VERSION 5.8 ;
BUSBITCHARS "[]" ;
DIVIDERCHAR "/" ;
UNITS
    DATABASE MICRONS 1000 ;
END UNITS

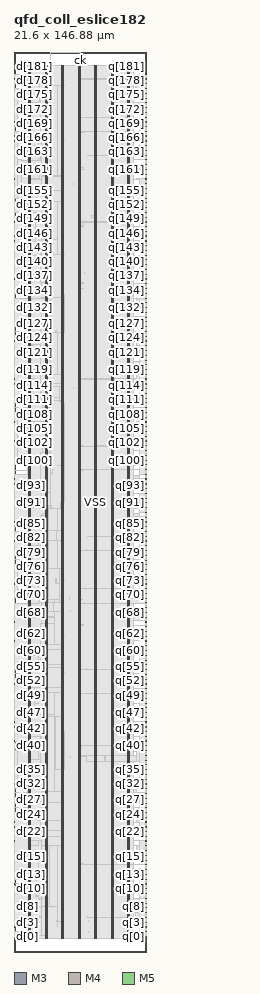
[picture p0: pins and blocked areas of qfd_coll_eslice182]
MACRO qfd_coll_eslice182
  FOREIGN qfd_coll_eslice182 0 0 ;
  CLASS BLOCK ;
  SIZE 21.6 BY 146.88 ;
  PIN ck
    DIRECTION INPUT ;
    USE SIGNAL ;
    PORT
      LAYER M3 ;
        RECT  10.8 146.842 10.818 146.88 ;
    END
    PORT
      LAYER M3 ;
        RECT  10.8 146.731 10.818 146.861 ;
    END
  END ck
  PIN d[0]
    DIRECTION INPUT ;
    USE SIGNAL ;
    PORT
      LAYER M4 ;
        RECT  0 2.544 0.084 2.568 ;
    END
  END d[0]
  PIN d[100]
    DIRECTION INPUT ;
    USE SIGNAL ;
    PORT
      LAYER M4 ;
        RECT  0 80.256 0.084 80.28 ;
    END
  END d[100]
  PIN d[101]
    DIRECTION INPUT ;
    USE SIGNAL ;
    PORT
      LAYER M4 ;
        RECT  0 81.072 0.084 81.096 ;
    END
  END d[101]
  PIN d[102]
    DIRECTION INPUT ;
    USE SIGNAL ;
    PORT
      LAYER M4 ;
        RECT  0 81.84 0.084 81.864 ;
    END
  END d[102]
  PIN d[103]
    DIRECTION INPUT ;
    USE SIGNAL ;
    PORT
      LAYER M4 ;
        RECT  0 82.608 0.084 82.632 ;
    END
  END d[103]
  PIN d[104]
    DIRECTION INPUT ;
    USE SIGNAL ;
    PORT
      LAYER M4 ;
        RECT  0 83.376 0.084 83.4 ;
    END
  END d[104]
  PIN d[105]
    DIRECTION INPUT ;
    USE SIGNAL ;
    PORT
      LAYER M4 ;
        RECT  0 84.144 0.084 84.168 ;
    END
  END d[105]
  PIN d[106]
    DIRECTION INPUT ;
    USE SIGNAL ;
    PORT
      LAYER M4 ;
        RECT  0 84.96 0.084 84.984 ;
    END
  END d[106]
  PIN d[107]
    DIRECTION INPUT ;
    USE SIGNAL ;
    PORT
      LAYER M4 ;
        RECT  0 85.728 0.084 85.752 ;
    END
  END d[107]
  PIN d[108]
    DIRECTION INPUT ;
    USE SIGNAL ;
    PORT
      LAYER M4 ;
        RECT  0 86.496 0.084 86.52 ;
    END
  END d[108]
  PIN d[109]
    DIRECTION INPUT ;
    USE SIGNAL ;
    PORT
      LAYER M4 ;
        RECT  0 87.264 0.084 87.288 ;
    END
  END d[109]
  PIN d[10]
    DIRECTION INPUT ;
    USE SIGNAL ;
    PORT
      LAYER M4 ;
        RECT  0 10.32 0.084 10.344 ;
    END
  END d[10]
  PIN d[110]
    DIRECTION INPUT ;
    USE SIGNAL ;
    PORT
      LAYER M4 ;
        RECT  0 88.032 0.084 88.056 ;
    END
  END d[110]
  PIN d[111]
    DIRECTION INPUT ;
    USE SIGNAL ;
    PORT
      LAYER M4 ;
        RECT  0 88.848 0.084 88.872 ;
    END
  END d[111]
  PIN d[112]
    DIRECTION INPUT ;
    USE SIGNAL ;
    PORT
      LAYER M4 ;
        RECT  0 89.616 0.084 89.64 ;
    END
  END d[112]
  PIN d[113]
    DIRECTION INPUT ;
    USE SIGNAL ;
    PORT
      LAYER M4 ;
        RECT  0 90.384 0.084 90.408 ;
    END
  END d[113]
  PIN d[114]
    DIRECTION INPUT ;
    USE SIGNAL ;
    PORT
      LAYER M4 ;
        RECT  0 91.152 0.084 91.176 ;
    END
  END d[114]
  PIN d[115]
    DIRECTION INPUT ;
    USE SIGNAL ;
    PORT
      LAYER M4 ;
        RECT  0 91.92 0.084 91.944 ;
    END
  END d[115]
  PIN d[116]
    DIRECTION INPUT ;
    USE SIGNAL ;
    PORT
      LAYER M4 ;
        RECT  0 92.688 0.084 92.712 ;
    END
  END d[116]
  PIN d[117]
    DIRECTION INPUT ;
    USE SIGNAL ;
    PORT
      LAYER M4 ;
        RECT  0 93.504 0.084 93.528 ;
    END
  END d[117]
  PIN d[118]
    DIRECTION INPUT ;
    USE SIGNAL ;
    PORT
      LAYER M4 ;
        RECT  0 94.272 0.084 94.296 ;
    END
  END d[118]
  PIN d[119]
    DIRECTION INPUT ;
    USE SIGNAL ;
    PORT
      LAYER M4 ;
        RECT  0 95.04 0.084 95.064 ;
    END
  END d[119]
  PIN d[11]
    DIRECTION INPUT ;
    USE SIGNAL ;
    PORT
      LAYER M4 ;
        RECT  0 11.088 0.084 11.112 ;
    END
  END d[11]
  PIN d[120]
    DIRECTION INPUT ;
    USE SIGNAL ;
    PORT
      LAYER M4 ;
        RECT  0 95.808 0.084 95.832 ;
    END
  END d[120]
  PIN d[121]
    DIRECTION INPUT ;
    USE SIGNAL ;
    PORT
      LAYER M4 ;
        RECT  0 96.576 0.084 96.6 ;
    END
  END d[121]
  PIN d[122]
    DIRECTION INPUT ;
    USE SIGNAL ;
    PORT
      LAYER M4 ;
        RECT  0 97.392 0.084 97.416 ;
    END
  END d[122]
  PIN d[123]
    DIRECTION INPUT ;
    USE SIGNAL ;
    PORT
      LAYER M4 ;
        RECT  0 98.16 0.084 98.184 ;
    END
  END d[123]
  PIN d[124]
    DIRECTION INPUT ;
    USE SIGNAL ;
    PORT
      LAYER M4 ;
        RECT  0 98.928 0.084 98.952 ;
    END
  END d[124]
  PIN d[125]
    DIRECTION INPUT ;
    USE SIGNAL ;
    PORT
      LAYER M4 ;
        RECT  0 99.696 0.084 99.72 ;
    END
  END d[125]
  PIN d[126]
    DIRECTION INPUT ;
    USE SIGNAL ;
    PORT
      LAYER M4 ;
        RECT  0 100.464 0.084 100.488 ;
    END
  END d[126]
  PIN d[127]
    DIRECTION INPUT ;
    USE SIGNAL ;
    PORT
      LAYER M4 ;
        RECT  0 101.28 0.084 101.304 ;
    END
  END d[127]
  PIN d[128]
    DIRECTION INPUT ;
    USE SIGNAL ;
    PORT
      LAYER M4 ;
        RECT  0 102.048 0.084 102.072 ;
    END
  END d[128]
  PIN d[129]
    DIRECTION INPUT ;
    USE SIGNAL ;
    PORT
      LAYER M4 ;
        RECT  0 102.816 0.084 102.84 ;
    END
  END d[129]
  PIN d[12]
    DIRECTION INPUT ;
    USE SIGNAL ;
    PORT
      LAYER M4 ;
        RECT  0 11.856 0.084 11.88 ;
    END
  END d[12]
  PIN d[130]
    DIRECTION INPUT ;
    USE SIGNAL ;
    PORT
      LAYER M4 ;
        RECT  0 103.584 0.084 103.608 ;
    END
  END d[130]
  PIN d[131]
    DIRECTION INPUT ;
    USE SIGNAL ;
    PORT
      LAYER M4 ;
        RECT  0 104.352 0.084 104.376 ;
    END
  END d[131]
  PIN d[132]
    DIRECTION INPUT ;
    USE SIGNAL ;
    PORT
      LAYER M4 ;
        RECT  0 105.168 0.084 105.192 ;
    END
  END d[132]
  PIN d[133]
    DIRECTION INPUT ;
    USE SIGNAL ;
    PORT
      LAYER M4 ;
        RECT  0 105.936 0.084 105.96 ;
    END
  END d[133]
  PIN d[134]
    DIRECTION INPUT ;
    USE SIGNAL ;
    PORT
      LAYER M4 ;
        RECT  0 106.704 0.084 106.728 ;
    END
  END d[134]
  PIN d[135]
    DIRECTION INPUT ;
    USE SIGNAL ;
    PORT
      LAYER M4 ;
        RECT  0 107.472 0.084 107.496 ;
    END
  END d[135]
  PIN d[136]
    DIRECTION INPUT ;
    USE SIGNAL ;
    PORT
      LAYER M4 ;
        RECT  0 108.24 0.084 108.264 ;
    END
  END d[136]
  PIN d[137]
    DIRECTION INPUT ;
    USE SIGNAL ;
    PORT
      LAYER M4 ;
        RECT  0 109.056 0.084 109.08 ;
    END
  END d[137]
  PIN d[138]
    DIRECTION INPUT ;
    USE SIGNAL ;
    PORT
      LAYER M4 ;
        RECT  0 109.824 0.084 109.848 ;
    END
  END d[138]
  PIN d[139]
    DIRECTION INPUT ;
    USE SIGNAL ;
    PORT
      LAYER M4 ;
        RECT  0 110.592 0.084 110.616 ;
    END
  END d[139]
  PIN d[13]
    DIRECTION INPUT ;
    USE SIGNAL ;
    PORT
      LAYER M4 ;
        RECT  0 12.624 0.084 12.648 ;
    END
  END d[13]
  PIN d[140]
    DIRECTION INPUT ;
    USE SIGNAL ;
    PORT
      LAYER M4 ;
        RECT  0 111.36 0.084 111.384 ;
    END
  END d[140]
  PIN d[141]
    DIRECTION INPUT ;
    USE SIGNAL ;
    PORT
      LAYER M4 ;
        RECT  0 112.128 0.084 112.152 ;
    END
  END d[141]
  PIN d[142]
    DIRECTION INPUT ;
    USE SIGNAL ;
    PORT
      LAYER M4 ;
        RECT  0 112.944 0.084 112.968 ;
    END
  END d[142]
  PIN d[143]
    DIRECTION INPUT ;
    USE SIGNAL ;
    PORT
      LAYER M4 ;
        RECT  0 113.712 0.084 113.736 ;
    END
  END d[143]
  PIN d[144]
    DIRECTION INPUT ;
    USE SIGNAL ;
    PORT
      LAYER M4 ;
        RECT  0 114.48 0.084 114.504 ;
    END
  END d[144]
  PIN d[145]
    DIRECTION INPUT ;
    USE SIGNAL ;
    PORT
      LAYER M4 ;
        RECT  0 115.248 0.084 115.272 ;
    END
  END d[145]
  PIN d[146]
    DIRECTION INPUT ;
    USE SIGNAL ;
    PORT
      LAYER M4 ;
        RECT  0 116.016 0.084 116.04 ;
    END
  END d[146]
  PIN d[147]
    DIRECTION INPUT ;
    USE SIGNAL ;
    PORT
      LAYER M4 ;
        RECT  0 116.832 0.084 116.856 ;
    END
  END d[147]
  PIN d[148]
    DIRECTION INPUT ;
    USE SIGNAL ;
    PORT
      LAYER M4 ;
        RECT  0 117.6 0.084 117.624 ;
    END
  END d[148]
  PIN d[149]
    DIRECTION INPUT ;
    USE SIGNAL ;
    PORT
      LAYER M4 ;
        RECT  0 118.368 0.084 118.392 ;
    END
  END d[149]
  PIN d[14]
    DIRECTION INPUT ;
    USE SIGNAL ;
    PORT
      LAYER M4 ;
        RECT  0 13.44 0.084 13.464 ;
    END
  END d[14]
  PIN d[150]
    DIRECTION INPUT ;
    USE SIGNAL ;
    PORT
      LAYER M4 ;
        RECT  0 119.136 0.084 119.16 ;
    END
  END d[150]
  PIN d[151]
    DIRECTION INPUT ;
    USE SIGNAL ;
    PORT
      LAYER M4 ;
        RECT  0 119.904 0.084 119.928 ;
    END
  END d[151]
  PIN d[152]
    DIRECTION INPUT ;
    USE SIGNAL ;
    PORT
      LAYER M4 ;
        RECT  0 120.72 0.084 120.744 ;
    END
  END d[152]
  PIN d[153]
    DIRECTION INPUT ;
    USE SIGNAL ;
    PORT
      LAYER M4 ;
        RECT  0 121.488 0.084 121.512 ;
    END
  END d[153]
  PIN d[154]
    DIRECTION INPUT ;
    USE SIGNAL ;
    PORT
      LAYER M4 ;
        RECT  0 122.256 0.084 122.28 ;
    END
  END d[154]
  PIN d[155]
    DIRECTION INPUT ;
    USE SIGNAL ;
    PORT
      LAYER M4 ;
        RECT  0 123.024 0.084 123.048 ;
    END
  END d[155]
  PIN d[156]
    DIRECTION INPUT ;
    USE SIGNAL ;
    PORT
      LAYER M4 ;
        RECT  0 123.792 0.084 123.816 ;
    END
  END d[156]
  PIN d[157]
    DIRECTION INPUT ;
    USE SIGNAL ;
    PORT
      LAYER M4 ;
        RECT  0 124.56 0.084 124.584 ;
    END
  END d[157]
  PIN d[158]
    DIRECTION INPUT ;
    USE SIGNAL ;
    PORT
      LAYER M4 ;
        RECT  0 125.376 0.084 125.4 ;
    END
  END d[158]
  PIN d[159]
    DIRECTION INPUT ;
    USE SIGNAL ;
    PORT
      LAYER M4 ;
        RECT  0 126.144 0.084 126.168 ;
    END
  END d[159]
  PIN d[15]
    DIRECTION INPUT ;
    USE SIGNAL ;
    PORT
      LAYER M4 ;
        RECT  0 14.208 0.084 14.232 ;
    END
  END d[15]
  PIN d[160]
    DIRECTION INPUT ;
    USE SIGNAL ;
    PORT
      LAYER M4 ;
        RECT  0 126.912 0.084 126.936 ;
    END
  END d[160]
  PIN d[161]
    DIRECTION INPUT ;
    USE SIGNAL ;
    PORT
      LAYER M4 ;
        RECT  0 127.68 0.084 127.704 ;
    END
  END d[161]
  PIN d[162]
    DIRECTION INPUT ;
    USE SIGNAL ;
    PORT
      LAYER M4 ;
        RECT  0 128.448 0.084 128.472 ;
    END
  END d[162]
  PIN d[163]
    DIRECTION INPUT ;
    USE SIGNAL ;
    PORT
      LAYER M4 ;
        RECT  0 129.264 0.084 129.288 ;
    END
  END d[163]
  PIN d[164]
    DIRECTION INPUT ;
    USE SIGNAL ;
    PORT
      LAYER M4 ;
        RECT  0 130.032 0.084 130.056 ;
    END
  END d[164]
  PIN d[165]
    DIRECTION INPUT ;
    USE SIGNAL ;
    PORT
      LAYER M4 ;
        RECT  0 130.8 0.084 130.824 ;
    END
  END d[165]
  PIN d[166]
    DIRECTION INPUT ;
    USE SIGNAL ;
    PORT
      LAYER M4 ;
        RECT  0 131.568 0.084 131.592 ;
    END
  END d[166]
  PIN d[167]
    DIRECTION INPUT ;
    USE SIGNAL ;
    PORT
      LAYER M4 ;
        RECT  0 132.336 0.084 132.36 ;
    END
  END d[167]
  PIN d[168]
    DIRECTION INPUT ;
    USE SIGNAL ;
    PORT
      LAYER M4 ;
        RECT  0 133.152 0.084 133.176 ;
    END
  END d[168]
  PIN d[169]
    DIRECTION INPUT ;
    USE SIGNAL ;
    PORT
      LAYER M4 ;
        RECT  0 133.92 0.084 133.944 ;
    END
  END d[169]
  PIN d[16]
    DIRECTION INPUT ;
    USE SIGNAL ;
    PORT
      LAYER M4 ;
        RECT  0 14.976 0.084 15 ;
    END
  END d[16]
  PIN d[170]
    DIRECTION INPUT ;
    USE SIGNAL ;
    PORT
      LAYER M4 ;
        RECT  0 134.688 0.084 134.712 ;
    END
  END d[170]
  PIN d[171]
    DIRECTION INPUT ;
    USE SIGNAL ;
    PORT
      LAYER M4 ;
        RECT  0 135.456 0.084 135.48 ;
    END
  END d[171]
  PIN d[172]
    DIRECTION INPUT ;
    USE SIGNAL ;
    PORT
      LAYER M4 ;
        RECT  0 136.224 0.084 136.248 ;
    END
  END d[172]
  PIN d[173]
    DIRECTION INPUT ;
    USE SIGNAL ;
    PORT
      LAYER M4 ;
        RECT  0 137.04 0.084 137.064 ;
    END
  END d[173]
  PIN d[174]
    DIRECTION INPUT ;
    USE SIGNAL ;
    PORT
      LAYER M4 ;
        RECT  0 137.808 0.084 137.832 ;
    END
  END d[174]
  PIN d[175]
    DIRECTION INPUT ;
    USE SIGNAL ;
    PORT
      LAYER M4 ;
        RECT  0 138.576 0.084 138.6 ;
    END
  END d[175]
  PIN d[176]
    DIRECTION INPUT ;
    USE SIGNAL ;
    PORT
      LAYER M4 ;
        RECT  0 139.344 0.084 139.368 ;
    END
  END d[176]
  PIN d[177]
    DIRECTION INPUT ;
    USE SIGNAL ;
    PORT
      LAYER M4 ;
        RECT  0 140.112 0.084 140.136 ;
    END
  END d[177]
  PIN d[178]
    DIRECTION INPUT ;
    USE SIGNAL ;
    PORT
      LAYER M4 ;
        RECT  0 140.928 0.084 140.952 ;
    END
  END d[178]
  PIN d[179]
    DIRECTION INPUT ;
    USE SIGNAL ;
    PORT
      LAYER M4 ;
        RECT  0 141.696 0.084 141.72 ;
    END
  END d[179]
  PIN d[17]
    DIRECTION INPUT ;
    USE SIGNAL ;
    PORT
      LAYER M4 ;
        RECT  0 15.744 0.084 15.768 ;
    END
  END d[17]
  PIN d[180]
    DIRECTION INPUT ;
    USE SIGNAL ;
    PORT
      LAYER M4 ;
        RECT  0 142.464 0.084 142.488 ;
    END
  END d[180]
  PIN d[181]
    DIRECTION INPUT ;
    USE SIGNAL ;
    PORT
      LAYER M4 ;
        RECT  0 143.232 0.084 143.256 ;
    END
  END d[181]
  PIN d[18]
    DIRECTION INPUT ;
    USE SIGNAL ;
    PORT
      LAYER M4 ;
        RECT  0 16.512 0.084 16.536 ;
    END
  END d[18]
  PIN d[19]
    DIRECTION INPUT ;
    USE SIGNAL ;
    PORT
      LAYER M4 ;
        RECT  0 17.328 0.084 17.352 ;
    END
  END d[19]
  PIN d[1]
    DIRECTION INPUT ;
    USE SIGNAL ;
    PORT
      LAYER M4 ;
        RECT  0 3.312 0.084 3.336 ;
    END
  END d[1]
  PIN d[20]
    DIRECTION INPUT ;
    USE SIGNAL ;
    PORT
      LAYER M4 ;
        RECT  0 18.096 0.084 18.12 ;
    END
  END d[20]
  PIN d[21]
    DIRECTION INPUT ;
    USE SIGNAL ;
    PORT
      LAYER M4 ;
        RECT  0 18.864 0.084 18.888 ;
    END
  END d[21]
  PIN d[22]
    DIRECTION INPUT ;
    USE SIGNAL ;
    PORT
      LAYER M4 ;
        RECT  0 19.632 0.084 19.656 ;
    END
  END d[22]
  PIN d[23]
    DIRECTION INPUT ;
    USE SIGNAL ;
    PORT
      LAYER M4 ;
        RECT  0 20.4 0.084 20.424 ;
    END
  END d[23]
  PIN d[24]
    DIRECTION INPUT ;
    USE SIGNAL ;
    PORT
      LAYER M4 ;
        RECT  0 21.216 0.084 21.24 ;
    END
  END d[24]
  PIN d[25]
    DIRECTION INPUT ;
    USE SIGNAL ;
    PORT
      LAYER M4 ;
        RECT  0 21.984 0.084 22.008 ;
    END
  END d[25]
  PIN d[26]
    DIRECTION INPUT ;
    USE SIGNAL ;
    PORT
      LAYER M4 ;
        RECT  0 22.752 0.084 22.776 ;
    END
  END d[26]
  PIN d[27]
    DIRECTION INPUT ;
    USE SIGNAL ;
    PORT
      LAYER M4 ;
        RECT  0 23.52 0.084 23.544 ;
    END
  END d[27]
  PIN d[28]
    DIRECTION INPUT ;
    USE SIGNAL ;
    PORT
      LAYER M4 ;
        RECT  0 24.288 0.084 24.312 ;
    END
  END d[28]
  PIN d[29]
    DIRECTION INPUT ;
    USE SIGNAL ;
    PORT
      LAYER M4 ;
        RECT  0 25.104 0.084 25.128 ;
    END
  END d[29]
  PIN d[2]
    DIRECTION INPUT ;
    USE SIGNAL ;
    PORT
      LAYER M4 ;
        RECT  0 4.08 0.084 4.104 ;
    END
  END d[2]
  PIN d[30]
    DIRECTION INPUT ;
    USE SIGNAL ;
    PORT
      LAYER M4 ;
        RECT  0 25.872 0.084 25.896 ;
    END
  END d[30]
  PIN d[31]
    DIRECTION INPUT ;
    USE SIGNAL ;
    PORT
      LAYER M4 ;
        RECT  0 26.64 0.084 26.664 ;
    END
  END d[31]
  PIN d[32]
    DIRECTION INPUT ;
    USE SIGNAL ;
    PORT
      LAYER M4 ;
        RECT  0 27.408 0.084 27.432 ;
    END
  END d[32]
  PIN d[33]
    DIRECTION INPUT ;
    USE SIGNAL ;
    PORT
      LAYER M4 ;
        RECT  0 28.176 0.084 28.2 ;
    END
  END d[33]
  PIN d[34]
    DIRECTION INPUT ;
    USE SIGNAL ;
    PORT
      LAYER M4 ;
        RECT  0 28.944 0.084 28.968 ;
    END
  END d[34]
  PIN d[35]
    DIRECTION INPUT ;
    USE SIGNAL ;
    PORT
      LAYER M4 ;
        RECT  0 29.76 0.084 29.784 ;
    END
  END d[35]
  PIN d[36]
    DIRECTION INPUT ;
    USE SIGNAL ;
    PORT
      LAYER M4 ;
        RECT  0 30.528 0.084 30.552 ;
    END
  END d[36]
  PIN d[37]
    DIRECTION INPUT ;
    USE SIGNAL ;
    PORT
      LAYER M4 ;
        RECT  0 31.296 0.084 31.32 ;
    END
  END d[37]
  PIN d[38]
    DIRECTION INPUT ;
    USE SIGNAL ;
    PORT
      LAYER M4 ;
        RECT  0 32.064 0.084 32.088 ;
    END
  END d[38]
  PIN d[39]
    DIRECTION INPUT ;
    USE SIGNAL ;
    PORT
      LAYER M4 ;
        RECT  0 32.832 0.084 32.856 ;
    END
  END d[39]
  PIN d[3]
    DIRECTION INPUT ;
    USE SIGNAL ;
    PORT
      LAYER M4 ;
        RECT  0 4.848 0.084 4.872 ;
    END
  END d[3]
  PIN d[40]
    DIRECTION INPUT ;
    USE SIGNAL ;
    PORT
      LAYER M4 ;
        RECT  0 33.648 0.084 33.672 ;
    END
  END d[40]
  PIN d[41]
    DIRECTION INPUT ;
    USE SIGNAL ;
    PORT
      LAYER M4 ;
        RECT  0 34.416 0.084 34.44 ;
    END
  END d[41]
  PIN d[42]
    DIRECTION INPUT ;
    USE SIGNAL ;
    PORT
      LAYER M4 ;
        RECT  0 35.184 0.084 35.208 ;
    END
  END d[42]
  PIN d[43]
    DIRECTION INPUT ;
    USE SIGNAL ;
    PORT
      LAYER M4 ;
        RECT  0 35.952 0.084 35.976 ;
    END
  END d[43]
  PIN d[44]
    DIRECTION INPUT ;
    USE SIGNAL ;
    PORT
      LAYER M4 ;
        RECT  0 36.72 0.084 36.744 ;
    END
  END d[44]
  PIN d[45]
    DIRECTION INPUT ;
    USE SIGNAL ;
    PORT
      LAYER M4 ;
        RECT  0 37.536 0.084 37.56 ;
    END
  END d[45]
  PIN d[46]
    DIRECTION INPUT ;
    USE SIGNAL ;
    PORT
      LAYER M4 ;
        RECT  0 38.304 0.084 38.328 ;
    END
  END d[46]
  PIN d[47]
    DIRECTION INPUT ;
    USE SIGNAL ;
    PORT
      LAYER M4 ;
        RECT  0 39.072 0.084 39.096 ;
    END
  END d[47]
  PIN d[48]
    DIRECTION INPUT ;
    USE SIGNAL ;
    PORT
      LAYER M4 ;
        RECT  0 39.84 0.084 39.864 ;
    END
  END d[48]
  PIN d[49]
    DIRECTION INPUT ;
    USE SIGNAL ;
    PORT
      LAYER M4 ;
        RECT  0 40.608 0.084 40.632 ;
    END
  END d[49]
  PIN d[4]
    DIRECTION INPUT ;
    USE SIGNAL ;
    PORT
      LAYER M4 ;
        RECT  0 5.664 0.084 5.688 ;
    END
  END d[4]
  PIN d[50]
    DIRECTION INPUT ;
    USE SIGNAL ;
    PORT
      LAYER M4 ;
        RECT  0 41.424 0.084 41.448 ;
    END
  END d[50]
  PIN d[51]
    DIRECTION INPUT ;
    USE SIGNAL ;
    PORT
      LAYER M4 ;
        RECT  0 42.192 0.084 42.216 ;
    END
  END d[51]
  PIN d[52]
    DIRECTION INPUT ;
    USE SIGNAL ;
    PORT
      LAYER M4 ;
        RECT  0 42.96 0.084 42.984 ;
    END
  END d[52]
  PIN d[53]
    DIRECTION INPUT ;
    USE SIGNAL ;
    PORT
      LAYER M4 ;
        RECT  0 43.728 0.084 43.752 ;
    END
  END d[53]
  PIN d[54]
    DIRECTION INPUT ;
    USE SIGNAL ;
    PORT
      LAYER M4 ;
        RECT  0 44.496 0.084 44.52 ;
    END
  END d[54]
  PIN d[55]
    DIRECTION INPUT ;
    USE SIGNAL ;
    PORT
      LAYER M4 ;
        RECT  0 45.312 0.084 45.336 ;
    END
  END d[55]
  PIN d[56]
    DIRECTION INPUT ;
    USE SIGNAL ;
    PORT
      LAYER M4 ;
        RECT  0 46.08 0.084 46.104 ;
    END
  END d[56]
  PIN d[57]
    DIRECTION INPUT ;
    USE SIGNAL ;
    PORT
      LAYER M4 ;
        RECT  0 46.848 0.084 46.872 ;
    END
  END d[57]
  PIN d[58]
    DIRECTION INPUT ;
    USE SIGNAL ;
    PORT
      LAYER M4 ;
        RECT  0 47.616 0.084 47.64 ;
    END
  END d[58]
  PIN d[59]
    DIRECTION INPUT ;
    USE SIGNAL ;
    PORT
      LAYER M4 ;
        RECT  0 48.384 0.084 48.408 ;
    END
  END d[59]
  PIN d[5]
    DIRECTION INPUT ;
    USE SIGNAL ;
    PORT
      LAYER M4 ;
        RECT  0 6.432 0.084 6.456 ;
    END
  END d[5]
  PIN d[60]
    DIRECTION INPUT ;
    USE SIGNAL ;
    PORT
      LAYER M4 ;
        RECT  0 49.2 0.084 49.224 ;
    END
  END d[60]
  PIN d[61]
    DIRECTION INPUT ;
    USE SIGNAL ;
    PORT
      LAYER M4 ;
        RECT  0 49.968 0.084 49.992 ;
    END
  END d[61]
  PIN d[62]
    DIRECTION INPUT ;
    USE SIGNAL ;
    PORT
      LAYER M4 ;
        RECT  0 50.736 0.084 50.76 ;
    END
  END d[62]
  PIN d[63]
    DIRECTION INPUT ;
    USE SIGNAL ;
    PORT
      LAYER M4 ;
        RECT  0 51.504 0.084 51.528 ;
    END
  END d[63]
  PIN d[64]
    DIRECTION INPUT ;
    USE SIGNAL ;
    PORT
      LAYER M4 ;
        RECT  0 52.272 0.084 52.296 ;
    END
  END d[64]
  PIN d[65]
    DIRECTION INPUT ;
    USE SIGNAL ;
    PORT
      LAYER M4 ;
        RECT  0 53.088 0.084 53.112 ;
    END
  END d[65]
  PIN d[66]
    DIRECTION INPUT ;
    USE SIGNAL ;
    PORT
      LAYER M4 ;
        RECT  0 53.856 0.084 53.88 ;
    END
  END d[66]
  PIN d[67]
    DIRECTION INPUT ;
    USE SIGNAL ;
    PORT
      LAYER M4 ;
        RECT  0 54.624 0.084 54.648 ;
    END
  END d[67]
  PIN d[68]
    DIRECTION INPUT ;
    USE SIGNAL ;
    PORT
      LAYER M4 ;
        RECT  0 55.392 0.084 55.416 ;
    END
  END d[68]
  PIN d[69]
    DIRECTION INPUT ;
    USE SIGNAL ;
    PORT
      LAYER M4 ;
        RECT  0 56.16 0.084 56.184 ;
    END
  END d[69]
  PIN d[6]
    DIRECTION INPUT ;
    USE SIGNAL ;
    PORT
      LAYER M4 ;
        RECT  0 7.2 0.084 7.224 ;
    END
  END d[6]
  PIN d[70]
    DIRECTION INPUT ;
    USE SIGNAL ;
    PORT
      LAYER M4 ;
        RECT  0 56.976 0.084 57 ;
    END
  END d[70]
  PIN d[71]
    DIRECTION INPUT ;
    USE SIGNAL ;
    PORT
      LAYER M4 ;
        RECT  0 57.744 0.084 57.768 ;
    END
  END d[71]
  PIN d[72]
    DIRECTION INPUT ;
    USE SIGNAL ;
    PORT
      LAYER M4 ;
        RECT  0 58.512 0.084 58.536 ;
    END
  END d[72]
  PIN d[73]
    DIRECTION INPUT ;
    USE SIGNAL ;
    PORT
      LAYER M4 ;
        RECT  0 59.28 0.084 59.304 ;
    END
  END d[73]
  PIN d[74]
    DIRECTION INPUT ;
    USE SIGNAL ;
    PORT
      LAYER M4 ;
        RECT  0 60.048 0.084 60.072 ;
    END
  END d[74]
  PIN d[75]
    DIRECTION INPUT ;
    USE SIGNAL ;
    PORT
      LAYER M4 ;
        RECT  0 60.816 0.084 60.84 ;
    END
  END d[75]
  PIN d[76]
    DIRECTION INPUT ;
    USE SIGNAL ;
    PORT
      LAYER M4 ;
        RECT  0 61.632 0.084 61.656 ;
    END
  END d[76]
  PIN d[77]
    DIRECTION INPUT ;
    USE SIGNAL ;
    PORT
      LAYER M4 ;
        RECT  0 62.4 0.084 62.424 ;
    END
  END d[77]
  PIN d[78]
    DIRECTION INPUT ;
    USE SIGNAL ;
    PORT
      LAYER M4 ;
        RECT  0 63.168 0.084 63.192 ;
    END
  END d[78]
  PIN d[79]
    DIRECTION INPUT ;
    USE SIGNAL ;
    PORT
      LAYER M4 ;
        RECT  0 63.936 0.084 63.96 ;
    END
  END d[79]
  PIN d[7]
    DIRECTION INPUT ;
    USE SIGNAL ;
    PORT
      LAYER M4 ;
        RECT  0 7.968 0.084 7.992 ;
    END
  END d[7]
  PIN d[80]
    DIRECTION INPUT ;
    USE SIGNAL ;
    PORT
      LAYER M4 ;
        RECT  0 64.704 0.084 64.728 ;
    END
  END d[80]
  PIN d[81]
    DIRECTION INPUT ;
    USE SIGNAL ;
    PORT
      LAYER M4 ;
        RECT  0 65.52 0.084 65.544 ;
    END
  END d[81]
  PIN d[82]
    DIRECTION INPUT ;
    USE SIGNAL ;
    PORT
      LAYER M4 ;
        RECT  0 66.288 0.084 66.312 ;
    END
  END d[82]
  PIN d[83]
    DIRECTION INPUT ;
    USE SIGNAL ;
    PORT
      LAYER M4 ;
        RECT  0 67.056 0.084 67.08 ;
    END
  END d[83]
  PIN d[84]
    DIRECTION INPUT ;
    USE SIGNAL ;
    PORT
      LAYER M4 ;
        RECT  0 67.824 0.084 67.848 ;
    END
  END d[84]
  PIN d[85]
    DIRECTION INPUT ;
    USE SIGNAL ;
    PORT
      LAYER M4 ;
        RECT  0 68.592 0.084 68.616 ;
    END
  END d[85]
  PIN d[86]
    DIRECTION INPUT ;
    USE SIGNAL ;
    PORT
      LAYER M4 ;
        RECT  0 69.408 0.084 69.432 ;
    END
  END d[86]
  PIN d[87]
    DIRECTION INPUT ;
    USE SIGNAL ;
    PORT
      LAYER M4 ;
        RECT  0 70.176 0.084 70.2 ;
    END
  END d[87]
  PIN d[88]
    DIRECTION INPUT ;
    USE SIGNAL ;
    PORT
      LAYER M4 ;
        RECT  0 70.944 0.084 70.968 ;
    END
  END d[88]
  PIN d[89]
    DIRECTION INPUT ;
    USE SIGNAL ;
    PORT
      LAYER M4 ;
        RECT  0 71.712 0.084 71.736 ;
    END
  END d[89]
  PIN d[8]
    DIRECTION INPUT ;
    USE SIGNAL ;
    PORT
      LAYER M4 ;
        RECT  0 8.736 0.084 8.76 ;
    END
  END d[8]
  PIN d[90]
    DIRECTION INPUT ;
    USE SIGNAL ;
    PORT
      LAYER M4 ;
        RECT  0 72.48 0.084 72.504 ;
    END
  END d[90]
  PIN d[91]
    DIRECTION INPUT ;
    USE SIGNAL ;
    PORT
      LAYER M4 ;
        RECT  0 73.296 0.084 73.32 ;
    END
  END d[91]
  PIN d[92]
    DIRECTION INPUT ;
    USE SIGNAL ;
    PORT
      LAYER M4 ;
        RECT  0 74.064 0.084 74.088 ;
    END
  END d[92]
  PIN d[93]
    DIRECTION INPUT ;
    USE SIGNAL ;
    PORT
      LAYER M4 ;
        RECT  0 74.832 0.084 74.856 ;
    END
  END d[93]
  PIN d[94]
    DIRECTION INPUT ;
    USE SIGNAL ;
    PORT
      LAYER M4 ;
        RECT  0 75.6 0.084 75.624 ;
    END
  END d[94]
  PIN d[95]
    DIRECTION INPUT ;
    USE SIGNAL ;
    PORT
      LAYER M4 ;
        RECT  0 76.368 0.084 76.392 ;
    END
  END d[95]
  PIN d[96]
    DIRECTION INPUT ;
    USE SIGNAL ;
    PORT
      LAYER M4 ;
        RECT  0 77.184 0.084 77.208 ;
    END
  END d[96]
  PIN d[97]
    DIRECTION INPUT ;
    USE SIGNAL ;
    PORT
      LAYER M4 ;
        RECT  0 77.952 0.084 77.976 ;
    END
  END d[97]
  PIN d[98]
    DIRECTION INPUT ;
    USE SIGNAL ;
    PORT
      LAYER M4 ;
        RECT  0 78.72 0.084 78.744 ;
    END
  END d[98]
  PIN d[99]
    DIRECTION INPUT ;
    USE SIGNAL ;
    PORT
      LAYER M4 ;
        RECT  0 79.488 0.084 79.512 ;
    END
  END d[99]
  PIN d[9]
    DIRECTION INPUT ;
    USE SIGNAL ;
    PORT
      LAYER M4 ;
        RECT  0 9.552 0.084 9.576 ;
    END
  END d[9]
  PIN q[0]
    DIRECTION OUTPUT ;
    USE SIGNAL ;
    PORT
      LAYER M4 ;
        RECT  21.516 2.544 21.6 2.568 ;
    END
  END q[0]
  PIN q[100]
    DIRECTION OUTPUT ;
    USE SIGNAL ;
    PORT
      LAYER M4 ;
        RECT  21.516 80.256 21.6 80.28 ;
    END
  END q[100]
  PIN q[101]
    DIRECTION OUTPUT ;
    USE SIGNAL ;
    PORT
      LAYER M4 ;
        RECT  21.516 81.072 21.6 81.096 ;
    END
  END q[101]
  PIN q[102]
    DIRECTION OUTPUT ;
    USE SIGNAL ;
    PORT
      LAYER M4 ;
        RECT  21.516 81.84 21.6 81.864 ;
    END
  END q[102]
  PIN q[103]
    DIRECTION OUTPUT ;
    USE SIGNAL ;
    PORT
      LAYER M4 ;
        RECT  21.516 82.608 21.6 82.632 ;
    END
  END q[103]
  PIN q[104]
    DIRECTION OUTPUT ;
    USE SIGNAL ;
    PORT
      LAYER M4 ;
        RECT  21.516 83.376 21.6 83.4 ;
    END
  END q[104]
  PIN q[105]
    DIRECTION OUTPUT ;
    USE SIGNAL ;
    PORT
      LAYER M4 ;
        RECT  21.516 84.144 21.6 84.168 ;
    END
  END q[105]
  PIN q[106]
    DIRECTION OUTPUT ;
    USE SIGNAL ;
    PORT
      LAYER M4 ;
        RECT  21.516 84.96 21.6 84.984 ;
    END
  END q[106]
  PIN q[107]
    DIRECTION OUTPUT ;
    USE SIGNAL ;
    PORT
      LAYER M4 ;
        RECT  21.516 85.728 21.6 85.752 ;
    END
  END q[107]
  PIN q[108]
    DIRECTION OUTPUT ;
    USE SIGNAL ;
    PORT
      LAYER M4 ;
        RECT  21.516 86.496 21.6 86.52 ;
    END
  END q[108]
  PIN q[109]
    DIRECTION OUTPUT ;
    USE SIGNAL ;
    PORT
      LAYER M4 ;
        RECT  21.516 87.264 21.6 87.288 ;
    END
  END q[109]
  PIN q[10]
    DIRECTION OUTPUT ;
    USE SIGNAL ;
    PORT
      LAYER M4 ;
        RECT  21.516 10.32 21.6 10.344 ;
    END
  END q[10]
  PIN q[110]
    DIRECTION OUTPUT ;
    USE SIGNAL ;
    PORT
      LAYER M4 ;
        RECT  21.516 88.032 21.6 88.056 ;
    END
  END q[110]
  PIN q[111]
    DIRECTION OUTPUT ;
    USE SIGNAL ;
    PORT
      LAYER M4 ;
        RECT  21.516 88.848 21.6 88.872 ;
    END
  END q[111]
  PIN q[112]
    DIRECTION OUTPUT ;
    USE SIGNAL ;
    PORT
      LAYER M4 ;
        RECT  21.516 89.616 21.6 89.64 ;
    END
  END q[112]
  PIN q[113]
    DIRECTION OUTPUT ;
    USE SIGNAL ;
    PORT
      LAYER M4 ;
        RECT  21.516 90.384 21.6 90.408 ;
    END
  END q[113]
  PIN q[114]
    DIRECTION OUTPUT ;
    USE SIGNAL ;
    PORT
      LAYER M4 ;
        RECT  21.516 91.152 21.6 91.176 ;
    END
  END q[114]
  PIN q[115]
    DIRECTION OUTPUT ;
    USE SIGNAL ;
    PORT
      LAYER M4 ;
        RECT  21.516 91.92 21.6 91.944 ;
    END
  END q[115]
  PIN q[116]
    DIRECTION OUTPUT ;
    USE SIGNAL ;
    PORT
      LAYER M4 ;
        RECT  21.516 92.688 21.6 92.712 ;
    END
  END q[116]
  PIN q[117]
    DIRECTION OUTPUT ;
    USE SIGNAL ;
    PORT
      LAYER M4 ;
        RECT  21.516 93.504 21.6 93.528 ;
    END
  END q[117]
  PIN q[118]
    DIRECTION OUTPUT ;
    USE SIGNAL ;
    PORT
      LAYER M4 ;
        RECT  21.516 94.272 21.6 94.296 ;
    END
  END q[118]
  PIN q[119]
    DIRECTION OUTPUT ;
    USE SIGNAL ;
    PORT
      LAYER M4 ;
        RECT  21.516 95.04 21.6 95.064 ;
    END
  END q[119]
  PIN q[11]
    DIRECTION OUTPUT ;
    USE SIGNAL ;
    PORT
      LAYER M4 ;
        RECT  21.516 11.088 21.6 11.112 ;
    END
  END q[11]
  PIN q[120]
    DIRECTION OUTPUT ;
    USE SIGNAL ;
    PORT
      LAYER M4 ;
        RECT  21.516 95.808 21.6 95.832 ;
    END
  END q[120]
  PIN q[121]
    DIRECTION OUTPUT ;
    USE SIGNAL ;
    PORT
      LAYER M4 ;
        RECT  21.516 96.576 21.6 96.6 ;
    END
  END q[121]
  PIN q[122]
    DIRECTION OUTPUT ;
    USE SIGNAL ;
    PORT
      LAYER M4 ;
        RECT  21.516 97.392 21.6 97.416 ;
    END
  END q[122]
  PIN q[123]
    DIRECTION OUTPUT ;
    USE SIGNAL ;
    PORT
      LAYER M4 ;
        RECT  21.516 98.16 21.6 98.184 ;
    END
  END q[123]
  PIN q[124]
    DIRECTION OUTPUT ;
    USE SIGNAL ;
    PORT
      LAYER M4 ;
        RECT  21.516 98.928 21.6 98.952 ;
    END
  END q[124]
  PIN q[125]
    DIRECTION OUTPUT ;
    USE SIGNAL ;
    PORT
      LAYER M4 ;
        RECT  21.516 99.696 21.6 99.72 ;
    END
  END q[125]
  PIN q[126]
    DIRECTION OUTPUT ;
    USE SIGNAL ;
    PORT
      LAYER M4 ;
        RECT  21.516 100.464 21.6 100.488 ;
    END
  END q[126]
  PIN q[127]
    DIRECTION OUTPUT ;
    USE SIGNAL ;
    PORT
      LAYER M4 ;
        RECT  21.516 101.28 21.6 101.304 ;
    END
  END q[127]
  PIN q[128]
    DIRECTION OUTPUT ;
    USE SIGNAL ;
    PORT
      LAYER M4 ;
        RECT  21.516 102.048 21.6 102.072 ;
    END
  END q[128]
  PIN q[129]
    DIRECTION OUTPUT ;
    USE SIGNAL ;
    PORT
      LAYER M4 ;
        RECT  21.516 102.816 21.6 102.84 ;
    END
  END q[129]
  PIN q[12]
    DIRECTION OUTPUT ;
    USE SIGNAL ;
    PORT
      LAYER M4 ;
        RECT  21.516 11.856 21.6 11.88 ;
    END
  END q[12]
  PIN q[130]
    DIRECTION OUTPUT ;
    USE SIGNAL ;
    PORT
      LAYER M4 ;
        RECT  21.516 103.584 21.6 103.608 ;
    END
  END q[130]
  PIN q[131]
    DIRECTION OUTPUT ;
    USE SIGNAL ;
    PORT
      LAYER M4 ;
        RECT  21.516 104.352 21.6 104.376 ;
    END
  END q[131]
  PIN q[132]
    DIRECTION OUTPUT ;
    USE SIGNAL ;
    PORT
      LAYER M4 ;
        RECT  21.516 105.168 21.6 105.192 ;
    END
  END q[132]
  PIN q[133]
    DIRECTION OUTPUT ;
    USE SIGNAL ;
    PORT
      LAYER M4 ;
        RECT  21.516 105.936 21.6 105.96 ;
    END
  END q[133]
  PIN q[134]
    DIRECTION OUTPUT ;
    USE SIGNAL ;
    PORT
      LAYER M4 ;
        RECT  21.516 106.704 21.6 106.728 ;
    END
  END q[134]
  PIN q[135]
    DIRECTION OUTPUT ;
    USE SIGNAL ;
    PORT
      LAYER M4 ;
        RECT  21.516 107.472 21.6 107.496 ;
    END
  END q[135]
  PIN q[136]
    DIRECTION OUTPUT ;
    USE SIGNAL ;
    PORT
      LAYER M4 ;
        RECT  21.516 108.24 21.6 108.264 ;
    END
  END q[136]
  PIN q[137]
    DIRECTION OUTPUT ;
    USE SIGNAL ;
    PORT
      LAYER M4 ;
        RECT  21.516 109.056 21.6 109.08 ;
    END
  END q[137]
  PIN q[138]
    DIRECTION OUTPUT ;
    USE SIGNAL ;
    PORT
      LAYER M4 ;
        RECT  21.516 109.824 21.6 109.848 ;
    END
  END q[138]
  PIN q[139]
    DIRECTION OUTPUT ;
    USE SIGNAL ;
    PORT
      LAYER M4 ;
        RECT  21.516 110.592 21.6 110.616 ;
    END
  END q[139]
  PIN q[13]
    DIRECTION OUTPUT ;
    USE SIGNAL ;
    PORT
      LAYER M4 ;
        RECT  21.516 12.624 21.6 12.648 ;
    END
  END q[13]
  PIN q[140]
    DIRECTION OUTPUT ;
    USE SIGNAL ;
    PORT
      LAYER M4 ;
        RECT  21.516 111.36 21.6 111.384 ;
    END
  END q[140]
  PIN q[141]
    DIRECTION OUTPUT ;
    USE SIGNAL ;
    PORT
      LAYER M4 ;
        RECT  21.516 112.128 21.6 112.152 ;
    END
  END q[141]
  PIN q[142]
    DIRECTION OUTPUT ;
    USE SIGNAL ;
    PORT
      LAYER M4 ;
        RECT  21.516 112.944 21.6 112.968 ;
    END
  END q[142]
  PIN q[143]
    DIRECTION OUTPUT ;
    USE SIGNAL ;
    PORT
      LAYER M4 ;
        RECT  21.516 113.712 21.6 113.736 ;
    END
  END q[143]
  PIN q[144]
    DIRECTION OUTPUT ;
    USE SIGNAL ;
    PORT
      LAYER M4 ;
        RECT  21.516 114.48 21.6 114.504 ;
    END
  END q[144]
  PIN q[145]
    DIRECTION OUTPUT ;
    USE SIGNAL ;
    PORT
      LAYER M4 ;
        RECT  21.516 115.248 21.6 115.272 ;
    END
  END q[145]
  PIN q[146]
    DIRECTION OUTPUT ;
    USE SIGNAL ;
    PORT
      LAYER M4 ;
        RECT  21.516 116.016 21.6 116.04 ;
    END
  END q[146]
  PIN q[147]
    DIRECTION OUTPUT ;
    USE SIGNAL ;
    PORT
      LAYER M4 ;
        RECT  21.516 116.832 21.6 116.856 ;
    END
  END q[147]
  PIN q[148]
    DIRECTION OUTPUT ;
    USE SIGNAL ;
    PORT
      LAYER M4 ;
        RECT  21.516 117.6 21.6 117.624 ;
    END
  END q[148]
  PIN q[149]
    DIRECTION OUTPUT ;
    USE SIGNAL ;
    PORT
      LAYER M4 ;
        RECT  21.516 118.368 21.6 118.392 ;
    END
  END q[149]
  PIN q[14]
    DIRECTION OUTPUT ;
    USE SIGNAL ;
    PORT
      LAYER M4 ;
        RECT  21.516 13.44 21.6 13.464 ;
    END
  END q[14]
  PIN q[150]
    DIRECTION OUTPUT ;
    USE SIGNAL ;
    PORT
      LAYER M4 ;
        RECT  21.516 119.136 21.6 119.16 ;
    END
  END q[150]
  PIN q[151]
    DIRECTION OUTPUT ;
    USE SIGNAL ;
    PORT
      LAYER M4 ;
        RECT  21.516 119.904 21.6 119.928 ;
    END
  END q[151]
  PIN q[152]
    DIRECTION OUTPUT ;
    USE SIGNAL ;
    PORT
      LAYER M4 ;
        RECT  21.516 120.72 21.6 120.744 ;
    END
  END q[152]
  PIN q[153]
    DIRECTION OUTPUT ;
    USE SIGNAL ;
    PORT
      LAYER M4 ;
        RECT  21.516 121.488 21.6 121.512 ;
    END
  END q[153]
  PIN q[154]
    DIRECTION OUTPUT ;
    USE SIGNAL ;
    PORT
      LAYER M4 ;
        RECT  21.516 122.256 21.6 122.28 ;
    END
  END q[154]
  PIN q[155]
    DIRECTION OUTPUT ;
    USE SIGNAL ;
    PORT
      LAYER M4 ;
        RECT  21.516 123.024 21.6 123.048 ;
    END
  END q[155]
  PIN q[156]
    DIRECTION OUTPUT ;
    USE SIGNAL ;
    PORT
      LAYER M4 ;
        RECT  21.516 123.792 21.6 123.816 ;
    END
  END q[156]
  PIN q[157]
    DIRECTION OUTPUT ;
    USE SIGNAL ;
    PORT
      LAYER M4 ;
        RECT  21.516 124.56 21.6 124.584 ;
    END
  END q[157]
  PIN q[158]
    DIRECTION OUTPUT ;
    USE SIGNAL ;
    PORT
      LAYER M4 ;
        RECT  21.516 125.376 21.6 125.4 ;
    END
  END q[158]
  PIN q[159]
    DIRECTION OUTPUT ;
    USE SIGNAL ;
    PORT
      LAYER M4 ;
        RECT  21.516 126.144 21.6 126.168 ;
    END
  END q[159]
  PIN q[15]
    DIRECTION OUTPUT ;
    USE SIGNAL ;
    PORT
      LAYER M4 ;
        RECT  21.516 14.208 21.6 14.232 ;
    END
  END q[15]
  PIN q[160]
    DIRECTION OUTPUT ;
    USE SIGNAL ;
    PORT
      LAYER M4 ;
        RECT  21.516 126.912 21.6 126.936 ;
    END
  END q[160]
  PIN q[161]
    DIRECTION OUTPUT ;
    USE SIGNAL ;
    PORT
      LAYER M4 ;
        RECT  21.516 127.68 21.6 127.704 ;
    END
  END q[161]
  PIN q[162]
    DIRECTION OUTPUT ;
    USE SIGNAL ;
    PORT
      LAYER M4 ;
        RECT  21.516 128.448 21.6 128.472 ;
    END
  END q[162]
  PIN q[163]
    DIRECTION OUTPUT ;
    USE SIGNAL ;
    PORT
      LAYER M4 ;
        RECT  21.516 129.264 21.6 129.288 ;
    END
  END q[163]
  PIN q[164]
    DIRECTION OUTPUT ;
    USE SIGNAL ;
    PORT
      LAYER M4 ;
        RECT  21.516 130.032 21.6 130.056 ;
    END
  END q[164]
  PIN q[165]
    DIRECTION OUTPUT ;
    USE SIGNAL ;
    PORT
      LAYER M4 ;
        RECT  21.516 130.8 21.6 130.824 ;
    END
  END q[165]
  PIN q[166]
    DIRECTION OUTPUT ;
    USE SIGNAL ;
    PORT
      LAYER M4 ;
        RECT  21.516 131.568 21.6 131.592 ;
    END
  END q[166]
  PIN q[167]
    DIRECTION OUTPUT ;
    USE SIGNAL ;
    PORT
      LAYER M4 ;
        RECT  21.516 132.336 21.6 132.36 ;
    END
  END q[167]
  PIN q[168]
    DIRECTION OUTPUT ;
    USE SIGNAL ;
    PORT
      LAYER M4 ;
        RECT  21.516 133.152 21.6 133.176 ;
    END
  END q[168]
  PIN q[169]
    DIRECTION OUTPUT ;
    USE SIGNAL ;
    PORT
      LAYER M4 ;
        RECT  21.516 133.92 21.6 133.944 ;
    END
  END q[169]
  PIN q[16]
    DIRECTION OUTPUT ;
    USE SIGNAL ;
    PORT
      LAYER M4 ;
        RECT  21.516 14.976 21.6 15 ;
    END
  END q[16]
  PIN q[170]
    DIRECTION OUTPUT ;
    USE SIGNAL ;
    PORT
      LAYER M4 ;
        RECT  21.516 134.688 21.6 134.712 ;
    END
  END q[170]
  PIN q[171]
    DIRECTION OUTPUT ;
    USE SIGNAL ;
    PORT
      LAYER M4 ;
        RECT  21.516 135.456 21.6 135.48 ;
    END
  END q[171]
  PIN q[172]
    DIRECTION OUTPUT ;
    USE SIGNAL ;
    PORT
      LAYER M4 ;
        RECT  21.516 136.224 21.6 136.248 ;
    END
  END q[172]
  PIN q[173]
    DIRECTION OUTPUT ;
    USE SIGNAL ;
    PORT
      LAYER M4 ;
        RECT  21.516 137.04 21.6 137.064 ;
    END
  END q[173]
  PIN q[174]
    DIRECTION OUTPUT ;
    USE SIGNAL ;
    PORT
      LAYER M4 ;
        RECT  21.516 137.808 21.6 137.832 ;
    END
  END q[174]
  PIN q[175]
    DIRECTION OUTPUT ;
    USE SIGNAL ;
    PORT
      LAYER M4 ;
        RECT  21.516 138.576 21.6 138.6 ;
    END
  END q[175]
  PIN q[176]
    DIRECTION OUTPUT ;
    USE SIGNAL ;
    PORT
      LAYER M4 ;
        RECT  21.516 139.344 21.6 139.368 ;
    END
  END q[176]
  PIN q[177]
    DIRECTION OUTPUT ;
    USE SIGNAL ;
    PORT
      LAYER M4 ;
        RECT  21.516 140.112 21.6 140.136 ;
    END
  END q[177]
  PIN q[178]
    DIRECTION OUTPUT ;
    USE SIGNAL ;
    PORT
      LAYER M4 ;
        RECT  21.516 140.928 21.6 140.952 ;
    END
  END q[178]
  PIN q[179]
    DIRECTION OUTPUT ;
    USE SIGNAL ;
    PORT
      LAYER M4 ;
        RECT  21.516 141.696 21.6 141.72 ;
    END
  END q[179]
  PIN q[17]
    DIRECTION OUTPUT ;
    USE SIGNAL ;
    PORT
      LAYER M4 ;
        RECT  21.516 15.744 21.6 15.768 ;
    END
  END q[17]
  PIN q[180]
    DIRECTION OUTPUT ;
    USE SIGNAL ;
    PORT
      LAYER M4 ;
        RECT  21.516 142.464 21.6 142.488 ;
    END
  END q[180]
  PIN q[181]
    DIRECTION OUTPUT ;
    USE SIGNAL ;
    PORT
      LAYER M4 ;
        RECT  21.516 143.232 21.6 143.256 ;
    END
  END q[181]
  PIN q[18]
    DIRECTION OUTPUT ;
    USE SIGNAL ;
    PORT
      LAYER M4 ;
        RECT  21.516 16.512 21.6 16.536 ;
    END
  END q[18]
  PIN q[19]
    DIRECTION OUTPUT ;
    USE SIGNAL ;
    PORT
      LAYER M4 ;
        RECT  21.516 17.328 21.6 17.352 ;
    END
  END q[19]
  PIN q[1]
    DIRECTION OUTPUT ;
    USE SIGNAL ;
    PORT
      LAYER M4 ;
        RECT  21.516 3.312 21.6 3.336 ;
    END
  END q[1]
  PIN q[20]
    DIRECTION OUTPUT ;
    USE SIGNAL ;
    PORT
      LAYER M4 ;
        RECT  21.516 18.096 21.6 18.12 ;
    END
  END q[20]
  PIN q[21]
    DIRECTION OUTPUT ;
    USE SIGNAL ;
    PORT
      LAYER M4 ;
        RECT  21.516 18.864 21.6 18.888 ;
    END
  END q[21]
  PIN q[22]
    DIRECTION OUTPUT ;
    USE SIGNAL ;
    PORT
      LAYER M4 ;
        RECT  21.516 19.632 21.6 19.656 ;
    END
  END q[22]
  PIN q[23]
    DIRECTION OUTPUT ;
    USE SIGNAL ;
    PORT
      LAYER M4 ;
        RECT  21.516 20.4 21.6 20.424 ;
    END
  END q[23]
  PIN q[24]
    DIRECTION OUTPUT ;
    USE SIGNAL ;
    PORT
      LAYER M4 ;
        RECT  21.516 21.216 21.6 21.24 ;
    END
  END q[24]
  PIN q[25]
    DIRECTION OUTPUT ;
    USE SIGNAL ;
    PORT
      LAYER M4 ;
        RECT  21.516 21.984 21.6 22.008 ;
    END
  END q[25]
  PIN q[26]
    DIRECTION OUTPUT ;
    USE SIGNAL ;
    PORT
      LAYER M4 ;
        RECT  21.516 22.752 21.6 22.776 ;
    END
  END q[26]
  PIN q[27]
    DIRECTION OUTPUT ;
    USE SIGNAL ;
    PORT
      LAYER M4 ;
        RECT  21.516 23.52 21.6 23.544 ;
    END
  END q[27]
  PIN q[28]
    DIRECTION OUTPUT ;
    USE SIGNAL ;
    PORT
      LAYER M4 ;
        RECT  21.516 24.288 21.6 24.312 ;
    END
  END q[28]
  PIN q[29]
    DIRECTION OUTPUT ;
    USE SIGNAL ;
    PORT
      LAYER M4 ;
        RECT  21.516 25.104 21.6 25.128 ;
    END
  END q[29]
  PIN q[2]
    DIRECTION OUTPUT ;
    USE SIGNAL ;
    PORT
      LAYER M4 ;
        RECT  21.516 4.08 21.6 4.104 ;
    END
  END q[2]
  PIN q[30]
    DIRECTION OUTPUT ;
    USE SIGNAL ;
    PORT
      LAYER M4 ;
        RECT  21.516 25.872 21.6 25.896 ;
    END
  END q[30]
  PIN q[31]
    DIRECTION OUTPUT ;
    USE SIGNAL ;
    PORT
      LAYER M4 ;
        RECT  21.516 26.64 21.6 26.664 ;
    END
  END q[31]
  PIN q[32]
    DIRECTION OUTPUT ;
    USE SIGNAL ;
    PORT
      LAYER M4 ;
        RECT  21.516 27.408 21.6 27.432 ;
    END
  END q[32]
  PIN q[33]
    DIRECTION OUTPUT ;
    USE SIGNAL ;
    PORT
      LAYER M4 ;
        RECT  21.516 28.176 21.6 28.2 ;
    END
  END q[33]
  PIN q[34]
    DIRECTION OUTPUT ;
    USE SIGNAL ;
    PORT
      LAYER M4 ;
        RECT  21.516 28.944 21.6 28.968 ;
    END
  END q[34]
  PIN q[35]
    DIRECTION OUTPUT ;
    USE SIGNAL ;
    PORT
      LAYER M4 ;
        RECT  21.516 29.76 21.6 29.784 ;
    END
  END q[35]
  PIN q[36]
    DIRECTION OUTPUT ;
    USE SIGNAL ;
    PORT
      LAYER M4 ;
        RECT  21.516 30.528 21.6 30.552 ;
    END
  END q[36]
  PIN q[37]
    DIRECTION OUTPUT ;
    USE SIGNAL ;
    PORT
      LAYER M4 ;
        RECT  21.516 31.296 21.6 31.32 ;
    END
  END q[37]
  PIN q[38]
    DIRECTION OUTPUT ;
    USE SIGNAL ;
    PORT
      LAYER M4 ;
        RECT  21.516 32.064 21.6 32.088 ;
    END
  END q[38]
  PIN q[39]
    DIRECTION OUTPUT ;
    USE SIGNAL ;
    PORT
      LAYER M4 ;
        RECT  21.516 32.832 21.6 32.856 ;
    END
  END q[39]
  PIN q[3]
    DIRECTION OUTPUT ;
    USE SIGNAL ;
    PORT
      LAYER M4 ;
        RECT  21.516 4.848 21.6 4.872 ;
    END
  END q[3]
  PIN q[40]
    DIRECTION OUTPUT ;
    USE SIGNAL ;
    PORT
      LAYER M4 ;
        RECT  21.516 33.648 21.6 33.672 ;
    END
  END q[40]
  PIN q[41]
    DIRECTION OUTPUT ;
    USE SIGNAL ;
    PORT
      LAYER M4 ;
        RECT  21.516 34.416 21.6 34.44 ;
    END
  END q[41]
  PIN q[42]
    DIRECTION OUTPUT ;
    USE SIGNAL ;
    PORT
      LAYER M4 ;
        RECT  21.516 35.184 21.6 35.208 ;
    END
  END q[42]
  PIN q[43]
    DIRECTION OUTPUT ;
    USE SIGNAL ;
    PORT
      LAYER M4 ;
        RECT  21.516 35.952 21.6 35.976 ;
    END
  END q[43]
  PIN q[44]
    DIRECTION OUTPUT ;
    USE SIGNAL ;
    PORT
      LAYER M4 ;
        RECT  21.516 36.72 21.6 36.744 ;
    END
  END q[44]
  PIN q[45]
    DIRECTION OUTPUT ;
    USE SIGNAL ;
    PORT
      LAYER M4 ;
        RECT  21.516 37.536 21.6 37.56 ;
    END
  END q[45]
  PIN q[46]
    DIRECTION OUTPUT ;
    USE SIGNAL ;
    PORT
      LAYER M4 ;
        RECT  21.516 38.304 21.6 38.328 ;
    END
  END q[46]
  PIN q[47]
    DIRECTION OUTPUT ;
    USE SIGNAL ;
    PORT
      LAYER M4 ;
        RECT  21.516 39.072 21.6 39.096 ;
    END
  END q[47]
  PIN q[48]
    DIRECTION OUTPUT ;
    USE SIGNAL ;
    PORT
      LAYER M4 ;
        RECT  21.516 39.84 21.6 39.864 ;
    END
  END q[48]
  PIN q[49]
    DIRECTION OUTPUT ;
    USE SIGNAL ;
    PORT
      LAYER M4 ;
        RECT  21.516 40.608 21.6 40.632 ;
    END
  END q[49]
  PIN q[4]
    DIRECTION OUTPUT ;
    USE SIGNAL ;
    PORT
      LAYER M4 ;
        RECT  21.516 5.664 21.6 5.688 ;
    END
  END q[4]
  PIN q[50]
    DIRECTION OUTPUT ;
    USE SIGNAL ;
    PORT
      LAYER M4 ;
        RECT  21.516 41.424 21.6 41.448 ;
    END
  END q[50]
  PIN q[51]
    DIRECTION OUTPUT ;
    USE SIGNAL ;
    PORT
      LAYER M4 ;
        RECT  21.516 42.192 21.6 42.216 ;
    END
  END q[51]
  PIN q[52]
    DIRECTION OUTPUT ;
    USE SIGNAL ;
    PORT
      LAYER M4 ;
        RECT  21.516 42.96 21.6 42.984 ;
    END
  END q[52]
  PIN q[53]
    DIRECTION OUTPUT ;
    USE SIGNAL ;
    PORT
      LAYER M4 ;
        RECT  21.516 43.728 21.6 43.752 ;
    END
  END q[53]
  PIN q[54]
    DIRECTION OUTPUT ;
    USE SIGNAL ;
    PORT
      LAYER M4 ;
        RECT  21.516 44.496 21.6 44.52 ;
    END
  END q[54]
  PIN q[55]
    DIRECTION OUTPUT ;
    USE SIGNAL ;
    PORT
      LAYER M4 ;
        RECT  21.516 45.312 21.6 45.336 ;
    END
  END q[55]
  PIN q[56]
    DIRECTION OUTPUT ;
    USE SIGNAL ;
    PORT
      LAYER M4 ;
        RECT  21.516 46.08 21.6 46.104 ;
    END
  END q[56]
  PIN q[57]
    DIRECTION OUTPUT ;
    USE SIGNAL ;
    PORT
      LAYER M4 ;
        RECT  21.516 46.848 21.6 46.872 ;
    END
  END q[57]
  PIN q[58]
    DIRECTION OUTPUT ;
    USE SIGNAL ;
    PORT
      LAYER M4 ;
        RECT  21.516 47.616 21.6 47.64 ;
    END
  END q[58]
  PIN q[59]
    DIRECTION OUTPUT ;
    USE SIGNAL ;
    PORT
      LAYER M4 ;
        RECT  21.516 48.384 21.6 48.408 ;
    END
  END q[59]
  PIN q[5]
    DIRECTION OUTPUT ;
    USE SIGNAL ;
    PORT
      LAYER M4 ;
        RECT  21.516 6.432 21.6 6.456 ;
    END
  END q[5]
  PIN q[60]
    DIRECTION OUTPUT ;
    USE SIGNAL ;
    PORT
      LAYER M4 ;
        RECT  21.516 49.2 21.6 49.224 ;
    END
  END q[60]
  PIN q[61]
    DIRECTION OUTPUT ;
    USE SIGNAL ;
    PORT
      LAYER M4 ;
        RECT  21.516 49.968 21.6 49.992 ;
    END
  END q[61]
  PIN q[62]
    DIRECTION OUTPUT ;
    USE SIGNAL ;
    PORT
      LAYER M4 ;
        RECT  21.516 50.736 21.6 50.76 ;
    END
  END q[62]
  PIN q[63]
    DIRECTION OUTPUT ;
    USE SIGNAL ;
    PORT
      LAYER M4 ;
        RECT  21.516 51.504 21.6 51.528 ;
    END
  END q[63]
  PIN q[64]
    DIRECTION OUTPUT ;
    USE SIGNAL ;
    PORT
      LAYER M4 ;
        RECT  21.516 52.272 21.6 52.296 ;
    END
  END q[64]
  PIN q[65]
    DIRECTION OUTPUT ;
    USE SIGNAL ;
    PORT
      LAYER M4 ;
        RECT  21.516 53.088 21.6 53.112 ;
    END
  END q[65]
  PIN q[66]
    DIRECTION OUTPUT ;
    USE SIGNAL ;
    PORT
      LAYER M4 ;
        RECT  21.516 53.856 21.6 53.88 ;
    END
  END q[66]
  PIN q[67]
    DIRECTION OUTPUT ;
    USE SIGNAL ;
    PORT
      LAYER M4 ;
        RECT  21.516 54.624 21.6 54.648 ;
    END
  END q[67]
  PIN q[68]
    DIRECTION OUTPUT ;
    USE SIGNAL ;
    PORT
      LAYER M4 ;
        RECT  21.516 55.392 21.6 55.416 ;
    END
  END q[68]
  PIN q[69]
    DIRECTION OUTPUT ;
    USE SIGNAL ;
    PORT
      LAYER M4 ;
        RECT  21.516 56.16 21.6 56.184 ;
    END
  END q[69]
  PIN q[6]
    DIRECTION OUTPUT ;
    USE SIGNAL ;
    PORT
      LAYER M4 ;
        RECT  21.516 7.2 21.6 7.224 ;
    END
  END q[6]
  PIN q[70]
    DIRECTION OUTPUT ;
    USE SIGNAL ;
    PORT
      LAYER M4 ;
        RECT  21.516 56.976 21.6 57 ;
    END
  END q[70]
  PIN q[71]
    DIRECTION OUTPUT ;
    USE SIGNAL ;
    PORT
      LAYER M4 ;
        RECT  21.516 57.744 21.6 57.768 ;
    END
  END q[71]
  PIN q[72]
    DIRECTION OUTPUT ;
    USE SIGNAL ;
    PORT
      LAYER M4 ;
        RECT  21.516 58.512 21.6 58.536 ;
    END
  END q[72]
  PIN q[73]
    DIRECTION OUTPUT ;
    USE SIGNAL ;
    PORT
      LAYER M4 ;
        RECT  21.516 59.28 21.6 59.304 ;
    END
  END q[73]
  PIN q[74]
    DIRECTION OUTPUT ;
    USE SIGNAL ;
    PORT
      LAYER M4 ;
        RECT  21.516 60.048 21.6 60.072 ;
    END
  END q[74]
  PIN q[75]
    DIRECTION OUTPUT ;
    USE SIGNAL ;
    PORT
      LAYER M4 ;
        RECT  21.516 60.816 21.6 60.84 ;
    END
  END q[75]
  PIN q[76]
    DIRECTION OUTPUT ;
    USE SIGNAL ;
    PORT
      LAYER M4 ;
        RECT  21.516 61.632 21.6 61.656 ;
    END
  END q[76]
  PIN q[77]
    DIRECTION OUTPUT ;
    USE SIGNAL ;
    PORT
      LAYER M4 ;
        RECT  21.516 62.4 21.6 62.424 ;
    END
  END q[77]
  PIN q[78]
    DIRECTION OUTPUT ;
    USE SIGNAL ;
    PORT
      LAYER M4 ;
        RECT  21.516 63.168 21.6 63.192 ;
    END
  END q[78]
  PIN q[79]
    DIRECTION OUTPUT ;
    USE SIGNAL ;
    PORT
      LAYER M4 ;
        RECT  21.516 63.936 21.6 63.96 ;
    END
  END q[79]
  PIN q[7]
    DIRECTION OUTPUT ;
    USE SIGNAL ;
    PORT
      LAYER M4 ;
        RECT  21.516 7.968 21.6 7.992 ;
    END
  END q[7]
  PIN q[80]
    DIRECTION OUTPUT ;
    USE SIGNAL ;
    PORT
      LAYER M4 ;
        RECT  21.516 64.704 21.6 64.728 ;
    END
  END q[80]
  PIN q[81]
    DIRECTION OUTPUT ;
    USE SIGNAL ;
    PORT
      LAYER M4 ;
        RECT  21.516 65.52 21.6 65.544 ;
    END
  END q[81]
  PIN q[82]
    DIRECTION OUTPUT ;
    USE SIGNAL ;
    PORT
      LAYER M4 ;
        RECT  21.516 66.288 21.6 66.312 ;
    END
  END q[82]
  PIN q[83]
    DIRECTION OUTPUT ;
    USE SIGNAL ;
    PORT
      LAYER M4 ;
        RECT  21.516 67.056 21.6 67.08 ;
    END
  END q[83]
  PIN q[84]
    DIRECTION OUTPUT ;
    USE SIGNAL ;
    PORT
      LAYER M4 ;
        RECT  21.516 67.824 21.6 67.848 ;
    END
  END q[84]
  PIN q[85]
    DIRECTION OUTPUT ;
    USE SIGNAL ;
    PORT
      LAYER M4 ;
        RECT  21.516 68.592 21.6 68.616 ;
    END
  END q[85]
  PIN q[86]
    DIRECTION OUTPUT ;
    USE SIGNAL ;
    PORT
      LAYER M4 ;
        RECT  21.516 69.408 21.6 69.432 ;
    END
  END q[86]
  PIN q[87]
    DIRECTION OUTPUT ;
    USE SIGNAL ;
    PORT
      LAYER M4 ;
        RECT  21.516 70.176 21.6 70.2 ;
    END
  END q[87]
  PIN q[88]
    DIRECTION OUTPUT ;
    USE SIGNAL ;
    PORT
      LAYER M4 ;
        RECT  21.516 70.944 21.6 70.968 ;
    END
  END q[88]
  PIN q[89]
    DIRECTION OUTPUT ;
    USE SIGNAL ;
    PORT
      LAYER M4 ;
        RECT  21.516 71.712 21.6 71.736 ;
    END
  END q[89]
  PIN q[8]
    DIRECTION OUTPUT ;
    USE SIGNAL ;
    PORT
      LAYER M4 ;
        RECT  21.516 8.736 21.6 8.76 ;
    END
  END q[8]
  PIN q[90]
    DIRECTION OUTPUT ;
    USE SIGNAL ;
    PORT
      LAYER M4 ;
        RECT  21.516 72.48 21.6 72.504 ;
    END
  END q[90]
  PIN q[91]
    DIRECTION OUTPUT ;
    USE SIGNAL ;
    PORT
      LAYER M4 ;
        RECT  21.516 73.296 21.6 73.32 ;
    END
  END q[91]
  PIN q[92]
    DIRECTION OUTPUT ;
    USE SIGNAL ;
    PORT
      LAYER M4 ;
        RECT  21.516 74.064 21.6 74.088 ;
    END
  END q[92]
  PIN q[93]
    DIRECTION OUTPUT ;
    USE SIGNAL ;
    PORT
      LAYER M4 ;
        RECT  21.516 74.832 21.6 74.856 ;
    END
  END q[93]
  PIN q[94]
    DIRECTION OUTPUT ;
    USE SIGNAL ;
    PORT
      LAYER M4 ;
        RECT  21.516 75.6 21.6 75.624 ;
    END
  END q[94]
  PIN q[95]
    DIRECTION OUTPUT ;
    USE SIGNAL ;
    PORT
      LAYER M4 ;
        RECT  21.516 76.368 21.6 76.392 ;
    END
  END q[95]
  PIN q[96]
    DIRECTION OUTPUT ;
    USE SIGNAL ;
    PORT
      LAYER M4 ;
        RECT  21.516 77.184 21.6 77.208 ;
    END
  END q[96]
  PIN q[97]
    DIRECTION OUTPUT ;
    USE SIGNAL ;
    PORT
      LAYER M4 ;
        RECT  21.516 77.952 21.6 77.976 ;
    END
  END q[97]
  PIN q[98]
    DIRECTION OUTPUT ;
    USE SIGNAL ;
    PORT
      LAYER M4 ;
        RECT  21.516 78.72 21.6 78.744 ;
    END
  END q[98]
  PIN q[99]
    DIRECTION OUTPUT ;
    USE SIGNAL ;
    PORT
      LAYER M4 ;
        RECT  21.516 79.488 21.6 79.512 ;
    END
  END q[99]
  PIN q[9]
    DIRECTION OUTPUT ;
    USE SIGNAL ;
    PORT
      LAYER M4 ;
        RECT  21.516 9.552 21.6 9.576 ;
    END
  END q[9]
  PIN VDD
    DIRECTION INOUT ;
    USE POWER ;
    PORT
      LAYER M5 ;
        RECT  18.792 2.151 18.912 144.729 ;
        RECT  16.092 2.151 16.212 144.729 ;
        RECT  13.392 2.151 13.512 144.729 ;
        RECT  10.692 2.151 10.812 144.729 ;
        RECT  7.992 2.151 8.112 144.729 ;
        RECT  5.292 2.151 5.412 144.729 ;
        RECT  2.592 2.151 2.712 144.729 ;
    END
  END VDD
  PIN VSS
    DIRECTION INOUT ;
    USE GROUND ;
    PORT
      LAYER M5 ;
        RECT  18.6 2.137 18.72 144.743 ;
        RECT  15.9 2.137 16.02 144.743 ;
        RECT  13.2 2.137 13.32 144.743 ;
        RECT  10.5 2.137 10.62 144.743 ;
        RECT  7.8 2.137 7.92 144.743 ;
        RECT  5.1 2.137 5.22 144.743 ;
        RECT  2.4 2.137 2.52 144.743 ;
    END
  END VSS
  # OT_OBS_CLOSED layer=M5 d_um=1.536 added=36
  OBS
    LAYER RVTN ;
     RECT  2.16 2.16 19.44 2.295 ;
     RECT  2.16 2.565 19.44 2.835 ;
     RECT  2.16 3.105 19.44 3.375 ;
     RECT  2.16 3.645 19.44 3.915 ;
     RECT  2.16 4.185 19.44 4.455 ;
     RECT  2.16 4.725 19.44 4.995 ;
     RECT  2.16 5.265 19.44 5.535 ;
     RECT  2.16 5.805 19.44 6.075 ;
     RECT  2.16 6.345 19.44 6.615 ;
     RECT  2.16 6.885 19.44 7.155 ;
     RECT  2.16 7.425 19.44 7.695 ;
     RECT  2.16 7.965 19.44 8.235 ;
     RECT  2.16 8.505 19.44 8.775 ;
     RECT  2.16 9.045 19.44 9.315 ;
     RECT  2.16 9.585 19.44 9.855 ;
     RECT  2.16 10.125 19.44 10.395 ;
     RECT  2.16 10.665 19.44 10.935 ;
     RECT  2.16 11.205 19.44 11.475 ;
     RECT  2.16 11.745 19.44 12.015 ;
     RECT  2.16 12.285 19.44 12.555 ;
     RECT  2.16 12.825 19.44 13.095 ;
     RECT  2.16 13.365 19.44 13.635 ;
     RECT  2.16 13.905 19.44 14.175 ;
     RECT  2.16 14.445 19.44 14.715 ;
     RECT  2.16 14.985 19.44 15.255 ;
     RECT  2.16 15.525 19.44 15.795 ;
     RECT  2.16 16.065 19.44 16.335 ;
     RECT  2.16 16.605 19.44 16.875 ;
     RECT  2.16 17.145 19.44 17.415 ;
     RECT  2.16 17.685 19.44 17.955 ;
     RECT  2.16 18.225 19.44 18.495 ;
     RECT  2.16 18.765 19.44 19.035 ;
     RECT  2.16 19.305 19.44 19.575 ;
     RECT  2.16 19.845 19.44 20.115 ;
     RECT  2.16 20.385 19.44 20.655 ;
     RECT  2.16 20.925 19.44 21.195 ;
     RECT  2.16 21.465 19.44 21.735 ;
     RECT  2.16 22.005 19.44 22.275 ;
     RECT  2.16 22.545 19.44 22.815 ;
     RECT  2.16 23.085 19.44 23.355 ;
     RECT  2.16 23.625 19.44 23.895 ;
     RECT  2.16 24.165 19.44 24.435 ;
     RECT  2.16 24.705 19.44 24.975 ;
     RECT  2.16 25.245 19.44 25.515 ;
     RECT  2.16 25.785 19.44 26.055 ;
     RECT  2.16 26.325 19.44 26.595 ;
     RECT  2.16 26.865 19.44 27.135 ;
     RECT  2.16 27.405 19.44 27.675 ;
     RECT  2.16 27.945 19.44 28.215 ;
     RECT  2.16 28.485 19.44 28.755 ;
     RECT  2.16 29.025 19.44 29.295 ;
     RECT  2.16 29.565 19.44 29.835 ;
     RECT  2.16 30.105 19.44 30.375 ;
     RECT  2.16 30.645 19.44 30.915 ;
     RECT  2.16 31.185 19.44 31.455 ;
     RECT  2.16 31.725 19.44 31.995 ;
     RECT  2.16 32.265 19.44 32.535 ;
     RECT  2.16 32.805 19.44 33.075 ;
     RECT  2.16 33.345 19.44 33.615 ;
     RECT  2.16 33.885 19.44 34.155 ;
     RECT  2.16 34.425 19.44 34.695 ;
     RECT  2.16 34.965 19.44 35.235 ;
     RECT  2.16 35.505 19.44 35.775 ;
     RECT  2.16 36.045 19.44 36.315 ;
     RECT  2.16 36.585 19.44 36.855 ;
     RECT  2.16 37.125 19.44 37.395 ;
     RECT  2.16 37.665 19.44 37.935 ;
     RECT  2.16 38.205 19.44 38.475 ;
     RECT  2.16 38.745 19.44 39.015 ;
     RECT  2.16 39.285 19.44 39.555 ;
     RECT  2.16 39.825 19.44 40.095 ;
     RECT  2.16 40.365 19.44 40.635 ;
     RECT  2.16 40.905 19.44 41.175 ;
     RECT  2.16 41.445 19.44 41.715 ;
     RECT  2.16 41.985 19.44 42.255 ;
     RECT  2.16 42.525 19.44 42.795 ;
     RECT  2.16 43.065 19.44 43.335 ;
     RECT  2.16 43.605 19.44 43.875 ;
     RECT  2.16 44.145 19.44 44.415 ;
     RECT  2.16 44.685 19.44 44.955 ;
     RECT  2.16 45.225 19.44 45.495 ;
     RECT  2.16 45.765 19.44 46.035 ;
     RECT  2.16 46.305 19.44 46.575 ;
     RECT  2.16 46.845 19.44 47.115 ;
     RECT  2.16 47.385 19.44 47.655 ;
     RECT  2.16 47.925 19.44 48.195 ;
     RECT  2.16 48.465 19.44 48.735 ;
     RECT  2.16 49.005 19.44 49.275 ;
     RECT  2.16 49.545 19.44 49.815 ;
     RECT  2.16 50.085 19.44 50.355 ;
     RECT  2.16 50.625 19.44 50.895 ;
     RECT  2.16 51.165 19.44 51.435 ;
     RECT  2.16 51.705 19.44 51.975 ;
     RECT  2.16 52.245 19.44 52.515 ;
     RECT  2.16 52.785 19.44 53.055 ;
     RECT  2.16 53.325 19.44 53.595 ;
     RECT  2.16 53.865 19.44 54.135 ;
     RECT  2.16 54.405 19.44 54.675 ;
     RECT  2.16 54.945 19.44 55.215 ;
     RECT  2.16 55.485 19.44 55.755 ;
     RECT  2.16 56.025 19.44 56.295 ;
     RECT  2.16 56.565 19.44 56.835 ;
     RECT  2.16 57.105 19.44 57.375 ;
     RECT  2.16 57.645 19.44 57.915 ;
     RECT  2.16 58.185 19.44 58.455 ;
     RECT  2.16 58.725 19.44 58.995 ;
     RECT  2.16 59.265 19.44 59.535 ;
     RECT  2.16 59.805 19.44 60.075 ;
     RECT  2.16 60.345 19.44 60.615 ;
     RECT  2.16 60.885 19.44 61.155 ;
     RECT  2.16 61.425 19.44 61.695 ;
     RECT  2.16 61.965 19.44 62.235 ;
     RECT  2.16 62.505 19.44 62.775 ;
     RECT  2.16 63.045 19.44 63.315 ;
     RECT  2.16 63.585 19.44 63.855 ;
     RECT  2.16 64.125 19.44 64.395 ;
     RECT  2.16 64.665 19.44 64.935 ;
     RECT  2.16 65.205 19.44 65.475 ;
     RECT  2.16 65.745 19.44 66.015 ;
     RECT  2.16 66.285 19.44 66.555 ;
     RECT  2.16 66.825 19.44 67.095 ;
     RECT  2.16 67.365 19.44 67.635 ;
     RECT  2.16 67.905 19.44 68.175 ;
     RECT  2.16 68.445 19.44 68.715 ;
     RECT  2.16 68.985 19.44 69.255 ;
     RECT  2.16 69.525 19.44 69.795 ;
     RECT  2.16 70.065 19.44 70.335 ;
     RECT  2.16 70.605 19.44 70.875 ;
     RECT  2.16 71.145 19.44 71.415 ;
     RECT  2.16 71.685 19.44 71.955 ;
     RECT  2.16 72.225 19.44 72.495 ;
     RECT  2.16 72.765 19.44 73.035 ;
     RECT  2.16 73.305 19.44 73.575 ;
     RECT  2.16 73.845 19.44 74.115 ;
     RECT  2.16 74.385 19.44 74.655 ;
     RECT  2.16 74.925 19.44 75.195 ;
     RECT  2.16 75.465 19.44 75.735 ;
     RECT  2.16 76.005 19.44 76.275 ;
     RECT  2.16 76.545 19.44 76.815 ;
     RECT  2.16 77.085 19.44 77.355 ;
     RECT  2.16 77.625 19.44 77.895 ;
     RECT  2.16 78.165 19.44 78.435 ;
     RECT  2.16 78.705 19.44 78.975 ;
     RECT  2.16 79.245 19.44 79.515 ;
     RECT  2.16 79.785 19.44 80.055 ;
     RECT  2.16 80.325 19.44 80.595 ;
     RECT  2.16 80.865 19.44 81.135 ;
     RECT  2.16 81.405 19.44 81.675 ;
     RECT  2.16 81.945 19.44 82.215 ;
     RECT  2.16 82.485 19.44 82.755 ;
     RECT  2.16 83.025 19.44 83.295 ;
     RECT  2.16 83.565 19.44 83.835 ;
     RECT  2.16 84.105 19.44 84.375 ;
     RECT  2.16 84.645 19.44 84.915 ;
     RECT  2.16 85.185 19.44 85.455 ;
     RECT  2.16 85.725 19.44 85.995 ;
     RECT  2.16 86.265 19.44 86.535 ;
     RECT  2.16 86.805 19.44 87.075 ;
     RECT  2.16 87.345 19.44 87.615 ;
     RECT  2.16 87.885 19.44 88.155 ;
     RECT  2.16 88.425 19.44 88.695 ;
     RECT  2.16 88.965 19.44 89.235 ;
     RECT  2.16 89.505 19.44 89.775 ;
     RECT  2.16 90.045 19.44 90.315 ;
     RECT  2.16 90.585 19.44 90.855 ;
     RECT  2.16 91.125 19.44 91.395 ;
     RECT  2.16 91.665 19.44 91.935 ;
     RECT  2.16 92.205 19.44 92.475 ;
     RECT  2.16 92.745 19.44 93.015 ;
     RECT  2.16 93.285 19.44 93.555 ;
     RECT  2.16 93.825 19.44 94.095 ;
     RECT  2.16 94.365 19.44 94.635 ;
     RECT  2.16 94.905 19.44 95.175 ;
     RECT  2.16 95.445 19.44 95.715 ;
     RECT  2.16 95.985 19.44 96.255 ;
     RECT  2.16 96.525 19.44 96.795 ;
     RECT  2.16 97.065 19.44 97.335 ;
     RECT  2.16 97.605 19.44 97.875 ;
     RECT  2.16 98.145 19.44 98.415 ;
     RECT  2.16 98.685 19.44 98.955 ;
     RECT  2.16 99.225 19.44 99.495 ;
     RECT  2.16 99.765 19.44 100.035 ;
     RECT  2.16 100.305 19.44 100.575 ;
     RECT  2.16 100.845 19.44 101.115 ;
     RECT  2.16 101.385 19.44 101.655 ;
     RECT  2.16 101.925 19.44 102.195 ;
     RECT  2.16 102.465 19.44 102.735 ;
     RECT  2.16 103.005 19.44 103.275 ;
     RECT  2.16 103.545 19.44 103.815 ;
     RECT  2.16 104.085 19.44 104.355 ;
     RECT  2.16 104.625 19.44 104.895 ;
     RECT  2.16 105.165 19.44 105.435 ;
     RECT  2.16 105.705 19.44 105.975 ;
     RECT  2.16 106.245 19.44 106.515 ;
     RECT  2.16 106.785 19.44 107.055 ;
     RECT  2.16 107.325 19.44 107.595 ;
     RECT  2.16 107.865 19.44 108.135 ;
     RECT  2.16 108.405 19.44 108.675 ;
     RECT  2.16 108.945 19.44 109.215 ;
     RECT  2.16 109.485 19.44 109.755 ;
     RECT  2.16 110.025 19.44 110.295 ;
     RECT  2.16 110.565 19.44 110.835 ;
     RECT  2.16 111.105 19.44 111.375 ;
     RECT  2.16 111.645 19.44 111.915 ;
     RECT  2.16 112.185 19.44 112.455 ;
     RECT  2.16 112.725 19.44 112.995 ;
     RECT  2.16 113.265 19.44 113.535 ;
     RECT  2.16 113.805 19.44 114.075 ;
     RECT  2.16 114.345 19.44 114.615 ;
     RECT  2.16 114.885 19.44 115.155 ;
     RECT  2.16 115.425 19.44 115.695 ;
     RECT  2.16 115.965 19.44 116.235 ;
     RECT  2.16 116.505 19.44 116.775 ;
     RECT  2.16 117.045 19.44 117.315 ;
     RECT  2.16 117.585 19.44 117.855 ;
     RECT  2.16 118.125 19.44 118.395 ;
     RECT  2.16 118.665 19.44 118.935 ;
     RECT  2.16 119.205 19.44 119.475 ;
     RECT  2.16 119.745 19.44 120.015 ;
     RECT  2.16 120.285 19.44 120.555 ;
     RECT  2.16 120.825 19.44 121.095 ;
     RECT  2.16 121.365 19.44 121.635 ;
     RECT  2.16 121.905 19.44 122.175 ;
     RECT  2.16 122.445 19.44 122.715 ;
     RECT  2.16 122.985 19.44 123.255 ;
     RECT  2.16 123.525 19.44 123.795 ;
     RECT  2.16 124.065 19.44 124.335 ;
     RECT  2.16 124.605 19.44 124.875 ;
     RECT  2.16 125.145 19.44 125.415 ;
     RECT  2.16 125.685 19.44 125.955 ;
     RECT  2.16 126.225 19.44 126.495 ;
     RECT  2.16 126.765 19.44 127.035 ;
     RECT  2.16 127.305 19.44 127.575 ;
     RECT  2.16 127.845 19.44 128.115 ;
     RECT  2.16 128.385 19.44 128.655 ;
     RECT  2.16 128.925 19.44 129.195 ;
     RECT  2.16 129.465 19.44 129.735 ;
     RECT  2.16 130.005 19.44 130.275 ;
     RECT  2.16 130.545 19.44 130.815 ;
     RECT  2.16 131.085 19.44 131.355 ;
     RECT  2.16 131.625 19.44 131.895 ;
     RECT  2.16 132.165 19.44 132.435 ;
     RECT  2.16 132.705 19.44 132.975 ;
     RECT  2.16 133.245 19.44 133.515 ;
     RECT  2.16 133.785 19.44 134.055 ;
     RECT  2.16 134.325 19.44 134.595 ;
     RECT  2.16 134.865 19.44 135.135 ;
     RECT  2.16 135.405 19.44 135.675 ;
     RECT  2.16 135.945 19.44 136.215 ;
     RECT  2.16 136.485 19.44 136.755 ;
     RECT  2.16 137.025 19.44 137.295 ;
     RECT  2.16 137.565 19.44 137.835 ;
     RECT  2.16 138.105 19.44 138.375 ;
     RECT  2.16 138.645 19.44 138.915 ;
     RECT  2.16 139.185 19.44 139.455 ;
     RECT  2.16 139.725 19.44 139.995 ;
     RECT  2.16 140.265 19.44 140.535 ;
     RECT  2.16 140.805 19.44 141.075 ;
     RECT  2.16 141.345 19.44 141.615 ;
     RECT  2.16 141.885 19.44 142.155 ;
     RECT  2.16 142.425 19.44 142.695 ;
     RECT  2.16 142.965 19.44 143.235 ;
     RECT  2.16 143.505 19.44 143.775 ;
     RECT  2.16 144.045 19.44 144.315 ;
     RECT  2.16 144.585 19.44 144.72 ;
    LAYER RVTP ;
     RECT  2.16 2.295 19.44 2.565 ;
     RECT  2.16 2.835 19.44 3.105 ;
     RECT  2.16 3.375 19.44 3.645 ;
     RECT  2.16 3.915 19.44 4.185 ;
     RECT  2.16 4.455 19.44 4.725 ;
     RECT  2.16 4.995 19.44 5.265 ;
     RECT  2.16 5.535 19.44 5.805 ;
     RECT  2.16 6.075 19.44 6.345 ;
     RECT  2.16 6.615 19.44 6.885 ;
     RECT  2.16 7.155 19.44 7.425 ;
     RECT  2.16 7.695 19.44 7.965 ;
     RECT  2.16 8.235 19.44 8.505 ;
     RECT  2.16 8.775 19.44 9.045 ;
     RECT  2.16 9.315 19.44 9.585 ;
     RECT  2.16 9.855 19.44 10.125 ;
     RECT  2.16 10.395 19.44 10.665 ;
     RECT  2.16 10.935 19.44 11.205 ;
     RECT  2.16 11.475 19.44 11.745 ;
     RECT  2.16 12.015 19.44 12.285 ;
     RECT  2.16 12.555 19.44 12.825 ;
     RECT  2.16 13.095 19.44 13.365 ;
     RECT  2.16 13.635 19.44 13.905 ;
     RECT  2.16 14.175 19.44 14.445 ;
     RECT  2.16 14.715 19.44 14.985 ;
     RECT  2.16 15.255 19.44 15.525 ;
     RECT  2.16 15.795 19.44 16.065 ;
     RECT  2.16 16.335 19.44 16.605 ;
     RECT  2.16 16.875 19.44 17.145 ;
     RECT  2.16 17.415 19.44 17.685 ;
     RECT  2.16 17.955 19.44 18.225 ;
     RECT  2.16 18.495 19.44 18.765 ;
     RECT  2.16 19.035 19.44 19.305 ;
     RECT  2.16 19.575 19.44 19.845 ;
     RECT  2.16 20.115 19.44 20.385 ;
     RECT  2.16 20.655 19.44 20.925 ;
     RECT  2.16 21.195 19.44 21.465 ;
     RECT  2.16 21.735 19.44 22.005 ;
     RECT  2.16 22.275 19.44 22.545 ;
     RECT  2.16 22.815 19.44 23.085 ;
     RECT  2.16 23.355 19.44 23.625 ;
     RECT  2.16 23.895 19.44 24.165 ;
     RECT  2.16 24.435 19.44 24.705 ;
     RECT  2.16 24.975 19.44 25.245 ;
     RECT  2.16 25.515 19.44 25.785 ;
     RECT  2.16 26.055 19.44 26.325 ;
     RECT  2.16 26.595 19.44 26.865 ;
     RECT  2.16 27.135 19.44 27.405 ;
     RECT  2.16 27.675 19.44 27.945 ;
     RECT  2.16 28.215 19.44 28.485 ;
     RECT  2.16 28.755 19.44 29.025 ;
     RECT  2.16 29.295 19.44 29.565 ;
     RECT  2.16 29.835 19.44 30.105 ;
     RECT  2.16 30.375 19.44 30.645 ;
     RECT  2.16 30.915 19.44 31.185 ;
     RECT  2.16 31.455 19.44 31.725 ;
     RECT  2.16 31.995 19.44 32.265 ;
     RECT  2.16 32.535 19.44 32.805 ;
     RECT  2.16 33.075 19.44 33.345 ;
     RECT  2.16 33.615 19.44 33.885 ;
     RECT  2.16 34.155 19.44 34.425 ;
     RECT  2.16 34.695 19.44 34.965 ;
     RECT  2.16 35.235 19.44 35.505 ;
     RECT  2.16 35.775 19.44 36.045 ;
     RECT  2.16 36.315 19.44 36.585 ;
     RECT  2.16 36.855 19.44 37.125 ;
     RECT  2.16 37.395 19.44 37.665 ;
     RECT  2.16 37.935 19.44 38.205 ;
     RECT  2.16 38.475 19.44 38.745 ;
     RECT  2.16 39.015 19.44 39.285 ;
     RECT  2.16 39.555 19.44 39.825 ;
     RECT  2.16 40.095 19.44 40.365 ;
     RECT  2.16 40.635 19.44 40.905 ;
     RECT  2.16 41.175 19.44 41.445 ;
     RECT  2.16 41.715 19.44 41.985 ;
     RECT  2.16 42.255 19.44 42.525 ;
     RECT  2.16 42.795 19.44 43.065 ;
     RECT  2.16 43.335 19.44 43.605 ;
     RECT  2.16 43.875 19.44 44.145 ;
     RECT  2.16 44.415 19.44 44.685 ;
     RECT  2.16 44.955 19.44 45.225 ;
     RECT  2.16 45.495 19.44 45.765 ;
     RECT  2.16 46.035 19.44 46.305 ;
     RECT  2.16 46.575 19.44 46.845 ;
     RECT  2.16 47.115 19.44 47.385 ;
     RECT  2.16 47.655 19.44 47.925 ;
     RECT  2.16 48.195 19.44 48.465 ;
     RECT  2.16 48.735 19.44 49.005 ;
     RECT  2.16 49.275 19.44 49.545 ;
     RECT  2.16 49.815 19.44 50.085 ;
     RECT  2.16 50.355 19.44 50.625 ;
     RECT  2.16 50.895 19.44 51.165 ;
     RECT  2.16 51.435 19.44 51.705 ;
     RECT  2.16 51.975 19.44 52.245 ;
     RECT  2.16 52.515 19.44 52.785 ;
     RECT  2.16 53.055 19.44 53.325 ;
     RECT  2.16 53.595 19.44 53.865 ;
     RECT  2.16 54.135 19.44 54.405 ;
     RECT  2.16 54.675 19.44 54.945 ;
     RECT  2.16 55.215 19.44 55.485 ;
     RECT  2.16 55.755 19.44 56.025 ;
     RECT  2.16 56.295 19.44 56.565 ;
     RECT  2.16 56.835 19.44 57.105 ;
     RECT  2.16 57.375 19.44 57.645 ;
     RECT  2.16 57.915 19.44 58.185 ;
     RECT  2.16 58.455 19.44 58.725 ;
     RECT  2.16 58.995 19.44 59.265 ;
     RECT  2.16 59.535 19.44 59.805 ;
     RECT  2.16 60.075 19.44 60.345 ;
     RECT  2.16 60.615 19.44 60.885 ;
     RECT  2.16 61.155 19.44 61.425 ;
     RECT  2.16 61.695 19.44 61.965 ;
     RECT  2.16 62.235 19.44 62.505 ;
     RECT  2.16 62.775 19.44 63.045 ;
     RECT  2.16 63.315 19.44 63.585 ;
     RECT  2.16 63.855 19.44 64.125 ;
     RECT  2.16 64.395 19.44 64.665 ;
     RECT  2.16 64.935 19.44 65.205 ;
     RECT  2.16 65.475 19.44 65.745 ;
     RECT  2.16 66.015 19.44 66.285 ;
     RECT  2.16 66.555 19.44 66.825 ;
     RECT  2.16 67.095 19.44 67.365 ;
     RECT  2.16 67.635 19.44 67.905 ;
     RECT  2.16 68.175 19.44 68.445 ;
     RECT  2.16 68.715 19.44 68.985 ;
     RECT  2.16 69.255 19.44 69.525 ;
     RECT  2.16 69.795 19.44 70.065 ;
     RECT  2.16 70.335 19.44 70.605 ;
     RECT  2.16 70.875 19.44 71.145 ;
     RECT  2.16 71.415 19.44 71.685 ;
     RECT  2.16 71.955 19.44 72.225 ;
     RECT  2.16 72.495 19.44 72.765 ;
     RECT  2.16 73.035 19.44 73.305 ;
     RECT  2.16 73.575 19.44 73.845 ;
     RECT  2.16 74.115 19.44 74.385 ;
     RECT  2.16 74.655 19.44 74.925 ;
     RECT  2.16 75.195 19.44 75.465 ;
     RECT  2.16 75.735 19.44 76.005 ;
     RECT  2.16 76.275 19.44 76.545 ;
     RECT  2.16 76.815 19.44 77.085 ;
     RECT  2.16 77.355 19.44 77.625 ;
     RECT  2.16 77.895 19.44 78.165 ;
     RECT  2.16 78.435 19.44 78.705 ;
     RECT  2.16 78.975 19.44 79.245 ;
     RECT  2.16 79.515 19.44 79.785 ;
     RECT  2.16 80.055 19.44 80.325 ;
     RECT  2.16 80.595 19.44 80.865 ;
     RECT  2.16 81.135 19.44 81.405 ;
     RECT  2.16 81.675 19.44 81.945 ;
     RECT  2.16 82.215 19.44 82.485 ;
     RECT  2.16 82.755 19.44 83.025 ;
     RECT  2.16 83.295 19.44 83.565 ;
     RECT  2.16 83.835 19.44 84.105 ;
     RECT  2.16 84.375 19.44 84.645 ;
     RECT  2.16 84.915 19.44 85.185 ;
     RECT  2.16 85.455 19.44 85.725 ;
     RECT  2.16 85.995 19.44 86.265 ;
     RECT  2.16 86.535 19.44 86.805 ;
     RECT  2.16 87.075 19.44 87.345 ;
     RECT  2.16 87.615 19.44 87.885 ;
     RECT  2.16 88.155 19.44 88.425 ;
     RECT  2.16 88.695 19.44 88.965 ;
     RECT  2.16 89.235 19.44 89.505 ;
     RECT  2.16 89.775 19.44 90.045 ;
     RECT  2.16 90.315 19.44 90.585 ;
     RECT  2.16 90.855 19.44 91.125 ;
     RECT  2.16 91.395 19.44 91.665 ;
     RECT  2.16 91.935 19.44 92.205 ;
     RECT  2.16 92.475 19.44 92.745 ;
     RECT  2.16 93.015 19.44 93.285 ;
     RECT  2.16 93.555 19.44 93.825 ;
     RECT  2.16 94.095 19.44 94.365 ;
     RECT  2.16 94.635 19.44 94.905 ;
     RECT  2.16 95.175 19.44 95.445 ;
     RECT  2.16 95.715 19.44 95.985 ;
     RECT  2.16 96.255 19.44 96.525 ;
     RECT  2.16 96.795 19.44 97.065 ;
     RECT  2.16 97.335 19.44 97.605 ;
     RECT  2.16 97.875 19.44 98.145 ;
     RECT  2.16 98.415 19.44 98.685 ;
     RECT  2.16 98.955 19.44 99.225 ;
     RECT  2.16 99.495 19.44 99.765 ;
     RECT  2.16 100.035 19.44 100.305 ;
     RECT  2.16 100.575 19.44 100.845 ;
     RECT  2.16 101.115 19.44 101.385 ;
     RECT  2.16 101.655 19.44 101.925 ;
     RECT  2.16 102.195 19.44 102.465 ;
     RECT  2.16 102.735 19.44 103.005 ;
     RECT  2.16 103.275 19.44 103.545 ;
     RECT  2.16 103.815 19.44 104.085 ;
     RECT  2.16 104.355 19.44 104.625 ;
     RECT  2.16 104.895 19.44 105.165 ;
     RECT  2.16 105.435 19.44 105.705 ;
     RECT  2.16 105.975 19.44 106.245 ;
     RECT  2.16 106.515 19.44 106.785 ;
     RECT  2.16 107.055 19.44 107.325 ;
     RECT  2.16 107.595 19.44 107.865 ;
     RECT  2.16 108.135 19.44 108.405 ;
     RECT  2.16 108.675 19.44 108.945 ;
     RECT  2.16 109.215 19.44 109.485 ;
     RECT  2.16 109.755 19.44 110.025 ;
     RECT  2.16 110.295 19.44 110.565 ;
     RECT  2.16 110.835 19.44 111.105 ;
     RECT  2.16 111.375 19.44 111.645 ;
     RECT  2.16 111.915 19.44 112.185 ;
     RECT  2.16 112.455 19.44 112.725 ;
     RECT  2.16 112.995 19.44 113.265 ;
     RECT  2.16 113.535 19.44 113.805 ;
     RECT  2.16 114.075 19.44 114.345 ;
     RECT  2.16 114.615 19.44 114.885 ;
     RECT  2.16 115.155 19.44 115.425 ;
     RECT  2.16 115.695 19.44 115.965 ;
     RECT  2.16 116.235 19.44 116.505 ;
     RECT  2.16 116.775 19.44 117.045 ;
     RECT  2.16 117.315 19.44 117.585 ;
     RECT  2.16 117.855 19.44 118.125 ;
     RECT  2.16 118.395 19.44 118.665 ;
     RECT  2.16 118.935 19.44 119.205 ;
     RECT  2.16 119.475 19.44 119.745 ;
     RECT  2.16 120.015 19.44 120.285 ;
     RECT  2.16 120.555 19.44 120.825 ;
     RECT  2.16 121.095 19.44 121.365 ;
     RECT  2.16 121.635 19.44 121.905 ;
     RECT  2.16 122.175 19.44 122.445 ;
     RECT  2.16 122.715 19.44 122.985 ;
     RECT  2.16 123.255 19.44 123.525 ;
     RECT  2.16 123.795 19.44 124.065 ;
     RECT  2.16 124.335 19.44 124.605 ;
     RECT  2.16 124.875 19.44 125.145 ;
     RECT  2.16 125.415 19.44 125.685 ;
     RECT  2.16 125.955 19.44 126.225 ;
     RECT  2.16 126.495 19.44 126.765 ;
     RECT  2.16 127.035 19.44 127.305 ;
     RECT  2.16 127.575 19.44 127.845 ;
     RECT  2.16 128.115 19.44 128.385 ;
     RECT  2.16 128.655 19.44 128.925 ;
     RECT  2.16 129.195 19.44 129.465 ;
     RECT  2.16 129.735 19.44 130.005 ;
     RECT  2.16 130.275 19.44 130.545 ;
     RECT  2.16 130.815 19.44 131.085 ;
     RECT  2.16 131.355 19.44 131.625 ;
     RECT  2.16 131.895 19.44 132.165 ;
     RECT  2.16 132.435 19.44 132.705 ;
     RECT  2.16 132.975 19.44 133.245 ;
     RECT  2.16 133.515 19.44 133.785 ;
     RECT  2.16 134.055 19.44 134.325 ;
     RECT  2.16 134.595 19.44 134.865 ;
     RECT  2.16 135.135 19.44 135.405 ;
     RECT  2.16 135.675 19.44 135.945 ;
     RECT  2.16 136.215 19.44 136.485 ;
     RECT  2.16 136.755 19.44 137.025 ;
     RECT  2.16 137.295 19.44 137.565 ;
     RECT  2.16 137.835 19.44 138.105 ;
     RECT  2.16 138.375 19.44 138.645 ;
     RECT  2.16 138.915 19.44 139.185 ;
     RECT  2.16 139.455 19.44 139.725 ;
     RECT  2.16 139.995 19.44 140.265 ;
     RECT  2.16 140.535 19.44 140.805 ;
     RECT  2.16 141.075 19.44 141.345 ;
     RECT  2.16 141.615 19.44 141.885 ;
     RECT  2.16 142.155 19.44 142.425 ;
     RECT  2.16 142.695 19.44 142.965 ;
     RECT  2.16 143.235 19.44 143.505 ;
     RECT  2.16 143.775 19.44 144.045 ;
     RECT  2.16 144.315 19.44 144.585 ;
    LAYER M1 ;
     RECT  2.16 2.151 19.44 144.729 ;
    LAYER M2 ;
     RECT  0.103 4.122 2.16 4.14 ;
     RECT  0.103 11.142 2.16 11.16 ;
     RECT  0.103 23.562 2.16 23.58 ;
     RECT  0.103 25.992 2.16 26.01 ;
     RECT  0.535 27.342 2.16 27.36 ;
     RECT  0.103 33.552 2.16 33.57 ;
     RECT  0.103 45.432 2.16 45.45 ;
     RECT  0.103 57.852 2.16 57.87 ;
     RECT  0.535 59.202 2.16 59.22 ;
     RECT  0.103 64.062 2.16 64.08 ;
     RECT  0.103 69.462 2.16 69.48 ;
     RECT  0.103 78.642 2.16 78.66 ;
     RECT  0.535 84.852 2.16 84.87 ;
     RECT  0.103 88.902 2.16 88.92 ;
     RECT  0.103 100.512 2.16 100.53 ;
     RECT  0.103 101.322 2.16 101.34 ;
     RECT  0.103 107.532 2.16 107.55 ;
     RECT  0.103 119.952 2.16 119.97 ;
     RECT  0.103 122.382 2.16 122.4 ;
     RECT  0.535 129.942 2.16 129.96 ;
     RECT  0.103 134.802 2.16 134.82 ;
     RECT  0.535 136.188 2.16 136.206 ;
     RECT  0.103 141.822 2.16 141.84 ;
     RECT  2.16 2.151 19.44 144.729 ;
     RECT  19.44 6.516 19.931 7.074 ;
     RECT  19.44 140.976 19.931 140.994 ;
     RECT  19.44 15.696 19.967 15.714 ;
     RECT  19.44 16.506 19.967 16.524 ;
     RECT  19.44 17.316 19.967 17.334 ;
     RECT  19.44 18.936 19.967 19.494 ;
     RECT  19.44 21.096 19.967 21.114 ;
     RECT  19.44 21.906 19.967 21.924 ;
     RECT  19.44 22.716 19.967 22.734 ;
     RECT  19.44 25.956 19.967 26.514 ;
     RECT  19.44 28.926 19.967 28.944 ;
     RECT  19.44 32.706 19.967 32.724 ;
     RECT  19.44 34.326 19.967 34.344 ;
     RECT  19.44 80.226 19.967 80.244 ;
     RECT  19.44 81.036 19.967 81.054 ;
     RECT  19.44 86.436 19.967 86.454 ;
     RECT  19.44 91.836 19.967 91.854 ;
     RECT  19.44 92.646 19.967 92.664 ;
     RECT  19.44 94.266 19.967 94.284 ;
     RECT  19.44 98.316 19.967 98.874 ;
     RECT  19.44 99.666 19.967 99.684 ;
     RECT  19.44 104.526 19.967 105.084 ;
     RECT  19.44 105.876 19.967 105.894 ;
     RECT  19.44 106.686 19.967 106.704 ;
     RECT  19.44 123.696 19.967 123.714 ;
     RECT  19.44 126.126 19.967 126.144 ;
     RECT  19.44 137.196 19.967 137.754 ;
     RECT  19.44 143.136 19.967 143.154 ;
     RECT  19.44 4.932 20.507 4.95 ;
     RECT  19.44 11.106 20.507 11.124 ;
     RECT  19.44 11.916 20.507 11.934 ;
     RECT  19.44 12.762 20.507 12.78 ;
     RECT  19.44 18.126 20.507 18.144 ;
     RECT  19.44 23.526 20.507 23.544 ;
     RECT  19.44 24.336 20.507 24.354 ;
     RECT  19.44 25.146 20.507 25.164 ;
     RECT  19.44 30.546 20.507 30.564 ;
     RECT  19.44 81.846 20.507 81.864 ;
     RECT  19.44 88.056 20.507 88.074 ;
     RECT  19.44 89.676 20.507 89.694 ;
     RECT  19.44 90.486 20.507 91.044 ;
     RECT  19.44 95.076 20.507 95.094 ;
     RECT  19.44 95.886 20.507 96.444 ;
     RECT  19.967 98.316 20.507 98.334 ;
     RECT  19.44 102.906 20.507 102.924 ;
     RECT  19.967 104.526 20.507 104.544 ;
     RECT  19.44 115.326 20.507 115.344 ;
     RECT  19.44 116.136 20.507 116.154 ;
     RECT  19.44 121.536 20.507 121.554 ;
     RECT  19.44 122.346 20.507 122.904 ;
     RECT  19.44 134.766 20.507 134.784 ;
     RECT  19.44 135.576 20.507 135.594 ;
     RECT  19.44 2.466 20.543 2.484 ;
     RECT  19.44 3.276 20.543 3.294 ;
     RECT  19.931 7.056 20.543 7.074 ;
     RECT  19.44 8.136 20.543 8.694 ;
     RECT  19.44 9.486 20.543 9.504 ;
     RECT  19.44 10.296 20.543 10.314 ;
     RECT  19.44 14.886 20.543 14.904 ;
     RECT  19.44 20.286 20.543 20.304 ;
     RECT  19.44 27.306 20.543 27.324 ;
     RECT  19.44 28.116 20.543 28.134 ;
     RECT  19.44 29.736 20.543 29.754 ;
     RECT  19.44 35.136 20.543 35.154 ;
     RECT  19.44 35.946 20.543 35.964 ;
     RECT  19.44 39.186 20.543 39.744 ;
     RECT  19.44 40.536 20.543 40.554 ;
     RECT  19.44 41.346 20.543 41.364 ;
     RECT  19.44 46.746 20.543 46.764 ;
     RECT  19.44 47.556 20.543 47.574 ;
     RECT  19.44 48.366 20.543 48.384 ;
     RECT  19.44 49.176 20.543 49.194 ;
     RECT  19.44 51.606 20.543 52.164 ;
     RECT  19.44 54.036 20.543 54.594 ;
     RECT  19.44 55.386 20.543 55.404 ;
     RECT  19.44 60.012 20.543 60.03 ;
     RECT  19.44 60.786 20.543 60.804 ;
     RECT  19.44 61.596 20.543 61.614 ;
     RECT  19.44 66.186 20.543 66.204 ;
     RECT  19.44 66.996 20.543 67.014 ;
     RECT  19.44 71.046 20.543 71.604 ;
     RECT  19.44 72.396 20.543 72.414 ;
     RECT  19.44 73.206 20.543 73.224 ;
     RECT  19.44 74.016 20.543 74.034 ;
     RECT  19.44 74.826 20.543 74.844 ;
     RECT  19.44 77.256 20.543 77.814 ;
     RECT  19.44 79.416 20.543 79.434 ;
     RECT  19.44 83.466 20.543 84.024 ;
     RECT  19.44 85.626 20.543 85.644 ;
     RECT  19.44 87.246 20.543 87.264 ;
     RECT  20.507 91.026 20.543 91.044 ;
     RECT  20.507 96.426 20.543 96.444 ;
     RECT  19.44 97.236 20.543 97.254 ;
     RECT  19.44 110.772 20.543 111.294 ;
     RECT  19.44 112.086 20.543 112.104 ;
     RECT  19.44 112.896 20.543 112.914 ;
     RECT  19.44 113.706 20.543 113.724 ;
     RECT  19.44 117.486 20.543 117.504 ;
     RECT  19.44 118.332 20.543 118.35 ;
     RECT  20.507 122.886 20.543 122.904 ;
     RECT  19.44 124.506 20.543 124.524 ;
     RECT  19.44 125.316 20.543 125.334 ;
     RECT  19.44 130.716 20.543 130.734 ;
     RECT  19.44 131.526 20.543 131.544 ;
     RECT  19.44 132.336 20.543 132.354 ;
     RECT  19.44 133.146 20.543 133.164 ;
     RECT  19.44 138.546 20.543 138.564 ;
     RECT  20.543 8.136 21.515 8.154 ;
     RECT  19.44 13.536 21.515 13.554 ;
     RECT  19.967 18.936 21.515 18.954 ;
     RECT  19.967 25.956 21.515 25.974 ;
     RECT  19.44 36.756 21.515 36.774 ;
     RECT  19.44 37.566 21.515 37.584 ;
     RECT  19.44 38.376 21.515 38.394 ;
     RECT  20.543 39.186 21.515 39.204 ;
     RECT  19.44 42.966 21.515 42.984 ;
     RECT  19.44 43.776 21.515 43.794 ;
     RECT  19.44 44.586 21.515 44.604 ;
     RECT  19.44 45.396 21.515 45.414 ;
     RECT  19.44 49.986 21.515 50.004 ;
     RECT  19.44 50.796 21.515 50.814 ;
     RECT  20.543 51.606 21.515 51.624 ;
     RECT  19.44 53.262 21.515 53.28 ;
     RECT  20.543 54.036 21.515 54.054 ;
     RECT  19.44 56.232 21.515 56.25 ;
     RECT  19.44 58.626 21.515 58.644 ;
     RECT  19.44 62.406 21.515 62.424 ;
     RECT  19.44 63.216 21.515 63.234 ;
     RECT  19.44 64.026 21.515 64.044 ;
     RECT  19.44 64.836 21.515 64.854 ;
     RECT  19.44 68.616 21.515 68.634 ;
     RECT  19.44 69.426 21.515 69.444 ;
     RECT  19.44 70.236 21.515 70.254 ;
     RECT  20.543 71.046 21.515 71.064 ;
     RECT  19.44 75.636 21.515 75.654 ;
     RECT  19.44 76.446 21.515 76.464 ;
     RECT  20.543 77.256 21.515 77.274 ;
     RECT  20.543 83.466 21.515 83.484 ;
     RECT  19.44 88.866 21.515 88.884 ;
     RECT  19.44 100.476 21.515 100.494 ;
     RECT  19.44 101.286 21.515 101.304 ;
     RECT  19.44 102.096 21.515 102.114 ;
     RECT  19.44 103.716 21.515 103.734 ;
     RECT  19.44 107.496 21.515 107.514 ;
     RECT  19.44 109.152 21.515 109.17 ;
     RECT  19.44 109.926 21.515 109.944 ;
     RECT  20.543 110.772 21.515 110.79 ;
     RECT  19.44 114.516 21.515 114.534 ;
     RECT  19.44 119.952 21.515 119.97 ;
     RECT  19.44 120.726 21.515 120.744 ;
     RECT  19.44 126.936 21.515 126.954 ;
     RECT  19.44 127.782 21.515 127.8 ;
     RECT  19.44 128.556 21.515 128.574 ;
     RECT  19.44 129.366 21.515 129.384 ;
     RECT  19.967 137.196 21.515 137.214 ;
     RECT  19.44 139.392 21.515 139.41 ;
    LAYER M3 ;
     RECT  2.415 2.143 2.505 2.413 ;
     RECT  5.115 2.143 5.205 2.413 ;
     RECT  7.815 2.143 7.905 2.413 ;
     RECT  10.515 2.143 10.605 2.413 ;
     RECT  13.215 2.143 13.305 2.413 ;
     RECT  15.915 2.143 16.005 2.413 ;
     RECT  18.615 2.143 18.705 2.413 ;
     RECT  2.415 2.413 2.697 2.641 ;
     RECT  2.415 2.641 3.258 2.717 ;
     RECT  5.115 2.413 5.397 3.259 ;
     RECT  4.536 3.259 5.397 3.299 ;
     RECT  12.168 3.181 12.186 3.299 ;
     RECT  20.52 2.461 20.538 3.341 ;
     RECT  18.615 2.413 18.897 4.081 ;
     RECT  0.108 4.075 0.126 4.145 ;
     RECT  18.216 4.081 18.897 4.205 ;
     RECT  21.492 4.075 21.51 4.205 ;
     RECT  2.415 2.717 2.697 4.801 ;
     RECT  2.304 4.801 2.697 4.877 ;
     RECT  3.996 4.795 4.014 4.955 ;
     RECT  20.484 4.843 20.502 4.955 ;
     RECT  7.056 4.225 7.074 5.069 ;
     RECT  12.204 4.927 12.222 5.099 ;
     RECT  2.415 4.877 2.697 5.659 ;
     RECT  21.492 5.563 21.51 5.693 ;
     RECT  2.412 5.659 2.697 5.701 ;
     RECT  11.952 5.563 11.97 5.729 ;
     RECT  2.412 5.701 3.258 5.741 ;
     RECT  2.412 5.741 2.697 6.427 ;
     RECT  5.115 3.299 5.397 6.475 ;
     RECT  4.536 6.475 5.397 6.539 ;
     RECT  19.908 6.427 19.926 6.539 ;
     RECT  2.304 6.427 2.697 6.575 ;
     RECT  4.284 7.189 4.302 7.229 ;
     RECT  20.52 7.051 20.538 7.229 ;
     RECT  6.3 7.195 6.318 7.421 ;
     RECT  21.492 7.963 21.51 8.159 ;
     RECT  7.056 8.275 7.074 8.333 ;
     RECT  4.032 7.963 4.05 8.635 ;
     RECT  4.032 8.635 4.338 8.671 ;
     RECT  3.996 8.671 4.338 8.699 ;
     RECT  3.996 8.699 4.014 9.121 ;
     RECT  3.456 9.121 4.014 9.149 ;
     RECT  3.456 9.149 3.474 9.533 ;
     RECT  2.415 6.575 2.697 9.544 ;
     RECT  2.304 9.544 2.697 9.581 ;
     RECT  2.415 9.581 2.697 10.315 ;
     RECT  5.115 6.539 5.397 10.315 ;
     RECT  20.52 8.671 20.538 10.349 ;
     RECT  2.304 10.315 2.697 10.355 ;
     RECT  5.115 10.315 5.778 10.355 ;
     RECT  20.484 11.083 20.502 11.129 ;
     RECT  6.84 11.101 6.858 11.131 ;
     RECT  0.108 11.083 0.126 11.165 ;
     RECT  6.84 11.131 7.074 11.171 ;
     RECT  6.84 11.171 6.858 11.273 ;
     RECT  2.415 10.355 2.697 11.851 ;
     RECT  2.304 11.851 2.697 11.941 ;
     RECT  2.304 11.941 3.222 11.981 ;
     RECT  20.484 11.851 20.502 12.785 ;
     RECT  5.115 10.355 5.397 12.865 ;
     RECT  4.5 12.865 5.397 12.941 ;
     RECT  21.492 13.435 21.51 13.559 ;
     RECT  2.304 11.981 2.697 13.595 ;
     RECT  6.84 13.627 6.858 13.703 ;
     RECT  10.515 2.413 10.797 14.203 ;
     RECT  10.515 14.203 11.394 14.369 ;
     RECT  3.996 14.203 4.014 14.405 ;
     RECT  7.056 14.347 7.074 14.405 ;
     RECT  2.415 13.595 2.697 14.971 ;
     RECT  20.52 14.881 20.538 15.005 ;
     RECT  2.304 14.971 2.697 15.025 ;
     RECT  2.304 15.025 3.186 15.053 ;
     RECT  2.415 15.053 3.186 15.355 ;
     RECT  2.415 15.355 3.474 15.773 ;
     RECT  19.944 15.691 19.962 15.773 ;
     RECT  3.456 15.773 3.474 15.917 ;
     RECT  5.115 12.941 5.397 16.411 ;
     RECT  5.115 16.411 5.634 16.529 ;
     RECT  19.944 16.501 19.962 16.541 ;
     RECT  5.115 16.529 5.397 16.645 ;
     RECT  4.68 16.645 5.397 16.685 ;
     RECT  2.415 15.773 2.697 17.311 ;
     RECT  5.115 16.685 5.397 17.323 ;
     RECT  2.304 17.311 2.697 17.357 ;
     RECT  19.944 17.311 19.962 17.357 ;
     RECT  3.996 17.323 4.014 17.375 ;
     RECT  5.115 17.323 5.994 17.375 ;
     RECT  2.415 17.357 2.697 18.091 ;
     RECT  2.304 18.091 2.697 18.121 ;
     RECT  20.484 18.091 20.502 18.149 ;
     RECT  2.304 18.121 3.258 18.173 ;
     RECT  5.115 17.375 5.397 18.811 ;
     RECT  21.492 18.859 21.51 18.959 ;
     RECT  2.304 18.173 2.697 18.995 ;
     RECT  4.536 18.811 5.397 19.499 ;
     RECT  2.415 18.995 2.697 19.615 ;
     RECT  2.415 19.615 2.826 19.661 ;
     RECT  19.944 19.471 19.962 19.661 ;
     RECT  7.815 2.413 8.097 19.819 ;
     RECT  6.408 19.615 6.426 19.915 ;
     RECT  7.596 19.819 8.097 19.915 ;
     RECT  4.032 19.651 4.05 19.949 ;
     RECT  6.3 19.915 8.097 19.955 ;
     RECT  6.3 19.955 6.606 20.039 ;
     RECT  6.3 20.039 6.318 20.237 ;
     RECT  20.52 20.281 20.538 20.429 ;
     RECT  3.996 20.395 4.014 20.453 ;
     RECT  7.596 19.955 8.097 20.477 ;
     RECT  2.415 19.661 2.697 21.211 ;
     RECT  2.304 21.211 2.697 21.263 ;
     RECT  5.115 19.499 5.397 21.271 ;
     RECT  4.428 21.271 5.397 21.355 ;
     RECT  7.056 21.115 7.074 21.389 ;
     RECT  4.32 21.355 5.397 21.451 ;
     RECT  6.66 21.451 6.678 21.497 ;
     RECT  4.032 21.451 5.397 21.569 ;
     RECT  4.32 21.569 5.397 22.222 ;
     RECT  5.115 22.222 5.397 22.741 ;
     RECT  5.115 22.741 5.778 22.781 ;
     RECT  19.944 21.091 19.962 22.781 ;
     RECT  4.068 22.747 4.086 22.784 ;
     RECT  20.484 23.512 20.502 23.549 ;
     RECT  0.108 23.515 0.126 23.585 ;
     RECT  5.115 22.781 5.397 23.665 ;
     RECT  5.115 23.665 5.994 23.741 ;
     RECT  2.415 21.263 2.697 24.283 ;
     RECT  20.484 24.283 20.502 24.359 ;
     RECT  4.284 24.379 4.302 24.509 ;
     RECT  20.484 25.099 20.502 25.169 ;
     RECT  2.304 24.283 2.697 25.205 ;
     RECT  5.115 23.741 5.397 25.321 ;
     RECT  5.115 25.321 5.634 25.373 ;
     RECT  21.492 25.867 21.51 25.979 ;
     RECT  0.108 25.867 0.126 26.015 ;
     RECT  6.84 25.963 6.858 26.015 ;
     RECT  6.552 26.203 6.57 26.555 ;
     RECT  5.115 25.373 5.397 26.629 ;
     RECT  19.944 26.491 19.962 26.669 ;
     RECT  4.536 26.629 5.397 27.259 ;
     RECT  4.428 27.259 5.397 27.301 ;
     RECT  4.356 27.301 5.397 27.329 ;
     RECT  0.54 27.337 0.558 27.437 ;
     RECT  4.356 27.329 4.374 27.509 ;
     RECT  3.456 28.075 3.474 28.139 ;
     RECT  2.415 25.205 2.697 28.171 ;
     RECT  20.52 27.301 20.538 28.205 ;
     RECT  2.304 28.171 2.697 28.211 ;
     RECT  2.415 28.211 2.697 28.939 ;
     RECT  19.944 28.921 19.962 28.973 ;
     RECT  2.304 28.939 2.697 28.985 ;
     RECT  6.84 29.035 6.858 29.093 ;
     RECT  7.815 20.477 8.097 29.755 ;
     RECT  20.52 29.731 20.538 29.789 ;
     RECT  7.815 29.755 8.154 29.795 ;
     RECT  2.415 28.985 2.697 30.523 ;
     RECT  4.32 30.523 4.338 30.569 ;
     RECT  20.484 30.523 20.502 30.569 ;
     RECT  3.456 31.339 3.474 31.379 ;
     RECT  11.844 31.147 11.862 31.379 ;
     RECT  2.304 30.523 2.697 31.415 ;
     RECT  10.515 14.369 10.797 31.891 ;
     RECT  6.228 31.801 6.246 31.919 ;
     RECT  9.252 31.801 9.27 31.919 ;
     RECT  10.515 31.891 11.322 31.997 ;
     RECT  5.115 27.329 5.397 32.035 ;
     RECT  4.464 32.035 5.397 32.093 ;
     RECT  14.724 31.147 14.85 32.093 ;
     RECT  21.492 31.147 21.51 32.093 ;
     RECT  7.815 29.795 8.097 32.737 ;
     RECT  7.596 32.737 8.097 32.813 ;
     RECT  19.944 32.701 19.962 32.861 ;
     RECT  3.996 32.827 4.014 32.873 ;
     RECT  4.248 33.499 4.266 33.575 ;
     RECT  10.515 31.997 10.797 33.583 ;
     RECT  0.108 33.547 0.126 33.677 ;
     RECT  10.515 33.583 10.998 33.677 ;
     RECT  5.115 32.093 5.397 34.315 ;
     RECT  2.415 31.415 2.697 34.321 ;
     RECT  19.944 34.321 19.962 34.445 ;
     RECT  2.415 34.321 2.862 34.493 ;
     RECT  4.68 34.315 5.397 35.167 ;
     RECT  4.176 35.167 5.397 35.213 ;
     RECT  20.52 35.131 20.538 35.213 ;
     RECT  4.68 35.213 5.397 35.309 ;
     RECT  7.815 32.813 8.097 35.977 ;
     RECT  20.52 35.941 20.538 35.981 ;
     RECT  7.815 35.977 8.154 36.029 ;
     RECT  6.84 35.941 6.858 36.113 ;
     RECT  2.415 34.493 2.697 36.715 ;
     RECT  21.492 36.715 21.51 36.779 ;
     RECT  4.32 36.475 4.338 36.931 ;
     RECT  3.996 36.931 4.338 36.959 ;
     RECT  3.996 36.959 4.014 37.057 ;
     RECT  3.456 37.057 4.014 37.085 ;
     RECT  3.456 37.085 3.474 37.589 ;
     RECT  2.304 36.715 2.697 38.435 ;
     RECT  6.876 38.395 6.894 38.435 ;
     RECT  5.115 35.309 5.397 38.551 ;
     RECT  6.84 38.551 6.858 38.669 ;
     RECT  4.824 38.551 5.454 38.677 ;
     RECT  4.68 38.677 5.454 38.765 ;
     RECT  21.492 37.531 21.51 39.209 ;
     RECT  5.115 38.765 5.454 39.217 ;
     RECT  3.996 39.067 4.014 39.245 ;
     RECT  5.115 39.217 5.994 39.293 ;
     RECT  2.415 38.435 2.697 39.721 ;
     RECT  2.415 39.721 2.862 39.865 ;
     RECT  2.415 39.865 3.33 39.917 ;
     RECT  4.032 40.567 4.05 40.637 ;
     RECT  5.115 39.293 5.397 40.711 ;
     RECT  2.415 39.917 2.697 41.413 ;
     RECT  2.415 41.413 2.826 41.453 ;
     RECT  20.52 39.721 20.538 41.453 ;
     RECT  5.115 40.711 5.634 41.485 ;
     RECT  5.115 41.485 5.778 41.549 ;
     RECT  10.515 33.677 10.797 42.151 ;
     RECT  10.515 42.151 11.394 42.221 ;
     RECT  7.056 42.295 7.074 42.365 ;
     RECT  2.415 41.453 2.697 42.955 ;
     RECT  21.492 42.952 21.51 42.989 ;
     RECT  2.304 42.955 2.697 43.069 ;
     RECT  2.304 43.069 3.186 43.141 ;
     RECT  2.304 43.141 3.258 43.181 ;
     RECT  5.115 41.549 5.397 43.843 ;
     RECT  5.115 43.843 5.598 43.901 ;
     RECT  2.304 43.181 2.697 44.645 ;
     RECT  5.115 43.901 5.397 44.725 ;
     RECT  4.68 44.725 5.397 44.765 ;
     RECT  21.492 43.723 21.51 45.419 ;
     RECT  0.108 45.307 0.126 45.455 ;
     RECT  7.815 36.029 8.097 45.535 ;
     RECT  7.815 45.535 8.154 45.581 ;
     RECT  11.772 46.075 11.79 46.229 ;
     RECT  2.415 44.645 2.697 46.309 ;
     RECT  2.415 46.309 3.186 46.381 ;
     RECT  2.415 46.381 3.258 46.445 ;
     RECT  2.415 46.445 2.697 46.843 ;
     RECT  2.304 46.843 2.697 46.913 ;
     RECT  3.996 46.921 4.014 46.973 ;
     RECT  4.176 47.563 4.194 47.615 ;
     RECT  5.115 44.765 5.397 47.695 ;
     RECT  4.68 47.695 5.397 47.741 ;
     RECT  6.984 48.361 7.002 48.379 ;
     RECT  20.52 46.741 20.538 48.413 ;
     RECT  6.984 48.379 7.074 48.425 ;
     RECT  6.984 48.425 7.002 48.533 ;
     RECT  2.415 46.913 2.697 49.195 ;
     RECT  20.52 49.171 20.538 49.229 ;
     RECT  2.304 49.195 2.697 49.235 ;
     RECT  4.32 49.051 4.338 49.421 ;
     RECT  5.115 47.741 5.397 49.891 ;
     RECT  2.415 49.235 2.697 49.963 ;
     RECT  5.115 49.891 5.778 50.009 ;
     RECT  21.492 49.963 21.51 50.009 ;
     RECT  5.115 50.009 5.598 50.153 ;
     RECT  2.34 49.963 2.697 50.731 ;
     RECT  2.304 50.731 2.697 50.855 ;
     RECT  5.115 50.153 5.397 50.935 ;
     RECT  4.68 50.935 5.397 51.005 ;
     RECT  21.492 50.731 21.51 51.629 ;
     RECT  7.815 45.581 8.097 51.637 ;
     RECT  1.152 51.499 1.17 51.677 ;
     RECT  3.996 51.637 4.014 51.677 ;
     RECT  7.815 51.637 8.154 51.677 ;
     RECT  6.84 51.601 6.858 51.773 ;
     RECT  2.415 50.855 2.697 52.267 ;
     RECT  20.52 52.141 20.538 52.301 ;
     RECT  2.304 52.267 2.697 52.313 ;
     RECT  4.248 52.285 4.266 52.349 ;
     RECT  2.415 52.313 2.697 53.083 ;
     RECT  5.115 51.005 5.397 53.179 ;
     RECT  5.115 53.179 5.634 53.249 ;
     RECT  10.515 42.221 10.797 53.257 ;
     RECT  10.515 53.257 11.358 53.429 ;
     RECT  5.115 53.249 5.397 53.563 ;
     RECT  21.492 53.083 21.51 54.059 ;
     RECT  2.304 53.083 2.697 54.095 ;
     RECT  4.572 53.563 5.397 54.571 ;
     RECT  4.428 54.571 5.994 54.607 ;
     RECT  4.428 54.607 6.282 54.619 ;
     RECT  3.996 54.619 6.282 54.635 ;
     RECT  20.52 54.571 20.538 54.653 ;
     RECT  3.996 54.635 5.397 54.749 ;
     RECT  6.12 54.635 6.282 54.869 ;
     RECT  3.996 54.749 4.338 54.905 ;
     RECT  6.264 54.869 6.282 55.021 ;
     RECT  6.264 55.021 6.462 55.139 ;
     RECT  2.415 54.095 2.697 55.387 ;
     RECT  6.48 55.381 6.858 55.421 ;
     RECT  20.52 55.381 20.538 55.421 ;
     RECT  4.14 54.905 4.338 55.489 ;
     RECT  5.115 54.749 5.397 55.489 ;
     RECT  6.48 55.421 6.498 55.523 ;
     RECT  4.14 55.489 5.397 55.589 ;
     RECT  4.32 55.589 5.397 55.679 ;
     RECT  9.144 55.561 9.162 55.679 ;
     RECT  2.304 55.387 2.697 56.255 ;
     RECT  5.115 55.679 5.397 56.371 ;
     RECT  0.108 56.875 0.126 57.005 ;
     RECT  21.492 56.155 21.51 57.005 ;
     RECT  3.996 56.875 4.014 57.019 ;
     RECT  5.115 56.371 5.634 57.019 ;
     RECT  11.52 56.875 11.538 57.029 ;
     RECT  3.996 57.019 4.194 57.065 ;
     RECT  4.176 57.065 4.194 57.299 ;
     RECT  5.115 57.019 5.778 57.451 ;
     RECT  10.515 53.429 10.797 57.541 ;
     RECT  7.815 51.677 8.097 57.547 ;
     RECT  4.32 57.451 5.778 57.569 ;
     RECT  6.516 57.019 6.534 57.569 ;
     RECT  5.115 57.569 5.778 57.581 ;
     RECT  10.515 57.541 11.25 57.605 ;
     RECT  9.108 57.541 9.126 57.839 ;
     RECT  0.108 57.739 0.126 57.875 ;
     RECT  7.38 57.547 8.097 58.157 ;
     RECT  2.415 56.255 2.697 58.507 ;
     RECT  2.304 58.507 2.697 58.531 ;
     RECT  4.32 57.569 4.338 58.531 ;
     RECT  5.115 57.581 5.397 58.531 ;
     RECT  4.32 58.531 5.397 58.621 ;
     RECT  2.304 58.531 3.114 58.649 ;
     RECT  4.176 58.621 5.397 58.649 ;
     RECT  21.492 58.507 21.51 58.649 ;
     RECT  2.304 58.649 2.697 58.685 ;
     RECT  4.176 58.649 4.194 59.161 ;
     RECT  3.96 59.161 4.194 59.261 ;
     RECT  0.54 59.197 0.558 59.309 ;
     RECT  11.628 59.233 11.646 59.309 ;
     RECT  3.96 59.261 3.978 59.333 ;
     RECT  3.996 60.007 4.014 60.077 ;
     RECT  5.115 58.649 5.397 60.808 ;
     RECT  7.815 58.157 8.097 60.811 ;
     RECT  5.115 60.808 5.454 60.845 ;
     RECT  20.52 60.007 20.538 60.845 ;
     RECT  7.815 60.811 8.154 60.851 ;
     RECT  6.84 60.091 6.858 60.953 ;
     RECT  2.415 58.685 2.697 61.621 ;
     RECT  2.415 61.621 2.826 61.661 ;
     RECT  20.52 61.591 20.538 61.661 ;
     RECT  4.32 61.765 4.338 61.805 ;
     RECT  2.415 61.661 2.697 62.395 ;
     RECT  21.492 62.392 21.51 62.429 ;
     RECT  5.115 60.845 5.397 62.581 ;
     RECT  5.115 62.581 5.634 62.621 ;
     RECT  5.115 62.621 5.397 63.211 ;
     RECT  2.304 62.395 2.697 63.275 ;
     RECT  4.68 63.211 5.397 63.275 ;
     RECT  6.84 64.021 6.858 64.027 ;
     RECT  0.108 63.931 0.126 64.085 ;
     RECT  6.84 64.027 7.074 64.085 ;
     RECT  6.84 64.085 6.858 64.193 ;
     RECT  21.492 63.163 21.51 64.859 ;
     RECT  4.284 64.903 4.302 64.973 ;
     RECT  2.415 63.275 2.697 65.515 ;
     RECT  2.304 65.515 2.697 65.551 ;
     RECT  5.115 63.275 5.397 65.551 ;
     RECT  2.304 65.551 2.826 65.669 ;
     RECT  11.772 65.515 11.79 65.669 ;
     RECT  2.304 65.669 2.697 65.705 ;
     RECT  4.68 65.551 5.397 65.785 ;
     RECT  4.5 65.785 5.397 65.837 ;
     RECT  3.996 66.283 4.014 66.353 ;
     RECT  6.3 66.325 6.318 66.701 ;
     RECT  20.52 66.181 20.538 67.085 ;
     RECT  7.056 66.667 7.074 67.181 ;
     RECT  2.415 65.705 2.697 67.771 ;
     RECT  2.415 67.771 3.258 67.819 ;
     RECT  2.304 67.819 3.258 67.829 ;
     RECT  11.952 67.801 11.97 67.853 ;
     RECT  2.304 67.829 2.697 67.865 ;
     RECT  2.415 67.865 2.697 68.587 ;
     RECT  21.492 68.587 21.51 68.639 ;
     RECT  2.304 68.587 2.697 68.675 ;
     RECT  5.115 65.837 5.397 68.779 ;
     RECT  5.115 68.779 5.634 68.819 ;
     RECT  21.492 69.403 21.51 69.449 ;
     RECT  0.108 69.403 0.126 69.485 ;
     RECT  6.84 68.779 6.858 69.593 ;
     RECT  5.115 68.819 5.397 70.123 ;
     RECT  2.415 68.675 2.697 70.141 ;
     RECT  2.304 70.141 2.697 70.205 ;
     RECT  5.004 70.123 5.397 70.295 ;
     RECT  7.056 70.375 7.074 70.445 ;
     RECT  2.415 70.205 2.697 70.939 ;
     RECT  21.492 70.171 21.51 71.069 ;
     RECT  4.32 70.699 4.338 71.221 ;
     RECT  5.115 70.295 5.397 71.221 ;
     RECT  4.32 71.221 5.397 71.249 ;
     RECT  4.572 71.249 5.397 71.609 ;
     RECT  2.304 70.939 2.697 71.753 ;
     RECT  5.115 71.609 5.397 72.379 ;
     RECT  4.14 72.427 4.158 72.509 ;
     RECT  5.115 72.379 5.778 72.811 ;
     RECT  5.115 72.811 6.03 72.959 ;
     RECT  5.115 72.959 5.706 73.337 ;
     RECT  7.815 60.851 8.097 73.339 ;
     RECT  7.632 73.339 8.097 73.379 ;
     RECT  5.115 73.337 5.397 74.083 ;
     RECT  20.52 71.581 20.538 74.093 ;
     RECT  20.52 74.821 20.538 74.861 ;
     RECT  4.536 74.083 5.397 75.053 ;
     RECT  2.415 71.753 2.697 75.595 ;
     RECT  2.304 75.595 2.697 75.659 ;
     RECT  3.996 75.643 4.014 75.695 ;
     RECT  5.115 75.053 5.397 75.775 ;
     RECT  5.115 75.775 5.778 75.821 ;
     RECT  0.108 76.363 0.126 76.493 ;
     RECT  4.356 76.459 4.374 76.505 ;
     RECT  7.815 73.379 8.097 76.585 ;
     RECT  7.815 76.585 8.154 76.637 ;
     RECT  2.415 75.659 2.697 77.179 ;
     RECT  21.492 75.595 21.51 77.279 ;
     RECT  2.304 77.179 2.697 77.315 ;
     RECT  4.32 77.431 4.338 77.501 ;
     RECT  5.115 75.821 5.397 77.935 ;
     RECT  20.52 77.791 20.538 77.981 ;
     RECT  5.115 77.935 5.454 78.125 ;
     RECT  6.3 78.091 6.318 78.601 ;
     RECT  10.515 57.605 10.797 78.601 ;
     RECT  6.228 78.601 6.318 78.665 ;
     RECT  0.108 78.637 0.126 78.749 ;
     RECT  10.515 78.601 11.394 78.749 ;
     RECT  6.228 78.665 6.246 78.773 ;
     RECT  7.056 79.435 7.074 79.475 ;
     RECT  20.52 79.411 20.538 79.517 ;
     RECT  4.32 80.203 4.338 80.221 ;
     RECT  2.415 77.315 2.697 80.248 ;
     RECT  4.248 80.221 4.338 80.249 ;
     RECT  2.304 80.248 2.697 80.285 ;
     RECT  19.944 80.221 19.962 80.285 ;
     RECT  4.248 80.249 4.266 80.357 ;
     RECT  2.415 80.285 2.697 81.061 ;
     RECT  2.415 81.061 2.826 81.101 ;
     RECT  19.944 81.031 19.962 81.101 ;
     RECT  5.115 78.125 5.397 81.175 ;
     RECT  5.115 81.175 5.598 81.451 ;
     RECT  4.68 81.451 5.598 81.485 ;
     RECT  2.415 81.101 2.697 81.835 ;
     RECT  20.484 81.832 20.502 81.869 ;
     RECT  4.68 81.485 5.397 82.061 ;
     RECT  10.515 78.749 10.797 82.459 ;
     RECT  14.832 82.459 14.85 82.589 ;
     RECT  2.304 81.835 2.697 82.637 ;
     RECT  21.492 82.459 21.51 82.637 ;
     RECT  10.515 82.459 11.394 82.679 ;
     RECT  3.996 82.555 4.014 82.715 ;
     RECT  7.815 76.637 8.097 82.789 ;
     RECT  7.815 82.789 8.154 82.829 ;
     RECT  21.492 83.371 21.51 83.489 ;
     RECT  4.32 83.641 4.338 83.789 ;
     RECT  2.415 82.637 2.697 84.136 ;
     RECT  2.415 84.136 2.754 84.173 ;
     RECT  20.52 84.001 20.538 84.173 ;
     RECT  15.915 2.413 16.197 84.811 ;
     RECT  5.115 82.061 5.397 84.883 ;
     RECT  5.115 84.883 5.814 84.941 ;
     RECT  0.54 84.847 0.558 84.989 ;
     RECT  15.915 84.811 16.542 84.989 ;
     RECT  20.52 85.621 20.538 85.757 ;
     RECT  7.815 82.829 8.097 85.765 ;
     RECT  7.596 85.765 8.097 85.805 ;
     RECT  2.415 84.173 2.697 86.431 ;
     RECT  2.415 86.431 2.862 86.467 ;
     RECT  2.412 86.467 2.862 86.525 ;
     RECT  19.944 86.431 19.962 86.525 ;
     RECT  2.415 86.525 2.862 86.587 ;
     RECT  2.415 86.587 3.258 86.639 ;
     RECT  5.115 84.941 5.397 87.211 ;
     RECT  2.415 86.639 2.697 87.259 ;
     RECT  20.52 87.241 20.538 87.293 ;
     RECT  2.304 87.259 2.697 87.305 ;
     RECT  5.115 87.211 5.598 87.413 ;
     RECT  5.115 87.413 5.397 87.781 ;
     RECT  2.415 87.305 2.697 88.027 ;
     RECT  20.484 88.027 20.502 88.079 ;
     RECT  2.304 88.027 2.697 88.115 ;
     RECT  4.68 87.781 5.397 88.619 ;
     RECT  21.492 88.843 21.51 88.889 ;
     RECT  7.815 85.805 8.097 88.891 ;
     RECT  0.108 88.843 0.126 88.925 ;
     RECT  4.716 88.619 5.397 88.925 ;
     RECT  7.815 88.891 8.154 88.931 ;
     RECT  2.415 88.115 2.697 89.611 ;
     RECT  2.304 89.611 2.697 89.845 ;
     RECT  7.815 88.931 8.097 89.851 ;
     RECT  2.304 89.845 3.258 89.885 ;
     RECT  7.488 89.851 8.097 89.941 ;
     RECT  5.115 88.925 5.397 90.475 ;
     RECT  4.968 90.475 5.397 90.481 ;
     RECT  7.416 89.941 8.097 90.481 ;
     RECT  20.484 89.611 20.502 90.509 ;
     RECT  2.304 89.885 2.697 90.545 ;
     RECT  3.96 90.481 5.397 90.553 ;
     RECT  3.96 90.553 5.706 90.581 ;
     RECT  4.14 90.581 5.706 90.779 ;
     RECT  7.38 90.481 8.097 90.779 ;
     RECT  20.52 91.021 20.538 91.181 ;
     RECT  4.14 90.779 5.397 91.193 ;
     RECT  4.572 91.193 5.397 91.499 ;
     RECT  7.815 90.779 8.097 91.867 ;
     RECT  7.416 91.867 8.097 92.011 ;
     RECT  9.756 92.011 9.774 92.129 ;
     RECT  7.2 92.011 8.097 92.245 ;
     RECT  7.056 92.245 8.097 92.333 ;
     RECT  7.416 92.333 8.097 92.399 ;
     RECT  19.944 91.831 19.962 92.717 ;
     RECT  4.32 92.821 4.338 92.861 ;
     RECT  5.115 91.499 5.397 93.361 ;
     RECT  10.515 82.679 10.797 93.361 ;
     RECT  10.404 93.361 10.797 93.451 ;
     RECT  4.392 93.361 5.397 93.479 ;
     RECT  10.404 93.451 11.394 93.479 ;
     RECT  2.415 90.545 2.697 93.487 ;
     RECT  3.42 93.451 3.438 93.487 ;
     RECT  2.415 93.487 3.438 93.515 ;
     RECT  2.415 93.515 2.826 93.533 ;
     RECT  10.515 93.479 11.394 93.533 ;
     RECT  2.415 93.533 2.697 94.267 ;
     RECT  19.944 94.261 19.962 94.301 ;
     RECT  5.115 93.479 5.397 95.083 ;
     RECT  2.304 94.267 2.697 95.099 ;
     RECT  6.84 94.267 6.858 95.107 ;
     RECT  5.004 95.083 5.397 95.135 ;
     RECT  6.84 95.107 7.074 95.165 ;
     RECT  20.484 95.035 20.502 95.909 ;
     RECT  2.412 95.099 2.697 95.945 ;
     RECT  4.32 96.061 4.338 96.125 ;
     RECT  2.415 95.945 2.697 96.565 ;
     RECT  2.415 96.565 2.826 96.605 ;
     RECT  5.115 95.135 5.397 96.811 ;
     RECT  12.168 97.141 12.186 97.259 ;
     RECT  2.415 96.605 2.697 97.375 ;
     RECT  2.415 97.375 2.79 97.421 ;
     RECT  5.04 96.811 5.397 97.421 ;
     RECT  20.52 96.421 20.538 97.421 ;
     RECT  20.484 98.155 20.502 98.339 ;
     RECT  3.996 98.155 4.014 98.375 ;
     RECT  6.84 98.347 6.858 98.455 ;
     RECT  6.84 98.455 7.074 98.519 ;
     RECT  7.056 98.519 7.074 98.525 ;
     RECT  2.415 97.421 2.697 98.851 ;
     RECT  2.415 98.851 2.862 99.031 ;
     RECT  5.115 97.421 5.397 99.163 ;
     RECT  2.415 99.031 3.258 99.197 ;
     RECT  2.415 99.197 2.697 99.688 ;
     RECT  2.34 99.688 2.697 99.725 ;
     RECT  4.5 99.163 5.397 99.725 ;
     RECT  19.944 98.851 19.962 99.725 ;
     RECT  21.492 100.459 21.51 100.499 ;
     RECT  5.115 99.725 5.397 100.507 ;
     RECT  0.108 100.459 0.126 100.535 ;
     RECT  5.115 100.507 5.778 100.544 ;
     RECT  7.815 92.399 8.097 101.131 ;
     RECT  21.492 101.272 21.51 101.309 ;
     RECT  0.108 101.275 0.126 101.345 ;
     RECT  7.815 101.131 8.154 101.345 ;
     RECT  6.84 101.281 6.858 101.453 ;
     RECT  2.415 99.725 2.697 102.043 ;
     RECT  21.492 102.043 21.51 102.119 ;
     RECT  20.484 102.811 20.502 102.929 ;
     RECT  2.304 102.043 2.697 102.965 ;
     RECT  4.32 102.043 4.338 103.081 ;
     RECT  5.115 100.544 5.397 103.081 ;
     RECT  4.32 103.081 5.397 103.109 ;
     RECT  4.536 103.109 5.397 103.133 ;
     RECT  2.415 102.965 2.697 103.579 ;
     RECT  21.492 103.579 21.51 103.739 ;
     RECT  2.415 103.579 2.79 103.775 ;
     RECT  5.115 103.133 5.397 103.855 ;
     RECT  4.68 103.855 5.397 103.901 ;
     RECT  20.484 104.347 20.502 104.549 ;
     RECT  4.284 104.347 4.302 104.585 ;
     RECT  7.815 101.345 8.097 104.665 ;
     RECT  7.815 104.665 8.154 104.717 ;
     RECT  2.415 103.775 2.697 104.875 ;
     RECT  2.415 104.875 3.366 105.089 ;
     RECT  2.415 105.089 2.697 105.16 ;
     RECT  2.304 105.16 2.697 105.197 ;
     RECT  2.415 105.197 2.697 105.907 ;
     RECT  5.115 103.901 5.397 105.943 ;
     RECT  2.415 105.907 2.826 105.965 ;
     RECT  5.115 105.943 5.598 106.699 ;
     RECT  4.464 106.699 5.598 106.717 ;
     RECT  19.944 105.061 19.962 106.733 ;
     RECT  4.464 106.717 5.778 106.745 ;
     RECT  5.115 106.745 5.778 106.781 ;
     RECT  7.815 104.717 8.097 107.275 ;
     RECT  21.492 107.467 21.51 107.519 ;
     RECT  0.108 107.467 0.126 107.555 ;
     RECT  7.815 107.275 8.154 107.555 ;
     RECT  5.115 106.781 5.397 107.755 ;
     RECT  5.115 107.755 5.49 108.031 ;
     RECT  5.115 108.031 5.814 108.077 ;
     RECT  10.515 93.533 10.797 108.211 ;
     RECT  18.615 4.205 18.897 108.211 ;
     RECT  18.615 108.211 18.99 108.269 ;
     RECT  10.515 108.211 11.322 108.329 ;
     RECT  5.115 108.077 5.397 108.481 ;
     RECT  2.415 105.965 2.697 109.051 ;
     RECT  10.515 108.329 10.797 109.147 ;
     RECT  10.515 109.147 11.358 109.319 ;
     RECT  4.5 108.481 5.397 109.325 ;
     RECT  5.115 109.325 5.397 109.957 ;
     RECT  2.304 109.051 2.697 109.985 ;
     RECT  5.115 109.957 5.778 109.997 ;
     RECT  21.492 109.051 21.51 110.795 ;
     RECT  5.115 109.997 5.49 110.869 ;
     RECT  5.115 110.869 5.994 110.909 ;
     RECT  11.556 110.767 11.574 110.939 ;
     RECT  4.32 111.259 4.338 111.271 ;
     RECT  4.248 111.271 4.338 111.371 ;
     RECT  4.32 111.371 4.338 112.081 ;
     RECT  5.115 110.909 5.397 112.081 ;
     RECT  4.32 112.081 5.397 112.109 ;
     RECT  2.415 109.985 2.697 112.117 ;
     RECT  2.415 112.117 2.826 112.157 ;
     RECT  20.52 111.271 20.538 112.157 ;
     RECT  4.536 112.109 5.397 112.927 ;
     RECT  4.032 112.927 5.397 112.973 ;
     RECT  20.52 112.891 20.538 112.973 ;
     RECT  4.536 112.973 5.397 112.978 ;
     RECT  20.52 113.701 20.538 113.741 ;
     RECT  7.815 107.555 8.097 113.845 ;
     RECT  7.815 113.845 8.154 113.885 ;
     RECT  2.415 112.157 2.697 114.475 ;
     RECT  21.492 114.475 21.51 114.539 ;
     RECT  4.284 114.523 4.302 114.575 ;
     RECT  5.115 112.978 5.397 115.291 ;
     RECT  4.536 115.291 5.397 115.349 ;
     RECT  2.304 114.475 2.697 115.385 ;
     RECT  20.484 115.243 20.502 116.159 ;
     RECT  5.115 115.349 5.397 116.167 ;
     RECT  4.068 116.011 4.086 116.195 ;
     RECT  5.115 116.167 5.778 116.237 ;
     RECT  3.996 116.827 4.014 117.005 ;
     RECT  7.056 116.971 7.074 117.011 ;
     RECT  5.115 116.237 5.397 117.451 ;
     RECT  4.428 117.451 5.397 117.509 ;
     RECT  2.415 115.385 2.697 117.589 ;
     RECT  2.415 117.589 2.826 117.629 ;
     RECT  3.456 118.267 3.474 118.319 ;
     RECT  10.515 109.319 10.797 118.327 ;
     RECT  2.415 117.629 2.697 118.357 ;
     RECT  2.415 118.357 2.826 118.397 ;
     RECT  20.52 117.481 20.538 118.397 ;
     RECT  10.515 118.327 11.358 118.499 ;
     RECT  10.515 118.499 11.322 119.165 ;
     RECT  6.84 119.227 6.858 119.273 ;
     RECT  5.115 117.509 5.397 119.899 ;
     RECT  13.215 2.413 13.497 119.947 ;
     RECT  0.108 119.899 0.126 119.975 ;
     RECT  5.115 119.899 5.994 119.975 ;
     RECT  21.492 119.899 21.51 119.975 ;
     RECT  12.636 119.947 13.497 120.119 ;
     RECT  2.415 118.397 2.697 120.715 ;
     RECT  2.304 120.715 2.697 120.721 ;
     RECT  21.492 120.712 21.51 120.749 ;
     RECT  2.304 120.721 3.258 120.797 ;
     RECT  5.115 119.975 5.397 121.483 ;
     RECT  2.304 120.797 2.697 121.517 ;
     RECT  5.115 121.483 5.634 121.559 ;
     RECT  4.032 121.435 4.05 121.595 ;
     RECT  20.484 121.483 20.502 122.369 ;
     RECT  0.108 122.251 0.126 122.405 ;
     RECT  6.84 122.347 6.858 122.539 ;
     RECT  6.516 122.539 6.858 122.573 ;
     RECT  6.516 122.573 6.534 122.945 ;
     RECT  3.996 123.016 4.014 123.053 ;
     RECT  20.52 122.881 20.538 123.053 ;
     RECT  2.415 121.517 2.697 123.787 ;
     RECT  19.944 123.691 19.962 123.821 ;
     RECT  2.304 123.787 2.697 123.863 ;
     RECT  4.248 123.691 4.266 124.219 ;
     RECT  4.14 124.219 4.266 124.231 ;
     RECT  5.115 121.559 5.397 124.231 ;
     RECT  4.14 124.231 5.397 124.459 ;
     RECT  2.415 123.863 2.697 124.501 ;
     RECT  20.52 124.501 20.538 124.589 ;
     RECT  2.415 124.501 2.862 124.709 ;
     RECT  4.14 124.459 5.634 124.835 ;
     RECT  4.428 124.835 5.634 124.979 ;
     RECT  4.572 124.979 5.634 125.323 ;
     RECT  6.804 125.311 6.822 125.323 ;
     RECT  4.572 125.323 6.822 125.339 ;
     RECT  9.648 125.221 9.666 125.339 ;
     RECT  2.415 124.709 2.697 125.371 ;
     RECT  4.572 125.339 5.397 125.375 ;
     RECT  6.336 125.339 6.822 125.375 ;
     RECT  6.804 125.375 6.822 125.405 ;
     RECT  20.52 125.311 20.538 125.405 ;
     RECT  2.304 125.371 2.697 125.411 ;
     RECT  19.944 126.121 19.962 126.173 ;
     RECT  5.115 125.375 5.397 126.379 ;
     RECT  5.115 126.379 5.778 126.419 ;
     RECT  5.115 126.419 5.634 126.599 ;
     RECT  7.056 125.995 7.074 126.619 ;
     RECT  2.415 125.411 2.697 126.841 ;
     RECT  4.14 126.523 4.158 126.841 ;
     RECT  5.115 126.599 5.397 126.841 ;
     RECT  6.948 126.619 7.074 126.869 ;
     RECT  2.415 126.841 3.222 126.907 ;
     RECT  6.948 126.869 6.966 126.989 ;
     RECT  2.304 126.907 3.222 126.995 ;
     RECT  4.14 126.841 5.397 127.421 ;
     RECT  10.515 119.165 10.797 127.777 ;
     RECT  5.115 127.421 5.397 127.921 ;
     RECT  10.515 127.777 11.358 127.949 ;
     RECT  5.115 127.921 5.634 127.997 ;
     RECT  2.304 126.995 2.697 128.615 ;
     RECT  5.115 127.997 5.397 128.695 ;
     RECT  4.68 128.695 5.397 129.163 ;
     RECT  1.152 129.163 1.17 129.293 ;
     RECT  21.492 126.907 21.51 129.389 ;
     RECT  3.996 129.163 5.397 129.425 ;
     RECT  7.056 129.505 7.074 129.581 ;
     RECT  4.392 129.425 5.397 129.971 ;
     RECT  0.54 129.937 0.558 130.061 ;
     RECT  11.952 129.937 11.97 130.061 ;
     RECT  2.415 128.615 2.697 130.747 ;
     RECT  2.304 130.747 2.697 130.829 ;
     RECT  5.115 129.971 5.397 130.885 ;
     RECT  5.115 130.885 5.634 131.557 ;
     RECT  4.5 131.557 5.778 131.597 ;
     RECT  20.52 130.711 20.538 131.597 ;
     RECT  20.52 132.325 20.538 132.365 ;
     RECT  1.152 132.331 1.17 132.461 ;
     RECT  7.815 113.885 8.097 132.469 ;
     RECT  3.996 132.427 4.014 132.503 ;
     RECT  7.815 132.469 8.154 132.509 ;
     RECT  2.415 130.829 2.697 133.147 ;
     RECT  4.32 133.099 4.338 133.169 ;
     RECT  20.52 133.141 20.538 133.181 ;
     RECT  10.515 127.949 10.797 133.819 ;
     RECT  21.492 133.819 21.51 133.949 ;
     RECT  10.515 133.819 11.43 133.979 ;
     RECT  2.304 133.147 2.697 134.015 ;
     RECT  5.115 131.597 5.397 134.131 ;
     RECT  5.115 134.131 5.634 134.189 ;
     RECT  6.84 134.761 6.858 134.779 ;
     RECT  0.108 134.683 0.126 134.825 ;
     RECT  6.84 134.779 7.074 134.825 ;
     RECT  6.84 134.825 6.93 134.933 ;
     RECT  2.415 134.015 2.697 135.445 ;
     RECT  5.115 134.189 5.397 135.445 ;
     RECT  2.415 135.445 2.826 135.485 ;
     RECT  5.115 135.445 5.994 135.485 ;
     RECT  6.912 134.933 6.93 135.599 ;
     RECT  20.484 134.683 20.502 135.599 ;
     RECT  4.248 136.123 4.266 136.175 ;
     RECT  10.515 133.979 10.797 136.183 ;
     RECT  0.54 136.183 0.558 136.253 ;
     RECT  10.515 136.183 11.214 136.253 ;
     RECT  2.415 135.485 2.697 137.035 ;
     RECT  3.456 137.179 3.474 137.219 ;
     RECT  21.492 137.035 21.51 137.219 ;
     RECT  2.304 137.035 2.697 137.255 ;
     RECT  5.115 135.485 5.397 137.755 ;
     RECT  2.415 137.255 2.697 137.767 ;
     RECT  4.68 137.755 5.397 137.795 ;
     RECT  2.415 137.767 2.826 137.837 ;
     RECT  19.944 137.731 19.962 137.837 ;
     RECT  5.115 137.795 5.397 138.568 ;
     RECT  5.115 138.568 5.562 138.605 ;
     RECT  20.52 138.541 20.538 138.605 ;
     RECT  7.056 138.685 7.074 138.749 ;
     RECT  2.415 137.837 2.697 139.339 ;
     RECT  21.492 139.339 21.51 139.415 ;
     RECT  4.284 139.495 4.302 139.565 ;
     RECT  18.615 108.269 18.897 140.107 ;
     RECT  18.615 140.107 19.386 140.189 ;
     RECT  3.456 140.161 3.474 140.237 ;
     RECT  5.115 138.605 5.397 140.971 ;
     RECT  19.908 140.923 19.926 140.999 ;
     RECT  2.304 139.339 2.697 141.035 ;
     RECT  5.115 140.971 5.778 141.035 ;
     RECT  7.815 132.509 8.097 141.355 ;
     RECT  18.615 140.189 18.897 141.691 ;
     RECT  18.615 141.691 19.386 141.809 ;
     RECT  0.108 141.691 0.126 141.845 ;
     RECT  7.815 141.355 8.154 141.845 ;
     RECT  2.415 141.035 2.697 142.459 ;
     RECT  10.515 136.253 10.797 142.459 ;
     RECT  10.515 142.459 11.358 142.619 ;
     RECT  2.34 142.459 2.697 142.655 ;
     RECT  4.284 142.507 4.302 142.655 ;
     RECT  5.115 141.035 5.397 143.167 ;
     RECT  5.112 143.167 5.397 143.213 ;
     RECT  19.944 143.131 19.962 143.261 ;
     RECT  2.415 142.655 2.697 144.467 ;
     RECT  5.115 143.213 5.397 144.467 ;
     RECT  7.815 141.845 8.097 144.467 ;
     RECT  10.515 142.619 10.797 144.467 ;
     RECT  13.215 120.119 13.497 144.467 ;
     RECT  15.915 84.989 16.197 144.467 ;
     RECT  18.615 141.809 18.897 144.467 ;
     RECT  2.415 144.467 2.505 144.737 ;
     RECT  5.115 144.467 5.205 144.737 ;
     RECT  7.815 144.467 7.905 144.737 ;
     RECT  10.515 144.467 10.605 144.737 ;
     RECT  13.215 144.467 13.305 144.737 ;
     RECT  15.915 144.467 16.005 144.737 ;
     RECT  18.615 144.467 18.705 144.737 ;
    LAYER M4 ;
     RECT  0.084 2.544 0.137 2.568 ;
     RECT  0.06 2.568 0.137 3.312 ;
     RECT  0.084 3.312 0.137 3.336 ;
     RECT  0.06 3.336 0.137 4.08 ;
     RECT  0.084 4.08 0.137 4.104 ;
     RECT  0.06 4.104 0.137 4.848 ;
     RECT  0.084 4.848 0.137 4.872 ;
     RECT  0.06 4.872 0.137 5.664 ;
     RECT  0.084 5.664 0.137 5.688 ;
     RECT  0.06 5.688 0.137 6.432 ;
     RECT  0.084 6.432 0.137 6.456 ;
     RECT  0.06 6.456 0.137 7.2 ;
     RECT  0.084 7.2 0.137 7.224 ;
     RECT  0.06 7.224 0.137 7.968 ;
     RECT  0.084 7.968 0.137 7.992 ;
     RECT  0.06 7.992 0.137 8.736 ;
     RECT  0.084 8.736 0.137 8.76 ;
     RECT  0.06 8.76 0.137 9.552 ;
     RECT  0.084 9.552 0.137 9.576 ;
     RECT  0.06 9.576 0.137 10.32 ;
     RECT  0.084 10.32 0.137 10.344 ;
     RECT  0.06 10.344 0.137 11.088 ;
     RECT  0.084 11.088 0.137 11.112 ;
     RECT  0.06 11.112 0.137 11.856 ;
     RECT  0.084 11.856 0.137 11.88 ;
     RECT  0.06 11.88 0.137 12.624 ;
     RECT  0.084 12.624 0.137 12.648 ;
     RECT  0.06 12.648 0.137 13.44 ;
     RECT  0.084 13.44 0.137 13.464 ;
     RECT  0.06 13.464 0.137 14.208 ;
     RECT  0.084 14.208 0.137 14.232 ;
     RECT  0.06 14.232 0.137 14.976 ;
     RECT  0.084 14.976 0.137 15 ;
     RECT  0.06 15 0.137 15.744 ;
     RECT  0.084 15.744 0.137 15.768 ;
     RECT  0.06 15.768 0.137 16.512 ;
     RECT  0.084 16.512 0.137 16.536 ;
     RECT  0.06 16.536 0.137 17.328 ;
     RECT  0.084 17.328 0.137 17.352 ;
     RECT  0.06 17.352 0.137 18.096 ;
     RECT  0.084 18.096 0.137 18.12 ;
     RECT  0.06 18.12 0.137 18.864 ;
     RECT  0.084 18.864 0.137 18.888 ;
     RECT  0.06 18.888 0.137 19.632 ;
     RECT  0.084 19.632 0.137 19.656 ;
     RECT  0.06 19.656 0.137 20.4 ;
     RECT  0.084 20.4 0.137 20.424 ;
     RECT  0.06 20.424 0.137 21.216 ;
     RECT  0.084 21.216 0.137 21.24 ;
     RECT  0.06 21.24 0.137 21.984 ;
     RECT  0.084 21.984 0.137 22.008 ;
     RECT  0.06 22.008 0.137 22.752 ;
     RECT  0.084 22.752 0.137 22.776 ;
     RECT  0.06 22.776 0.137 23.52 ;
     RECT  0.084 23.52 0.137 23.544 ;
     RECT  0.06 23.544 0.137 24.288 ;
     RECT  0.084 24.288 0.137 24.312 ;
     RECT  0.06 24.312 0.137 25.104 ;
     RECT  0.084 25.104 0.137 25.128 ;
     RECT  0.06 25.128 0.137 25.872 ;
     RECT  0.084 25.872 0.137 25.896 ;
     RECT  0.06 25.896 0.137 26.64 ;
     RECT  0.084 26.64 0.137 26.664 ;
     RECT  0.06 26.664 0.137 27.408 ;
     RECT  0.084 27.408 0.137 27.432 ;
     RECT  0.06 27.432 0.137 28.176 ;
     RECT  0.084 28.176 0.137 28.2 ;
     RECT  0.06 28.2 0.137 28.944 ;
     RECT  0.084 28.944 0.137 28.968 ;
     RECT  0.06 28.968 0.137 29.76 ;
     RECT  0.084 29.76 0.137 29.784 ;
     RECT  0.06 29.784 0.137 30.528 ;
     RECT  0.084 30.528 0.137 30.552 ;
     RECT  0.06 30.552 0.137 31.296 ;
     RECT  0.084 31.296 0.137 31.32 ;
     RECT  0.06 31.32 0.137 32.064 ;
     RECT  0.084 32.064 0.137 32.088 ;
     RECT  0.06 32.088 0.137 32.832 ;
     RECT  0.084 32.832 0.137 32.856 ;
     RECT  0.06 32.856 0.137 33.648 ;
     RECT  0.084 33.648 0.137 33.672 ;
     RECT  0.06 33.672 0.137 34.416 ;
     RECT  0.084 34.416 0.137 34.44 ;
     RECT  0.06 34.44 0.137 35.184 ;
     RECT  0.084 35.184 0.137 35.208 ;
     RECT  0.06 35.208 0.137 35.952 ;
     RECT  0.084 35.952 0.137 35.976 ;
     RECT  0.06 35.976 0.137 36.72 ;
     RECT  0.084 36.72 0.137 36.744 ;
     RECT  0.06 36.744 0.137 37.536 ;
     RECT  0.084 37.536 0.137 37.56 ;
     RECT  0.06 37.56 0.137 38.304 ;
     RECT  0.084 38.304 0.137 38.328 ;
     RECT  0.06 38.328 0.137 39.072 ;
     RECT  0.084 39.072 0.137 39.096 ;
     RECT  0.06 39.096 0.137 39.84 ;
     RECT  0.084 39.84 0.137 39.864 ;
     RECT  0.06 39.864 0.137 40.608 ;
     RECT  0.084 40.608 0.137 40.632 ;
     RECT  0.06 40.632 0.137 41.424 ;
     RECT  0.084 41.424 0.137 41.448 ;
     RECT  0.06 41.448 0.137 42.192 ;
     RECT  0.084 42.192 0.137 42.216 ;
     RECT  0.06 42.216 0.137 42.96 ;
     RECT  0.084 42.96 0.137 42.984 ;
     RECT  0.06 42.984 0.137 43.728 ;
     RECT  0.084 43.728 0.137 43.752 ;
     RECT  0.06 43.752 0.137 44.496 ;
     RECT  0.084 44.496 0.137 44.52 ;
     RECT  0.06 44.52 0.137 45.312 ;
     RECT  0.084 45.312 0.137 45.336 ;
     RECT  0.06 45.336 0.137 46.08 ;
     RECT  0.084 46.08 0.137 46.104 ;
     RECT  0.06 46.104 0.137 46.848 ;
     RECT  0.084 46.848 0.137 46.872 ;
     RECT  0.06 46.872 0.137 47.616 ;
     RECT  0.084 47.616 0.137 47.64 ;
     RECT  0.06 47.64 0.137 48.384 ;
     RECT  0.084 48.384 0.137 48.408 ;
     RECT  0.06 48.408 0.137 49.2 ;
     RECT  0.084 49.2 0.137 49.224 ;
     RECT  0.06 49.224 0.137 49.968 ;
     RECT  0.084 49.968 0.137 49.992 ;
     RECT  0.06 49.992 0.137 50.736 ;
     RECT  0.084 50.736 0.137 50.76 ;
     RECT  0.06 50.76 0.137 51.504 ;
     RECT  0.084 51.504 0.137 51.528 ;
     RECT  0.06 51.528 0.137 52.272 ;
     RECT  0.084 52.272 0.137 52.296 ;
     RECT  0.06 52.296 0.137 53.088 ;
     RECT  0.084 53.088 0.137 53.112 ;
     RECT  0.06 53.112 0.137 53.856 ;
     RECT  0.084 53.856 0.137 53.88 ;
     RECT  0.06 53.88 0.137 54.624 ;
     RECT  0.084 54.624 0.137 54.648 ;
     RECT  0.06 54.648 0.137 55.392 ;
     RECT  0.084 55.392 0.137 55.416 ;
     RECT  0.06 55.416 0.137 56.16 ;
     RECT  0.084 56.16 0.137 56.184 ;
     RECT  0.06 56.184 0.137 56.976 ;
     RECT  0.084 56.976 0.137 57 ;
     RECT  0.06 57 0.137 57.744 ;
     RECT  0.084 57.744 0.137 57.768 ;
     RECT  0.06 57.768 0.137 58.512 ;
     RECT  0.084 58.512 0.137 58.536 ;
     RECT  0.06 58.536 0.137 59.28 ;
     RECT  0.084 59.28 0.137 59.304 ;
     RECT  0.06 59.304 0.137 60.048 ;
     RECT  0.084 60.048 0.137 60.072 ;
     RECT  0.06 60.072 0.137 60.816 ;
     RECT  0.084 60.816 0.137 60.84 ;
     RECT  0.06 60.84 0.137 61.632 ;
     RECT  0.084 61.632 0.137 61.656 ;
     RECT  0.06 61.656 0.137 62.4 ;
     RECT  0.084 62.4 0.137 62.424 ;
     RECT  0.06 62.424 0.137 63.168 ;
     RECT  0.084 63.168 0.137 63.192 ;
     RECT  0.06 63.192 0.137 63.936 ;
     RECT  0.084 63.936 0.137 63.96 ;
     RECT  0.06 63.96 0.137 64.704 ;
     RECT  0.084 64.704 0.137 64.728 ;
     RECT  0.06 64.728 0.137 65.52 ;
     RECT  0.084 65.52 0.137 65.544 ;
     RECT  0.06 65.544 0.137 66.288 ;
     RECT  0.084 66.288 0.137 66.312 ;
     RECT  0.06 66.312 0.137 67.056 ;
     RECT  0.084 67.056 0.137 67.08 ;
     RECT  0.06 67.08 0.137 67.824 ;
     RECT  0.084 67.824 0.137 67.848 ;
     RECT  0.06 67.848 0.137 68.592 ;
     RECT  0.084 68.592 0.137 68.616 ;
     RECT  0.06 68.616 0.137 69.408 ;
     RECT  0.084 69.408 0.137 69.432 ;
     RECT  0.06 69.432 0.137 70.176 ;
     RECT  0.084 70.176 0.137 70.2 ;
     RECT  0.06 70.2 0.137 70.944 ;
     RECT  0.084 70.944 0.137 70.968 ;
     RECT  0.06 70.968 0.137 71.712 ;
     RECT  0.084 71.712 0.137 71.736 ;
     RECT  0.06 71.736 0.137 72.48 ;
     RECT  0.084 72.48 0.137 72.504 ;
     RECT  0.06 72.504 0.137 73.296 ;
     RECT  0.084 73.296 0.137 73.32 ;
     RECT  0.06 73.32 0.137 74.064 ;
     RECT  0.084 74.064 0.137 74.088 ;
     RECT  0.06 74.088 0.137 74.832 ;
     RECT  0.084 74.832 0.137 74.856 ;
     RECT  0.06 74.856 0.137 75.6 ;
     RECT  0.084 75.6 0.137 75.624 ;
     RECT  0.06 75.624 0.137 76.368 ;
     RECT  0.084 76.368 0.137 76.392 ;
     RECT  0.06 76.392 0.137 77.184 ;
     RECT  0.084 77.184 0.137 77.208 ;
     RECT  0.06 77.208 0.137 77.952 ;
     RECT  0.084 77.952 0.137 77.976 ;
     RECT  0.06 77.976 0.137 78.72 ;
     RECT  0.084 78.72 0.137 78.744 ;
     RECT  0.06 78.744 0.137 79.488 ;
     RECT  0.084 79.488 0.137 79.512 ;
     RECT  0.06 79.512 0.137 80.256 ;
     RECT  0.084 80.256 0.137 80.28 ;
     RECT  0.06 80.28 0.137 81.072 ;
     RECT  0.084 81.072 0.137 81.096 ;
     RECT  0.06 81.096 0.137 81.84 ;
     RECT  0.084 81.84 0.137 81.864 ;
     RECT  0.06 81.864 0.137 82.608 ;
     RECT  0.084 82.608 0.137 82.632 ;
     RECT  0.06 82.632 0.137 83.376 ;
     RECT  0.084 83.376 0.137 83.4 ;
     RECT  0.06 83.4 0.137 84.144 ;
     RECT  0.084 84.144 0.137 84.168 ;
     RECT  0.06 84.168 0.137 84.96 ;
     RECT  0.084 84.96 0.137 84.984 ;
     RECT  0.06 84.984 0.137 85.728 ;
     RECT  0.084 85.728 0.137 85.752 ;
     RECT  0.06 85.752 0.137 86.496 ;
     RECT  0.084 86.496 0.137 86.52 ;
     RECT  0.06 86.52 0.137 87.264 ;
     RECT  0.084 87.264 0.137 87.288 ;
     RECT  0.06 87.288 0.137 88.032 ;
     RECT  0.084 88.032 0.137 88.056 ;
     RECT  0.06 88.056 0.137 88.848 ;
     RECT  0.084 88.848 0.137 88.872 ;
     RECT  0.06 88.872 0.137 89.616 ;
     RECT  0.084 89.616 0.137 89.64 ;
     RECT  0.06 89.64 0.137 90.384 ;
     RECT  0.084 90.384 0.137 90.408 ;
     RECT  0.06 90.408 0.137 91.152 ;
     RECT  0.084 91.152 0.137 91.176 ;
     RECT  0.06 91.176 0.137 91.92 ;
     RECT  0.084 91.92 0.137 91.944 ;
     RECT  0.06 91.944 0.137 92.688 ;
     RECT  0.084 92.688 0.137 92.712 ;
     RECT  0.06 92.712 0.137 93.504 ;
     RECT  0.084 93.504 0.137 93.528 ;
     RECT  0.06 93.528 0.137 94.272 ;
     RECT  0.084 94.272 0.137 94.296 ;
     RECT  0.06 94.296 0.137 95.04 ;
     RECT  0.084 95.04 0.137 95.064 ;
     RECT  0.06 95.064 0.137 95.808 ;
     RECT  0.084 95.808 0.137 95.832 ;
     RECT  0.06 95.832 0.137 96.576 ;
     RECT  0.084 96.576 0.137 96.6 ;
     RECT  0.06 96.6 0.137 97.392 ;
     RECT  0.084 97.392 0.137 97.416 ;
     RECT  0.06 97.416 0.137 98.16 ;
     RECT  0.084 98.16 0.137 98.184 ;
     RECT  0.06 98.184 0.137 98.928 ;
     RECT  0.084 98.928 0.137 98.952 ;
     RECT  0.06 98.952 0.137 99.696 ;
     RECT  0.084 99.696 0.137 99.72 ;
     RECT  0.06 99.72 0.137 100.464 ;
     RECT  0.084 100.464 0.137 100.488 ;
     RECT  0.06 100.488 0.137 101.28 ;
     RECT  0.084 101.28 0.137 101.304 ;
     RECT  0.06 101.304 0.137 102.048 ;
     RECT  0.084 102.048 0.137 102.072 ;
     RECT  0.06 102.072 0.137 102.816 ;
     RECT  0.084 102.816 0.137 102.84 ;
     RECT  0.06 102.84 0.137 103.584 ;
     RECT  0.084 103.584 0.137 103.608 ;
     RECT  0.06 103.608 0.137 104.352 ;
     RECT  0.084 104.352 0.137 104.376 ;
     RECT  0.06 104.376 0.137 105.168 ;
     RECT  0.084 105.168 0.137 105.192 ;
     RECT  0.06 105.192 0.137 105.936 ;
     RECT  0.084 105.936 0.137 105.96 ;
     RECT  0.06 105.96 0.137 106.704 ;
     RECT  0.084 106.704 0.137 106.728 ;
     RECT  0.06 106.728 0.137 107.472 ;
     RECT  0.084 107.472 0.137 107.496 ;
     RECT  0.06 107.496 0.137 108.24 ;
     RECT  0.084 108.24 0.137 108.264 ;
     RECT  0.06 108.264 0.137 109.056 ;
     RECT  0.084 109.056 0.137 109.08 ;
     RECT  0.06 109.08 0.137 109.824 ;
     RECT  0.084 109.824 0.137 109.848 ;
     RECT  0.06 109.848 0.137 110.592 ;
     RECT  0.084 110.592 0.137 110.616 ;
     RECT  0.06 110.616 0.137 111.36 ;
     RECT  0.084 111.36 0.137 111.384 ;
     RECT  0.06 111.384 0.137 112.128 ;
     RECT  0.084 112.128 0.137 112.152 ;
     RECT  0.06 112.152 0.137 112.944 ;
     RECT  0.084 112.944 0.137 112.968 ;
     RECT  0.06 112.968 0.137 113.712 ;
     RECT  0.084 113.712 0.137 113.736 ;
     RECT  0.06 113.736 0.137 114.48 ;
     RECT  0.084 114.48 0.137 114.504 ;
     RECT  0.06 114.504 0.137 115.248 ;
     RECT  0.084 115.248 0.137 115.272 ;
     RECT  0.06 115.272 0.137 116.016 ;
     RECT  0.084 116.016 0.137 116.04 ;
     RECT  0.06 116.04 0.137 116.832 ;
     RECT  0.084 116.832 0.137 116.856 ;
     RECT  0.06 116.856 0.137 117.6 ;
     RECT  0.084 117.6 0.137 117.624 ;
     RECT  0.06 117.624 0.137 118.368 ;
     RECT  0.084 118.368 0.137 118.392 ;
     RECT  0.06 118.392 0.137 119.136 ;
     RECT  0.084 119.136 0.137 119.16 ;
     RECT  0.06 119.16 0.137 119.904 ;
     RECT  0.084 119.904 0.137 119.928 ;
     RECT  0.06 119.928 0.137 120.72 ;
     RECT  0.084 120.72 0.137 120.744 ;
     RECT  0.06 120.744 0.137 121.488 ;
     RECT  0.084 121.488 0.137 121.512 ;
     RECT  0.06 121.512 0.137 122.256 ;
     RECT  0.084 122.256 0.137 122.28 ;
     RECT  0.06 122.28 0.137 123.024 ;
     RECT  0.084 123.024 0.137 123.048 ;
     RECT  0.06 123.048 0.137 123.792 ;
     RECT  0.084 123.792 0.137 123.816 ;
     RECT  0.06 123.816 0.137 124.56 ;
     RECT  0.084 124.56 0.137 124.584 ;
     RECT  0.06 124.584 0.137 125.376 ;
     RECT  0.084 125.376 0.137 125.4 ;
     RECT  0.06 125.4 0.137 126.144 ;
     RECT  0.084 126.144 0.137 126.168 ;
     RECT  0.06 126.168 0.137 126.912 ;
     RECT  0.084 126.912 0.137 126.936 ;
     RECT  0.06 126.936 0.137 127.68 ;
     RECT  0.084 127.68 0.137 127.704 ;
     RECT  0.06 127.704 0.137 128.448 ;
     RECT  0.084 128.448 0.137 128.472 ;
     RECT  0.06 128.472 0.137 129.264 ;
     RECT  0.084 129.264 0.137 129.288 ;
     RECT  0.06 129.288 0.137 130.032 ;
     RECT  0.084 130.032 0.137 130.056 ;
     RECT  0.06 130.056 0.137 130.8 ;
     RECT  0.084 130.8 0.137 130.824 ;
     RECT  0.06 130.824 0.137 131.568 ;
     RECT  0.084 131.568 0.137 131.592 ;
     RECT  0.06 131.592 0.137 132.336 ;
     RECT  0.084 132.336 0.137 132.36 ;
     RECT  0.06 132.36 0.137 133.152 ;
     RECT  0.084 133.152 0.137 133.176 ;
     RECT  0.06 133.176 0.137 133.92 ;
     RECT  0.084 133.92 0.137 133.944 ;
     RECT  0.06 133.944 0.137 134.688 ;
     RECT  0.084 134.688 0.137 134.712 ;
     RECT  0.06 134.712 0.137 135.456 ;
     RECT  0.084 135.456 0.137 135.48 ;
     RECT  0.06 135.48 0.137 136.224 ;
     RECT  0.084 136.224 0.137 136.248 ;
     RECT  0.06 136.248 0.137 137.04 ;
     RECT  0.084 137.04 0.137 137.064 ;
     RECT  0.06 137.064 0.137 137.808 ;
     RECT  0.084 137.808 0.137 137.832 ;
     RECT  0.06 137.832 0.137 138.576 ;
     RECT  0.084 138.576 0.137 138.6 ;
     RECT  0.06 138.6 0.137 139.344 ;
     RECT  0.084 139.344 0.137 139.368 ;
     RECT  0.06 139.368 0.137 140.112 ;
     RECT  0.084 140.112 0.137 140.136 ;
     RECT  0.06 140.136 0.137 140.928 ;
     RECT  0.084 140.928 0.137 140.952 ;
     RECT  0.06 140.952 0.137 141.696 ;
     RECT  0.084 141.696 0.137 141.72 ;
     RECT  0.06 141.72 0.137 142.464 ;
     RECT  0.084 142.464 0.137 142.488 ;
     RECT  0.06 142.488 0.137 143.232 ;
     RECT  0.084 143.232 0.137 143.256 ;
     RECT  0.137 26.64 0.569 32.856 ;
     RECT  0.137 58.512 0.569 63.192 ;
     RECT  0.137 79.488 0.569 88.056 ;
     RECT  0.137 123.024 0.569 133.944 ;
     RECT  0.137 135.456 0.569 140.952 ;
     RECT  0.569 123.024 1.181 129.288 ;
     RECT  0.137 2.544 2.408 3.336 ;
     RECT  0.137 4.848 2.408 10.344 ;
     RECT  0.137 11.856 2.408 22.776 ;
     RECT  0.137 24.288 2.408 25.128 ;
     RECT  0.569 26.64 2.408 26.664 ;
     RECT  0.569 28.176 2.408 32.856 ;
     RECT  0.137 34.416 2.408 44.52 ;
     RECT  0.137 46.08 2.408 56.904 ;
     RECT  0.569 58.512 2.408 58.536 ;
     RECT  0.569 60.048 2.408 63.192 ;
     RECT  0.137 64.704 2.408 68.616 ;
     RECT  0.137 70.176 2.408 77.976 ;
     RECT  0.569 79.488 2.408 84.168 ;
     RECT  0.569 85.728 2.408 88.056 ;
     RECT  0.137 89.616 2.408 99.72 ;
     RECT  0.137 102.048 2.408 106.728 ;
     RECT  0.137 108.24 2.408 119.16 ;
     RECT  0.137 120.72 2.408 121.512 ;
     RECT  1.181 123.024 2.408 129.192 ;
     RECT  0.569 130.8 2.408 133.944 ;
     RECT  0.569 135.456 2.408 135.48 ;
     RECT  0.569 137.04 2.408 140.952 ;
     RECT  0.137 142.464 2.408 143.256 ;
     RECT  2.408 2.148 2.512 144.732 ;
     RECT  2.512 2.418 2.704 144.462 ;
     RECT  2.704 84.144 2.765 84.168 ;
     RECT  2.704 96.576 2.801 98.184 ;
     RECT  2.704 103.584 2.801 104.904 ;
     RECT  2.704 19.632 2.837 20.424 ;
     RECT  2.704 38.736 2.837 43.176 ;
     RECT  2.704 60.048 2.837 61.656 ;
     RECT  2.704 81.072 2.837 81.096 ;
     RECT  2.704 93.456 2.837 93.528 ;
     RECT  2.801 96.576 2.837 96.6 ;
     RECT  2.704 105.936 2.837 106.728 ;
     RECT  2.704 112.128 2.837 113.736 ;
     RECT  2.704 135.456 2.837 135.48 ;
     RECT  2.704 137.184 2.837 138.6 ;
     RECT  2.837 38.736 3.395 40.632 ;
     RECT  2.704 116.016 3.491 119.16 ;
     RECT  2.704 9.504 3.683 9.528 ;
     RECT  2.704 120.768 3.683 121.464 ;
     RECT  2.704 46.416 3.921 46.44 ;
     RECT  2.704 47.568 3.921 48.408 ;
     RECT  2.704 11.952 3.925 11.976 ;
     RECT  3.925 11.952 3.971 12.936 ;
     RECT  2.704 15.36 3.971 15.912 ;
     RECT  2.837 60.048 3.98 60.84 ;
     RECT  2.837 20.4 4.021 20.424 ;
     RECT  3.98 59.232 4.021 60.84 ;
     RECT  2.704 4.8 4.025 5.736 ;
     RECT  2.704 14.208 4.025 14.232 ;
     RECT  2.704 17.328 4.025 18.168 ;
     RECT  4.021 19.92 4.025 20.424 ;
     RECT  2.704 31.344 4.025 32.856 ;
     RECT  3.395 38.736 4.025 39.096 ;
     RECT  2.704 51.648 4.025 51.672 ;
     RECT  2.704 56.88 4.025 56.904 ;
     RECT  4.021 59.232 4.025 61.8 ;
     RECT  2.704 66.288 4.025 67.8 ;
     RECT  2.704 82.56 4.025 82.584 ;
     RECT  2.801 98.16 4.025 98.184 ;
     RECT  3.491 116.016 4.025 117.48 ;
     RECT  2.704 123.024 4.025 123.72 ;
     RECT  2.704 131.568 4.025 132.456 ;
     RECT  2.704 7.2 4.061 7.992 ;
     RECT  3.395 40.608 4.061 40.632 ;
     RECT  3.683 121.44 4.061 121.464 ;
     RECT  2.704 22.752 4.097 22.776 ;
     RECT  4.025 116.016 4.097 116.04 ;
     RECT  2.704 54.624 4.129 54.648 ;
     RECT  4.025 123.696 4.129 123.72 ;
     RECT  2.704 126.144 4.129 126.168 ;
     RECT  2.837 138.576 4.213 138.6 ;
     RECT  2.704 140.208 4.213 140.232 ;
     RECT  2.704 29.76 4.245 29.784 ;
     RECT  4.025 31.344 4.245 32.088 ;
     RECT  4.021 21.456 4.261 21.48 ;
     RECT  4.22 33.504 4.261 33.528 ;
     RECT  2.704 35.184 4.261 35.976 ;
     RECT  2.704 79.488 4.268 79.512 ;
     RECT  2.704 91.152 4.268 91.944 ;
     RECT  2.837 93.456 4.268 93.48 ;
     RECT  2.704 110.592 4.268 110.616 ;
     RECT  2.837 112.944 4.273 113.736 ;
     RECT  4.261 33.504 4.309 35.976 ;
     RECT  3.921 46.416 4.309 48.408 ;
     RECT  4.261 49.392 4.309 49.416 ;
     RECT  4.268 64.944 4.309 64.968 ;
     RECT  2.704 70.128 4.309 70.152 ;
     RECT  2.704 75.648 4.309 76.488 ;
     RECT  4.268 77.472 4.309 77.496 ;
     RECT  2.837 137.184 4.309 137.208 ;
     RECT  4.213 138.576 4.309 140.232 ;
     RECT  4.261 21.36 4.373 21.48 ;
     RECT  2.704 129.168 4.381 129.192 ;
     RECT  4.129 54.624 4.405 55.512 ;
     RECT  4.129 123.696 4.405 124.824 ;
     RECT  2.704 26.64 4.412 26.664 ;
     RECT  2.704 28.08 4.412 28.104 ;
     RECT  4.025 18.144 4.481 18.168 ;
     RECT  2.704 2.688 4.501 2.712 ;
     RECT  4.025 5.712 4.501 5.736 ;
     RECT  4.061 7.2 4.501 7.224 ;
     RECT  3.971 15.888 4.501 15.912 ;
     RECT  2.801 104.352 4.501 104.904 ;
     RECT  4.273 112.944 4.501 114.552 ;
     RECT  4.381 129.168 4.501 129.96 ;
     RECT  4.405 54.624 4.517 55.608 ;
     RECT  4.309 81.456 4.625 81.48 ;
     RECT  2.704 89.856 4.669 89.88 ;
     RECT  4.268 91.152 4.669 93.48 ;
     RECT  4.669 89.856 4.705 93.48 ;
     RECT  4.268 96.096 5.029 96.12 ;
     RECT  4.309 97.392 5.029 97.416 ;
     RECT  4.213 142.512 5.101 142.536 ;
     RECT  4.501 2.688 5.108 3.288 ;
     RECT  4.501 5.712 5.108 7.224 ;
     RECT  4.309 8.64 5.108 8.664 ;
     RECT  3.971 12.912 5.108 12.936 ;
     RECT  4.501 15.888 5.108 16.68 ;
     RECT  4.481 18.144 5.108 18.84 ;
     RECT  4.025 19.92 5.108 19.944 ;
     RECT  4.373 21.36 5.108 22.2 ;
     RECT  4.273 24.384 5.108 24.504 ;
     RECT  4.412 26.64 5.108 28.104 ;
     RECT  4.245 29.76 5.108 32.088 ;
     RECT  4.309 33.504 5.108 36.504 ;
     RECT  4.025 38.736 5.108 38.76 ;
     RECT  2.837 42.192 5.108 43.176 ;
     RECT  4.645 44.736 5.108 44.76 ;
     RECT  4.309 46.416 5.108 49.416 ;
     RECT  4.261 50.976 5.108 51 ;
     RECT  4.22 52.32 5.108 52.344 ;
     RECT  4.261 53.568 5.108 53.592 ;
     RECT  4.517 54.576 5.108 55.608 ;
     RECT  4.165 57.024 5.108 57.048 ;
     RECT  4.025 59.232 5.108 59.256 ;
     RECT  4.025 60.816 5.108 61.8 ;
     RECT  4.309 63.216 5.108 63.24 ;
     RECT  4.309 64.944 5.108 65.832 ;
     RECT  4.025 67.056 5.108 67.8 ;
     RECT  4.309 70.128 5.108 70.728 ;
     RECT  2.704 72.48 5.108 73.32 ;
     RECT  4.309 75.024 5.108 76.488 ;
     RECT  4.309 77.472 5.108 77.976 ;
     RECT  4.268 79.488 5.108 80.232 ;
     RECT  4.625 81.456 5.108 82.056 ;
     RECT  4.309 83.76 5.108 83.784 ;
     RECT  2.704 85.728 5.108 86.616 ;
     RECT  4.705 88.896 5.108 93.48 ;
     RECT  2.704 95.088 5.108 95.112 ;
     RECT  5.029 96.096 5.108 97.416 ;
     RECT  2.704 99.168 5.108 99.192 ;
     RECT  4.268 102.048 5.108 102.072 ;
     RECT  4.501 103.104 5.108 104.904 ;
     RECT  2.837 106.704 5.108 106.728 ;
     RECT  4.309 109.296 5.108 109.32 ;
     RECT  4.268 110.592 5.108 111.288 ;
     RECT  4.501 112.944 5.108 115.32 ;
     RECT  4.025 117.456 5.108 117.48 ;
     RECT  3.491 119.136 5.108 119.16 ;
     RECT  4.405 123.696 5.108 124.968 ;
     RECT  4.129 126.144 5.108 127.416 ;
     RECT  4.501 128.736 5.108 129.96 ;
     RECT  4.025 131.568 5.108 131.592 ;
     RECT  4.271 133.104 5.108 133.128 ;
     RECT  4.237 136.128 5.108 136.152 ;
     RECT  4.309 137.184 5.108 140.232 ;
     RECT  5.101 142.512 5.108 143.208 ;
     RECT  5.108 2.148 5.212 144.732 ;
     RECT  5.212 2.418 5.404 144.462 ;
     RECT  5.404 60.816 5.465 60.84 ;
     RECT  5.404 77.952 5.465 78.12 ;
     RECT  5.404 138.576 5.573 138.6 ;
     RECT  5.404 107.76 5.603 108.072 ;
     RECT  5.404 81.456 5.609 81.48 ;
     RECT  5.404 124.464 5.651 125.352 ;
     RECT  5.404 126.384 5.651 126.552 ;
     RECT  5.404 127.968 5.651 127.992 ;
     RECT  5.404 130.896 5.651 131.592 ;
     RECT  5.404 134.16 5.651 134.184 ;
     RECT  5.404 53.184 5.699 53.208 ;
     RECT  5.404 54.576 5.699 57.576 ;
     RECT  5.404 84.336 5.699 84.936 ;
     RECT  5.404 86.592 5.699 87.24 ;
     RECT  5.404 89.952 5.699 90.696 ;
     RECT  5.404 105.984 5.699 106.776 ;
     RECT  5.404 72.384 5.717 73.32 ;
     RECT  5.404 25.344 5.747 26.232 ;
     RECT  5.404 121.488 5.747 121.512 ;
     RECT  5.404 143.184 5.747 143.208 ;
     RECT  5.404 75.792 5.789 75.816 ;
     RECT  5.651 131.568 5.789 131.592 ;
     RECT  5.404 10.32 5.795 10.344 ;
     RECT  5.404 40.752 5.795 42.36 ;
     RECT  5.699 84.912 5.825 84.936 ;
     RECT  5.603 108.048 5.843 108.072 ;
     RECT  5.651 124.8 5.843 125.352 ;
     RECT  5.404 140.976 5.891 141 ;
     RECT  5.404 22.752 5.987 23.736 ;
     RECT  5.717 72.384 5.987 72.936 ;
     RECT  5.987 23.712 6.005 23.736 ;
     RECT  5.404 38.736 6.005 39.288 ;
     RECT  5.699 54.576 6.005 55.512 ;
     RECT  5.404 119.904 6.005 119.928 ;
     RECT  5.404 135.456 6.005 135.48 ;
     RECT  5.987 72.384 6.041 72.84 ;
     RECT  5.404 109.968 6.083 110.904 ;
     RECT  5.404 116.208 6.083 116.232 ;
     RECT  5.699 89.952 6.131 90.6 ;
     RECT  5.404 17.328 6.275 17.352 ;
     RECT  5.404 7.392 6.329 7.416 ;
     RECT  5.465 78.096 6.329 78.12 ;
     RECT  5.843 125.328 6.365 125.352 ;
     RECT  6.005 55.056 6.508 55.512 ;
     RECT  5.699 57.024 6.545 57.576 ;
     RECT  6.508 55.392 6.573 55.512 ;
     RECT  5.747 26.208 6.581 26.232 ;
     RECT  5.404 21.456 6.753 21.48 ;
     RECT  5.651 126.384 6.805 126.408 ;
     RECT  5.404 68.784 6.829 68.808 ;
     RECT  6.505 122.544 6.829 122.568 ;
     RECT  5.404 19.92 6.853 20.232 ;
     RECT  6.829 29.04 6.853 29.064 ;
     RECT  5.404 91.872 6.853 91.896 ;
     RECT  6.764 125.376 6.853 125.4 ;
     RECT  6.805 126.384 6.853 126.648 ;
     RECT  6.853 125.376 6.937 126.648 ;
     RECT  5.404 66.672 6.997 66.696 ;
     RECT  6.829 13.632 7.004 13.656 ;
     RECT  6.829 68.784 7.004 69.528 ;
     RECT  6.853 19.92 7.045 20.472 ;
     RECT  5.404 100.512 7.045 100.536 ;
     RECT  6.545 57.552 7.369 57.576 ;
     RECT  6.829 60.096 7.381 60.12 ;
     RECT  6.131 89.952 7.477 89.976 ;
     RECT  6.041 72.384 7.621 72.408 ;
     RECT  7.004 5.04 7.808 5.064 ;
     RECT  7.004 8.304 7.808 8.328 ;
     RECT  7.004 11.136 7.808 11.16 ;
     RECT  7.004 13.632 7.808 14.376 ;
     RECT  7.045 19.824 7.808 21.144 ;
     RECT  6.829 25.968 7.808 25.992 ;
     RECT  6.853 29.04 7.808 29.784 ;
     RECT  7.585 32.784 7.808 32.808 ;
     RECT  6.517 38.4 7.808 38.424 ;
     RECT  5.795 42.336 7.808 42.36 ;
     RECT  5.404 43.872 7.808 43.896 ;
     RECT  6.853 45.552 7.808 45.576 ;
     RECT  7.004 48.384 7.808 48.408 ;
     RECT  5.404 50.112 7.808 50.136 ;
     RECT  5.404 51.648 7.808 51.672 ;
     RECT  6.573 55.392 7.808 55.416 ;
     RECT  7.369 57.552 7.808 58.152 ;
     RECT  7.381 60.096 7.808 60.84 ;
     RECT  5.404 62.592 7.808 62.616 ;
     RECT  7.004 64.032 7.808 64.056 ;
     RECT  6.997 66.672 7.808 67.176 ;
     RECT  7.004 68.784 7.808 70.44 ;
     RECT  7.621 72.384 7.808 73.368 ;
     RECT  7.045 79.44 7.808 79.464 ;
     RECT  7.585 85.776 7.808 85.8 ;
     RECT  7.477 89.952 7.808 90.072 ;
     RECT  6.853 91.872 7.808 92.328 ;
     RECT  6.829 94.272 7.808 95.16 ;
     RECT  7.004 98.496 7.808 98.52 ;
     RECT  7.045 100.512 7.808 101.16 ;
     RECT  5.699 106.752 7.808 106.776 ;
     RECT  7.045 113.856 7.808 113.88 ;
     RECT  7.004 116.976 7.808 117 ;
     RECT  6.829 119.232 7.808 119.256 ;
     RECT  6.829 122.352 7.808 122.568 ;
     RECT  6.937 125.376 7.808 126.984 ;
     RECT  7.004 129.552 7.808 129.576 ;
     RECT  7.045 132.48 7.808 132.504 ;
     RECT  7.004 134.784 7.808 134.808 ;
     RECT  7.004 138.72 7.808 138.744 ;
     RECT  7.045 141.36 7.808 141.384 ;
     RECT  7.808 2.148 7.912 144.732 ;
     RECT  7.912 2.418 8.104 144.462 ;
     RECT  8.104 45.552 8.165 45.576 ;
     RECT  8.104 51.648 8.165 51.672 ;
     RECT  8.104 60.816 8.165 60.84 ;
     RECT  8.104 113.856 8.165 113.88 ;
     RECT  8.104 132.48 8.165 132.504 ;
     RECT  8.104 141.36 8.165 141.384 ;
     RECT  8.104 29.76 8.243 29.784 ;
     RECT  8.104 32.784 8.243 32.808 ;
     RECT  8.104 36 8.243 36.024 ;
     RECT  8.104 73.344 8.243 73.368 ;
     RECT  8.104 76.608 8.243 76.632 ;
     RECT  8.104 79.44 8.243 79.464 ;
     RECT  8.104 82.8 8.243 82.824 ;
     RECT  8.104 85.776 8.243 85.8 ;
     RECT  8.104 88.896 8.243 89.544 ;
     RECT  8.104 101.136 8.243 101.16 ;
     RECT  8.104 104.688 8.243 104.712 ;
     RECT  8.104 106.752 8.243 107.304 ;
     RECT  10.508 2.148 10.612 144.732 ;
     RECT  10.612 2.418 10.804 144.462 ;
     RECT  5.941 146.736 10.829 146.76 ;
     RECT  10.804 31.968 11.833 31.992 ;
     RECT  11.941 5.568 13.208 5.592 ;
     RECT  10.804 14.208 13.208 14.232 ;
     RECT  11.833 31.152 13.208 31.992 ;
     RECT  10.804 33.648 13.208 33.672 ;
     RECT  10.804 42.192 13.208 42.216 ;
     RECT  10.804 46.08 13.208 46.104 ;
     RECT  10.804 56.88 13.208 56.904 ;
     RECT  10.804 59.28 13.208 59.304 ;
     RECT  10.804 65.52 13.208 65.544 ;
     RECT  11.941 67.824 13.208 67.848 ;
     RECT  10.804 78.72 13.208 78.744 ;
     RECT  10.804 82.464 13.208 82.488 ;
     RECT  10.804 93.504 13.208 93.528 ;
     RECT  10.804 119.136 13.208 119.16 ;
     RECT  11.941 130.032 13.208 130.056 ;
     RECT  10.804 133.824 13.208 133.848 ;
     RECT  10.804 136.224 13.208 136.248 ;
     RECT  10.804 142.464 13.208 142.488 ;
     RECT  13.208 2.148 13.312 144.732 ;
     RECT  13.312 2.418 13.504 144.462 ;
     RECT  13.504 31.152 14.713 31.992 ;
     RECT  13.504 82.56 14.821 82.584 ;
     RECT  14.713 31.152 14.861 32.088 ;
     RECT  14.821 82.464 14.861 82.584 ;
     RECT  13.504 5.568 15.908 5.592 ;
     RECT  13.504 14.208 15.908 14.232 ;
     RECT  14.861 31.152 15.908 31.992 ;
     RECT  13.504 33.648 15.908 33.672 ;
     RECT  13.504 42.192 15.908 42.216 ;
     RECT  13.504 46.08 15.908 46.104 ;
     RECT  13.504 56.88 15.908 56.904 ;
     RECT  13.504 59.28 15.908 59.304 ;
     RECT  13.504 65.52 15.908 65.544 ;
     RECT  13.504 67.824 15.908 67.848 ;
     RECT  13.504 78.72 15.908 78.744 ;
     RECT  14.861 82.464 15.908 82.488 ;
     RECT  13.504 93.504 15.908 93.528 ;
     RECT  13.504 119.136 15.908 119.16 ;
     RECT  13.504 130.032 15.908 130.056 ;
     RECT  13.504 133.824 15.908 133.848 ;
     RECT  13.504 136.224 15.908 136.248 ;
     RECT  13.504 142.464 15.908 142.488 ;
     RECT  15.908 2.148 16.012 144.732 ;
     RECT  16.012 2.418 16.204 144.462 ;
     RECT  18.205 4.176 18.608 4.2 ;
     RECT  16.204 5.568 18.608 5.592 ;
     RECT  16.204 14.208 18.608 14.232 ;
     RECT  16.204 31.152 18.608 31.992 ;
     RECT  16.204 33.648 18.608 33.672 ;
     RECT  16.204 42.192 18.608 42.216 ;
     RECT  16.204 46.08 18.608 46.104 ;
     RECT  16.204 56.88 18.608 56.904 ;
     RECT  16.204 59.28 18.608 59.304 ;
     RECT  16.204 65.52 18.608 65.544 ;
     RECT  16.204 67.824 18.608 67.848 ;
     RECT  16.204 78.72 18.608 78.744 ;
     RECT  16.204 82.464 18.608 82.488 ;
     RECT  16.204 84.96 18.608 84.984 ;
     RECT  16.204 93.504 18.608 93.528 ;
     RECT  16.204 119.136 18.608 119.16 ;
     RECT  16.204 130.032 18.608 130.056 ;
     RECT  16.204 133.824 18.608 133.848 ;
     RECT  16.204 136.224 18.608 136.248 ;
     RECT  16.204 142.464 18.608 142.488 ;
     RECT  18.608 2.148 18.712 144.732 ;
     RECT  18.712 2.418 18.904 144.462 ;
     RECT  18.904 5.568 19.897 5.592 ;
     RECT  18.904 140.112 19.897 140.136 ;
     RECT  18.904 141.696 19.897 142.488 ;
     RECT  18.904 31.152 19.933 31.992 ;
     RECT  18.904 33.648 19.933 33.672 ;
     RECT  18.904 93.504 19.933 93.528 ;
     RECT  19.897 140.112 19.933 142.488 ;
     RECT  18.904 4.176 20.473 4.2 ;
     RECT  19.897 5.568 20.473 6.456 ;
     RECT  19.933 15.744 20.473 17.352 ;
     RECT  19.933 21.216 20.473 22.776 ;
     RECT  19.933 31.152 20.473 34.44 ;
     RECT  19.933 80.256 20.473 81.096 ;
     RECT  18.904 82.464 20.473 82.488 ;
     RECT  19.933 91.92 20.473 94.296 ;
     RECT  19.933 98.928 20.473 99.72 ;
     RECT  19.933 105.168 20.473 106.728 ;
     RECT  18.904 116.832 20.473 116.856 ;
     RECT  18.904 133.824 20.473 133.848 ;
     RECT  18.904 136.224 20.473 136.248 ;
     RECT  20.473 4.176 20.509 6.456 ;
     RECT  20.473 11.088 20.509 12.648 ;
     RECT  18.904 14.208 20.509 14.232 ;
     RECT  20.473 15.744 20.509 18.12 ;
     RECT  19.933 19.632 20.509 19.656 ;
     RECT  20.473 21.216 20.509 25.128 ;
     RECT  19.933 26.64 20.509 26.664 ;
     RECT  19.933 28.944 20.509 28.968 ;
     RECT  20.473 30.528 20.509 34.44 ;
     RECT  18.904 42.192 20.509 42.216 ;
     RECT  18.904 46.08 20.509 46.104 ;
     RECT  18.904 59.28 20.509 59.304 ;
     RECT  18.904 65.52 20.509 65.544 ;
     RECT  18.904 67.824 20.509 67.848 ;
     RECT  18.904 78.72 20.509 78.744 ;
     RECT  20.473 80.256 20.509 82.488 ;
     RECT  18.904 84.96 20.509 84.984 ;
     RECT  19.933 86.496 20.509 86.52 ;
     RECT  20.473 88.032 20.509 88.056 ;
     RECT  20.473 89.616 20.509 90.408 ;
     RECT  20.473 91.92 20.509 95.832 ;
     RECT  20.473 98.16 20.509 99.72 ;
     RECT  20.473 115.248 20.509 116.856 ;
     RECT  18.904 119.136 20.509 119.16 ;
     RECT  20.473 121.488 20.509 122.28 ;
     RECT  19.933 123.792 20.509 123.816 ;
     RECT  19.933 126.144 20.509 126.168 ;
     RECT  18.904 130.032 20.509 130.056 ;
     RECT  20.473 133.824 20.509 136.248 ;
     RECT  19.933 137.808 20.509 137.832 ;
     RECT  20.509 2.544 21.481 7.224 ;
     RECT  20.509 8.736 21.481 12.648 ;
     RECT  20.509 14.208 21.481 18.12 ;
     RECT  20.509 19.632 21.481 25.128 ;
     RECT  20.509 26.64 21.481 35.976 ;
     RECT  20.509 39.84 21.481 42.216 ;
     RECT  20.509 46.08 21.481 49.224 ;
     RECT  20.509 52.272 21.481 52.296 ;
     RECT  20.509 54.624 21.481 55.416 ;
     RECT  18.904 56.88 21.481 57.768 ;
     RECT  20.509 59.28 21.481 61.656 ;
     RECT  20.509 65.52 21.481 67.848 ;
     RECT  20.509 71.712 21.481 74.856 ;
     RECT  20.509 77.952 21.481 82.488 ;
     RECT  20.509 84.144 21.481 88.056 ;
     RECT  20.509 89.616 21.481 99.72 ;
     RECT  20.473 102.816 21.481 102.84 ;
     RECT  20.473 104.352 21.481 106.728 ;
     RECT  18.904 108.24 21.481 108.264 ;
     RECT  20.509 111.36 21.481 113.736 ;
     RECT  20.509 115.248 21.481 119.16 ;
     RECT  20.509 121.488 21.481 126.168 ;
     RECT  20.509 130.032 21.481 136.248 ;
     RECT  20.509 137.808 21.481 138.6 ;
     RECT  19.933 140.112 21.481 143.256 ;
     RECT  21.481 2.544 21.516 2.568 ;
     RECT  21.481 2.568 21.564 3.312 ;
     RECT  21.481 3.312 21.516 3.336 ;
     RECT  21.481 3.336 21.564 4.08 ;
     RECT  21.481 4.08 21.516 4.104 ;
     RECT  21.481 4.104 21.564 4.848 ;
     RECT  21.481 4.848 21.516 4.872 ;
     RECT  21.481 4.872 21.564 5.664 ;
     RECT  21.481 5.664 21.516 5.688 ;
     RECT  21.481 5.688 21.564 6.432 ;
     RECT  21.481 6.432 21.516 6.456 ;
     RECT  21.481 6.456 21.564 7.2 ;
     RECT  21.481 7.2 21.516 7.224 ;
     RECT  21.481 7.224 21.564 7.968 ;
     RECT  21.481 7.968 21.516 7.992 ;
     RECT  21.481 7.992 21.564 8.736 ;
     RECT  21.481 8.736 21.516 8.76 ;
     RECT  21.481 8.76 21.564 9.552 ;
     RECT  21.481 9.552 21.516 9.576 ;
     RECT  21.481 9.576 21.564 10.32 ;
     RECT  21.481 10.32 21.516 10.344 ;
     RECT  21.481 10.344 21.564 11.088 ;
     RECT  21.481 11.088 21.516 11.112 ;
     RECT  21.481 11.112 21.564 11.856 ;
     RECT  21.481 11.856 21.516 11.88 ;
     RECT  21.481 11.88 21.564 12.624 ;
     RECT  21.481 12.624 21.516 12.648 ;
     RECT  21.481 12.648 21.564 13.44 ;
     RECT  21.481 13.44 21.516 13.464 ;
     RECT  21.481 13.464 21.564 14.208 ;
     RECT  21.481 14.208 21.516 14.232 ;
     RECT  21.481 14.232 21.564 14.976 ;
     RECT  21.481 14.976 21.516 15 ;
     RECT  21.481 15 21.564 15.744 ;
     RECT  21.481 15.744 21.516 15.768 ;
     RECT  21.481 15.768 21.564 16.512 ;
     RECT  21.481 16.512 21.516 16.536 ;
     RECT  21.481 16.536 21.564 17.328 ;
     RECT  21.481 17.328 21.516 17.352 ;
     RECT  21.481 17.352 21.564 18.096 ;
     RECT  21.481 18.096 21.516 18.12 ;
     RECT  21.481 18.12 21.564 18.864 ;
     RECT  21.481 18.864 21.516 18.888 ;
     RECT  21.481 18.888 21.564 19.632 ;
     RECT  21.481 19.632 21.516 19.656 ;
     RECT  21.481 19.656 21.564 20.4 ;
     RECT  21.481 20.4 21.516 20.424 ;
     RECT  21.481 20.424 21.564 21.216 ;
     RECT  21.481 21.216 21.516 21.24 ;
     RECT  21.481 21.24 21.564 21.984 ;
     RECT  21.481 21.984 21.516 22.008 ;
     RECT  21.481 22.008 21.564 22.752 ;
     RECT  21.481 22.752 21.516 22.776 ;
     RECT  21.481 22.776 21.564 23.52 ;
     RECT  21.481 23.52 21.516 23.544 ;
     RECT  21.481 23.544 21.564 24.288 ;
     RECT  21.481 24.288 21.516 24.312 ;
     RECT  21.481 24.312 21.564 25.104 ;
     RECT  21.481 25.104 21.516 25.128 ;
     RECT  21.481 25.128 21.564 25.872 ;
     RECT  21.481 25.872 21.516 25.896 ;
     RECT  21.481 25.896 21.564 26.64 ;
     RECT  21.481 26.64 21.516 26.664 ;
     RECT  21.481 26.664 21.564 27.408 ;
     RECT  21.481 27.408 21.516 27.432 ;
     RECT  21.481 27.432 21.564 28.176 ;
     RECT  21.481 28.176 21.516 28.2 ;
     RECT  21.481 28.2 21.564 28.944 ;
     RECT  21.481 28.944 21.516 28.968 ;
     RECT  21.481 28.968 21.564 29.76 ;
     RECT  21.481 29.76 21.516 29.784 ;
     RECT  21.481 29.784 21.564 30.528 ;
     RECT  21.481 30.528 21.516 30.552 ;
     RECT  21.481 30.552 21.564 31.296 ;
     RECT  21.481 31.296 21.516 31.32 ;
     RECT  21.481 31.32 21.564 32.064 ;
     RECT  21.481 32.064 21.516 32.088 ;
     RECT  21.481 32.088 21.564 32.832 ;
     RECT  21.481 32.832 21.516 32.856 ;
     RECT  21.481 32.856 21.564 33.648 ;
     RECT  21.481 33.648 21.516 33.672 ;
     RECT  21.481 33.672 21.564 34.416 ;
     RECT  21.481 34.416 21.516 34.44 ;
     RECT  21.481 34.44 21.564 35.184 ;
     RECT  21.481 35.184 21.516 35.208 ;
     RECT  21.481 35.208 21.564 35.952 ;
     RECT  21.481 35.952 21.516 35.976 ;
     RECT  21.481 35.976 21.564 36.72 ;
     RECT  21.481 36.72 21.516 36.744 ;
     RECT  21.481 36.744 21.564 37.536 ;
     RECT  21.481 37.536 21.516 37.56 ;
     RECT  21.481 37.56 21.564 38.304 ;
     RECT  21.481 38.304 21.516 38.328 ;
     RECT  21.481 38.328 21.564 39.072 ;
     RECT  21.481 39.072 21.516 39.096 ;
     RECT  21.481 39.096 21.564 39.84 ;
     RECT  21.481 39.84 21.516 39.864 ;
     RECT  21.481 39.864 21.564 40.608 ;
     RECT  21.481 40.608 21.516 40.632 ;
     RECT  21.481 40.632 21.564 41.424 ;
     RECT  21.481 41.424 21.516 41.448 ;
     RECT  21.481 41.448 21.564 42.192 ;
     RECT  21.481 42.192 21.516 42.216 ;
     RECT  21.481 42.216 21.564 42.96 ;
     RECT  21.481 42.96 21.516 42.984 ;
     RECT  21.481 42.984 21.564 43.728 ;
     RECT  21.481 43.728 21.516 43.752 ;
     RECT  21.481 43.752 21.564 44.496 ;
     RECT  21.481 44.496 21.516 44.52 ;
     RECT  21.481 44.52 21.564 45.312 ;
     RECT  21.481 45.312 21.516 45.336 ;
     RECT  21.481 45.336 21.564 46.08 ;
     RECT  21.481 46.08 21.516 46.104 ;
     RECT  21.481 46.104 21.564 46.848 ;
     RECT  21.481 46.848 21.516 46.872 ;
     RECT  21.481 46.872 21.564 47.616 ;
     RECT  21.481 47.616 21.516 47.64 ;
     RECT  21.481 47.64 21.564 48.384 ;
     RECT  21.481 48.384 21.516 48.408 ;
     RECT  21.481 48.408 21.564 49.2 ;
     RECT  21.481 49.2 21.516 49.224 ;
     RECT  21.481 49.224 21.564 49.968 ;
     RECT  21.481 49.968 21.516 49.992 ;
     RECT  21.481 49.992 21.564 50.736 ;
     RECT  21.481 50.736 21.516 50.76 ;
     RECT  21.481 50.76 21.564 51.504 ;
     RECT  21.481 51.504 21.516 51.528 ;
     RECT  21.481 51.528 21.564 52.272 ;
     RECT  21.481 52.272 21.516 52.296 ;
     RECT  21.481 52.296 21.564 53.088 ;
     RECT  21.481 53.088 21.516 53.112 ;
     RECT  21.481 53.112 21.564 53.856 ;
     RECT  21.481 53.856 21.516 53.88 ;
     RECT  21.481 53.88 21.564 54.624 ;
     RECT  21.481 54.624 21.516 54.648 ;
     RECT  21.481 54.648 21.564 55.392 ;
     RECT  21.481 55.392 21.516 55.416 ;
     RECT  21.481 55.416 21.564 56.16 ;
     RECT  21.481 56.16 21.516 56.184 ;
     RECT  21.481 56.184 21.564 56.976 ;
     RECT  21.481 56.976 21.516 57 ;
     RECT  21.481 57 21.564 57.744 ;
     RECT  21.481 57.744 21.516 57.768 ;
     RECT  21.481 57.768 21.564 58.512 ;
     RECT  21.481 58.512 21.516 58.536 ;
     RECT  21.481 58.536 21.564 59.28 ;
     RECT  21.481 59.28 21.516 59.304 ;
     RECT  21.481 59.304 21.564 60.048 ;
     RECT  21.481 60.048 21.516 60.072 ;
     RECT  21.481 60.072 21.564 60.816 ;
     RECT  21.481 60.816 21.516 60.84 ;
     RECT  21.481 60.84 21.564 61.632 ;
     RECT  21.481 61.632 21.516 61.656 ;
     RECT  21.481 61.656 21.564 62.4 ;
     RECT  21.481 62.4 21.516 62.424 ;
     RECT  21.481 62.424 21.564 63.168 ;
     RECT  21.481 63.168 21.516 63.192 ;
     RECT  21.481 63.192 21.564 63.936 ;
     RECT  21.481 63.936 21.516 63.96 ;
     RECT  21.481 63.96 21.564 64.704 ;
     RECT  21.481 64.704 21.516 64.728 ;
     RECT  21.481 64.728 21.564 65.52 ;
     RECT  21.481 65.52 21.516 65.544 ;
     RECT  21.481 65.544 21.564 66.288 ;
     RECT  21.481 66.288 21.516 66.312 ;
     RECT  21.481 66.312 21.564 67.056 ;
     RECT  21.481 67.056 21.516 67.08 ;
     RECT  21.481 67.08 21.564 67.824 ;
     RECT  21.481 67.824 21.516 67.848 ;
     RECT  21.481 67.848 21.564 68.592 ;
     RECT  21.481 68.592 21.516 68.616 ;
     RECT  21.481 68.616 21.564 69.408 ;
     RECT  21.481 69.408 21.516 69.432 ;
     RECT  21.481 69.432 21.564 70.176 ;
     RECT  21.481 70.176 21.516 70.2 ;
     RECT  21.481 70.2 21.564 70.944 ;
     RECT  21.481 70.944 21.516 70.968 ;
     RECT  21.481 70.968 21.564 71.712 ;
     RECT  21.481 71.712 21.516 71.736 ;
     RECT  21.481 71.736 21.564 72.48 ;
     RECT  21.481 72.48 21.516 72.504 ;
     RECT  21.481 72.504 21.564 73.296 ;
     RECT  21.481 73.296 21.516 73.32 ;
     RECT  21.481 73.32 21.564 74.064 ;
     RECT  21.481 74.064 21.516 74.088 ;
     RECT  21.481 74.088 21.564 74.832 ;
     RECT  21.481 74.832 21.516 74.856 ;
     RECT  21.481 74.856 21.564 75.6 ;
     RECT  21.481 75.6 21.516 75.624 ;
     RECT  21.481 75.624 21.564 76.368 ;
     RECT  21.481 76.368 21.516 76.392 ;
     RECT  21.481 76.392 21.564 77.184 ;
     RECT  21.481 77.184 21.516 77.208 ;
     RECT  21.481 77.208 21.564 77.952 ;
     RECT  21.481 77.952 21.516 77.976 ;
     RECT  21.481 77.976 21.564 78.72 ;
     RECT  21.481 78.72 21.516 78.744 ;
     RECT  21.481 78.744 21.564 79.488 ;
     RECT  21.481 79.488 21.516 79.512 ;
     RECT  21.481 79.512 21.564 80.256 ;
     RECT  21.481 80.256 21.516 80.28 ;
     RECT  21.481 80.28 21.564 81.072 ;
     RECT  21.481 81.072 21.516 81.096 ;
     RECT  21.481 81.096 21.564 81.84 ;
     RECT  21.481 81.84 21.516 81.864 ;
     RECT  21.481 81.864 21.564 82.608 ;
     RECT  21.481 82.608 21.516 82.632 ;
     RECT  21.481 82.632 21.564 83.376 ;
     RECT  21.481 83.376 21.516 83.4 ;
     RECT  21.481 83.4 21.564 84.144 ;
     RECT  21.481 84.144 21.516 84.168 ;
     RECT  21.481 84.168 21.564 84.96 ;
     RECT  21.481 84.96 21.516 84.984 ;
     RECT  21.481 84.984 21.564 85.728 ;
     RECT  21.481 85.728 21.516 85.752 ;
     RECT  21.481 85.752 21.564 86.496 ;
     RECT  21.481 86.496 21.516 86.52 ;
     RECT  21.481 86.52 21.564 87.264 ;
     RECT  21.481 87.264 21.516 87.288 ;
     RECT  21.481 87.288 21.564 88.032 ;
     RECT  21.481 88.032 21.516 88.056 ;
     RECT  21.481 88.056 21.564 88.848 ;
     RECT  21.481 88.848 21.516 88.872 ;
     RECT  21.481 88.872 21.564 89.616 ;
     RECT  21.481 89.616 21.516 89.64 ;
     RECT  21.481 89.64 21.564 90.384 ;
     RECT  21.481 90.384 21.516 90.408 ;
     RECT  21.481 90.408 21.564 91.152 ;
     RECT  21.481 91.152 21.516 91.176 ;
     RECT  21.481 91.176 21.564 91.92 ;
     RECT  21.481 91.92 21.516 91.944 ;
     RECT  21.481 91.944 21.564 92.688 ;
     RECT  21.481 92.688 21.516 92.712 ;
     RECT  21.481 92.712 21.564 93.504 ;
     RECT  21.481 93.504 21.516 93.528 ;
     RECT  21.481 93.528 21.564 94.272 ;
     RECT  21.481 94.272 21.516 94.296 ;
     RECT  21.481 94.296 21.564 95.04 ;
     RECT  21.481 95.04 21.516 95.064 ;
     RECT  21.481 95.064 21.564 95.808 ;
     RECT  21.481 95.808 21.516 95.832 ;
     RECT  21.481 95.832 21.564 96.576 ;
     RECT  21.481 96.576 21.516 96.6 ;
     RECT  21.481 96.6 21.564 97.392 ;
     RECT  21.481 97.392 21.516 97.416 ;
     RECT  21.481 97.416 21.564 98.16 ;
     RECT  21.481 98.16 21.516 98.184 ;
     RECT  21.481 98.184 21.564 98.928 ;
     RECT  21.481 98.928 21.516 98.952 ;
     RECT  21.481 98.952 21.564 99.696 ;
     RECT  21.481 99.696 21.516 99.72 ;
     RECT  21.481 99.72 21.564 100.464 ;
     RECT  21.481 100.464 21.516 100.488 ;
     RECT  21.481 100.488 21.564 101.28 ;
     RECT  21.481 101.28 21.516 101.304 ;
     RECT  21.481 101.304 21.564 102.048 ;
     RECT  21.481 102.048 21.516 102.072 ;
     RECT  21.481 102.072 21.564 102.816 ;
     RECT  21.481 102.816 21.516 102.84 ;
     RECT  21.481 102.84 21.564 103.584 ;
     RECT  21.481 103.584 21.516 103.608 ;
     RECT  21.481 103.608 21.564 104.352 ;
     RECT  21.481 104.352 21.516 104.376 ;
     RECT  21.481 104.376 21.564 105.168 ;
     RECT  21.481 105.168 21.516 105.192 ;
     RECT  21.481 105.192 21.564 105.936 ;
     RECT  21.481 105.936 21.516 105.96 ;
     RECT  21.481 105.96 21.564 106.704 ;
     RECT  21.481 106.704 21.516 106.728 ;
     RECT  21.481 106.728 21.564 107.472 ;
     RECT  21.481 107.472 21.516 107.496 ;
     RECT  21.481 107.496 21.564 108.24 ;
     RECT  21.481 108.24 21.516 108.264 ;
     RECT  21.481 108.264 21.564 109.056 ;
     RECT  21.481 109.056 21.516 109.08 ;
     RECT  21.481 109.08 21.564 109.824 ;
     RECT  21.481 109.824 21.516 109.848 ;
     RECT  21.481 109.848 21.564 110.592 ;
     RECT  21.481 110.592 21.516 110.616 ;
     RECT  21.481 110.616 21.564 111.36 ;
     RECT  21.481 111.36 21.516 111.384 ;
     RECT  21.481 111.384 21.564 112.128 ;
     RECT  21.481 112.128 21.516 112.152 ;
     RECT  21.481 112.152 21.564 112.944 ;
     RECT  21.481 112.944 21.516 112.968 ;
     RECT  21.481 112.968 21.564 113.712 ;
     RECT  21.481 113.712 21.516 113.736 ;
     RECT  21.481 113.736 21.564 114.48 ;
     RECT  21.481 114.48 21.516 114.504 ;
     RECT  21.481 114.504 21.564 115.248 ;
     RECT  21.481 115.248 21.516 115.272 ;
     RECT  21.481 115.272 21.564 116.016 ;
     RECT  21.481 116.016 21.516 116.04 ;
     RECT  21.481 116.04 21.564 116.832 ;
     RECT  21.481 116.832 21.516 116.856 ;
     RECT  21.481 116.856 21.564 117.6 ;
     RECT  21.481 117.6 21.516 117.624 ;
     RECT  21.481 117.624 21.564 118.368 ;
     RECT  21.481 118.368 21.516 118.392 ;
     RECT  21.481 118.392 21.564 119.136 ;
     RECT  21.481 119.136 21.516 119.16 ;
     RECT  21.481 119.16 21.564 119.904 ;
     RECT  21.481 119.904 21.516 119.928 ;
     RECT  21.481 119.928 21.564 120.72 ;
     RECT  21.481 120.72 21.516 120.744 ;
     RECT  21.481 120.744 21.564 121.488 ;
     RECT  21.481 121.488 21.516 121.512 ;
     RECT  21.481 121.512 21.564 122.256 ;
     RECT  21.481 122.256 21.516 122.28 ;
     RECT  21.481 122.28 21.564 123.024 ;
     RECT  21.481 123.024 21.516 123.048 ;
     RECT  21.481 123.048 21.564 123.792 ;
     RECT  21.481 123.792 21.516 123.816 ;
     RECT  21.481 123.816 21.564 124.56 ;
     RECT  21.481 124.56 21.516 124.584 ;
     RECT  21.481 124.584 21.564 125.376 ;
     RECT  21.481 125.376 21.516 125.4 ;
     RECT  21.481 125.4 21.564 126.144 ;
     RECT  21.481 126.144 21.516 126.168 ;
     RECT  21.481 126.168 21.564 126.912 ;
     RECT  21.481 126.912 21.516 126.936 ;
     RECT  21.481 126.936 21.564 127.68 ;
     RECT  21.481 127.68 21.516 127.704 ;
     RECT  21.481 127.704 21.564 128.448 ;
     RECT  21.481 128.448 21.516 128.472 ;
     RECT  21.481 128.472 21.564 129.264 ;
     RECT  21.481 129.264 21.516 129.288 ;
     RECT  21.481 129.288 21.564 130.032 ;
     RECT  21.481 130.032 21.516 130.056 ;
     RECT  21.481 130.056 21.564 130.8 ;
     RECT  21.481 130.8 21.516 130.824 ;
     RECT  21.481 130.824 21.564 131.568 ;
     RECT  21.481 131.568 21.516 131.592 ;
     RECT  21.481 131.592 21.564 132.336 ;
     RECT  21.481 132.336 21.516 132.36 ;
     RECT  21.481 132.36 21.564 133.152 ;
     RECT  21.481 133.152 21.516 133.176 ;
     RECT  21.481 133.176 21.564 133.92 ;
     RECT  21.481 133.92 21.516 133.944 ;
     RECT  21.481 133.944 21.564 134.688 ;
     RECT  21.481 134.688 21.516 134.712 ;
     RECT  21.481 134.712 21.564 135.456 ;
     RECT  21.481 135.456 21.516 135.48 ;
     RECT  21.481 135.48 21.564 136.224 ;
     RECT  21.481 136.224 21.516 136.248 ;
     RECT  21.481 136.248 21.564 137.04 ;
     RECT  21.481 137.04 21.516 137.064 ;
     RECT  21.481 137.064 21.564 137.808 ;
     RECT  21.481 137.808 21.516 137.832 ;
     RECT  21.481 137.832 21.564 138.576 ;
     RECT  21.481 138.576 21.516 138.6 ;
     RECT  21.481 138.6 21.564 139.344 ;
     RECT  21.481 139.344 21.516 139.368 ;
     RECT  21.481 139.368 21.564 140.112 ;
     RECT  21.481 140.112 21.516 140.136 ;
     RECT  21.481 140.136 21.564 140.928 ;
     RECT  21.481 140.928 21.516 140.952 ;
     RECT  21.481 140.952 21.564 141.696 ;
     RECT  21.481 141.696 21.516 141.72 ;
     RECT  21.481 141.72 21.564 142.464 ;
     RECT  21.481 142.464 21.516 142.488 ;
     RECT  21.481 142.488 21.564 143.232 ;
     RECT  21.481 143.232 21.516 143.256 ;
    LAYER M5 ;
     RECT  2.4 2.137 2.52 2.151 ;
     RECT  5.1 2.137 5.22 2.151 ;
     RECT  7.8 2.137 7.92 2.151 ;
     RECT  10.5 2.137 10.62 2.151 ;
     RECT  13.2 2.137 13.32 2.151 ;
     RECT  15.9 2.137 16.02 2.151 ;
     RECT  18.6 2.137 18.72 2.151 ;
     RECT  5.1 2.151 5.412 2.677 ;
     RECT  7.8 2.151 8.112 5.029 ;
     RECT  4.512 2.677 5.412 7.381 ;
     RECT  4.512 7.381 5.784 8.675 ;
     RECT  2.4 2.151 2.712 9.493 ;
     RECT  2.4 9.493 3.672 11.941 ;
     RECT  2.4 11.941 3.96 11.987 ;
     RECT  3.936 11.987 3.96 15.395 ;
     RECT  5.1 8.675 5.784 15.877 ;
     RECT  4.512 15.877 5.784 17.317 ;
     RECT  7.056 5.029 8.112 17.317 ;
     RECT  4.512 17.317 8.112 18.851 ;
     RECT  5.1 18.851 8.112 19.909 ;
     RECT  4.272 19.909 8.112 21.395 ;
     RECT  4.416 21.395 8.112 24.419 ;
     RECT  4.464 24.419 8.112 26.243 ;
     RECT  6.672 26.243 8.112 29.749 ;
     RECT  6.672 29.749 8.232 29.795 ;
     RECT  4.464 26.243 5.412 30.517 ;
     RECT  4.272 30.517 5.412 34.355 ;
     RECT  7.8 29.795 8.232 36.035 ;
     RECT  4.512 34.355 5.412 36.515 ;
     RECT  6.672 29.795 6.696 38.389 ;
     RECT  6.528 38.389 6.696 38.435 ;
     RECT  2.4 11.987 2.712 38.725 ;
     RECT  5.1 36.515 5.412 38.725 ;
     RECT  6.528 38.435 6.552 38.725 ;
     RECT  5.1 38.725 6.552 42.325 ;
     RECT  7.8 36.035 8.112 42.325 ;
     RECT  5.1 42.325 8.112 43.141 ;
     RECT  2.4 38.725 3.384 43.187 ;
     RECT  4.656 43.141 8.112 46.405 ;
     RECT  3.984 46.405 8.112 46.979 ;
     RECT  4.32 46.979 8.112 49.381 ;
     RECT  4.272 49.381 8.112 50.147 ;
     RECT  4.272 50.147 6.552 53.603 ;
     RECT  5.1 53.603 6.552 54.565 ;
     RECT  4.56 54.565 6.552 54.709 ;
     RECT  4.416 54.709 6.552 55.523 ;
     RECT  4.416 55.523 6.456 57.059 ;
     RECT  7.8 50.147 8.112 58.117 ;
     RECT  4.032 59.221 4.056 61.765 ;
     RECT  5.1 57.059 5.592 61.765 ;
     RECT  4.032 61.765 5.592 61.811 ;
     RECT  7.392 58.117 8.112 62.581 ;
     RECT  4.512 61.811 5.592 63.205 ;
     RECT  7.056 62.581 8.112 67.141 ;
     RECT  7.008 67.141 8.112 68.819 ;
     RECT  4.32 63.205 5.592 70.739 ;
     RECT  7.056 68.819 8.112 72.419 ;
     RECT  5.1 70.739 5.592 72.901 ;
     RECT  7.8 72.419 8.112 73.333 ;
     RECT  5.1 72.901 5.976 75.013 ;
     RECT  4.32 75.013 5.976 81.491 ;
     RECT  4.656 81.491 5.976 83.795 ;
     RECT  5.1 83.795 5.976 88.885 ;
     RECT  7.8 73.333 8.232 89.555 ;
     RECT  4.944 88.885 5.976 89.845 ;
     RECT  7.8 89.555 8.112 90.037 ;
     RECT  4.56 89.845 5.976 90.565 ;
     RECT  4.56 90.565 6.12 92.293 ;
     RECT  7.488 90.037 8.112 92.293 ;
     RECT  4.56 92.293 8.112 92.821 ;
     RECT  4.32 92.821 8.112 94.307 ;
     RECT  7.056 94.307 8.112 101.125 ;
     RECT  7.056 101.125 8.232 101.171 ;
     RECT  4.32 94.307 5.976 102.083 ;
     RECT  5.1 102.083 5.976 103.093 ;
     RECT  4.512 103.093 5.976 104.915 ;
     RECT  7.8 101.171 8.232 107.315 ;
     RECT  5.1 104.915 5.976 109.285 ;
     RECT  4.32 109.285 5.976 109.957 ;
     RECT  4.32 109.957 6.072 111.299 ;
     RECT  5.1 111.299 6.072 112.933 ;
     RECT  7.8 107.315 8.112 113.845 ;
     RECT  4.512 112.933 6.072 116.243 ;
     RECT  2.4 43.187 2.712 117.445 ;
     RECT  4.512 116.243 5.976 117.491 ;
     RECT  2.4 117.445 3.48 120.757 ;
     RECT  5.1 117.491 5.976 122.533 ;
     RECT  7.056 113.845 8.112 122.533 ;
     RECT  2.4 120.757 3.672 123.731 ;
     RECT  5.1 122.533 8.112 124.213 ;
     RECT  4.416 124.213 8.112 126.563 ;
     RECT  4.512 126.563 8.112 126.659 ;
     RECT  4.512 126.659 5.976 129.925 ;
     RECT  4.464 129.925 5.976 133.093 ;
     RECT  4.32 133.093 5.976 139.525 ;
     RECT  7.056 126.659 8.112 141.395 ;
     RECT  4.224 139.525 5.976 142.547 ;
     RECT  2.4 123.731 2.712 144.729 ;
     RECT  7.8 141.395 8.112 144.729 ;
     RECT  10.5 2.151 10.812 144.729 ;
     RECT  13.2 2.151 13.512 144.729 ;
     RECT  15.9 2.151 16.212 144.729 ;
     RECT  18.6 2.151 18.912 144.729 ;
     RECT  2.4 144.729 2.52 144.743 ;
     RECT  5.1 142.547 5.976 144.743 ;
     RECT  7.8 144.729 7.92 144.743 ;
     RECT  10.5 144.729 10.62 144.743 ;
     RECT  13.2 144.729 13.32 144.743 ;
     RECT  15.9 144.729 16.02 144.743 ;
     RECT  18.6 144.729 18.72 144.743 ;
     RECT  5.952 144.743 5.976 146.771 ;
     RECT  5.784 7.381 7.056 17.317 ;
     RECT  4.512 8.675 5.1 9.493 ;
     RECT  3.672 9.493 5.1 11.941 ;
     RECT  3.96 11.941 5.1 15.395 ;
     RECT  2.712 11.987 3.936 15.395 ;
     RECT  4.512 15.395 5.1 15.877 ;
     RECT  4.512 18.851 5.1 19.909 ;
     RECT  5.412 26.243 6.672 38.389 ;
     RECT  6.696 29.795 7.8 38.435 ;
     RECT  5.412 38.389 6.528 38.725 ;
     RECT  6.552 38.435 7.8 42.325 ;
     RECT  3.384 43.141 4.656 43.187 ;
     RECT  2.712 46.405 3.984 46.979 ;
     RECT  6.552 50.147 7.8 55.523 ;
     RECT  4.416 53.603 5.1 54.565 ;
     RECT  4.416 54.565 4.56 54.709 ;
     RECT  6.456 55.523 7.8 57.059 ;
     RECT  7.392 57.059 7.8 58.117 ;
     RECT  2.712 59.221 4.032 61.811 ;
     RECT  4.056 59.221 5.1 61.765 ;
     RECT  4.32 61.811 4.512 63.205 ;
     RECT  5.592 62.581 7.056 67.141 ;
     RECT  5.592 67.141 7.008 68.819 ;
     RECT  5.592 68.819 7.056 72.419 ;
     RECT  5.592 72.419 5.976 72.901 ;
     RECT  5.976 90.037 7.488 90.565 ;
     RECT  6.12 90.565 7.488 92.293 ;
     RECT  5.976 94.307 7.056 101.171 ;
     RECT  4.512 102.083 5.1 103.093 ;
     RECT  6.072 113.845 7.056 116.243 ;
     RECT  5.976 116.243 7.056 122.533 ;
     RECT  3.48 117.445 4.512 117.491 ;
     RECT  3.672 120.757 5.1 123.731 ;
     RECT  4.416 123.731 5.1 124.213 ;
     RECT  5.976 126.659 7.056 141.395 ;
     RECT  2.712 139.525 4.224 142.547 ;
  END
END qfd_coll_eslice182
END LIBRARY
